VERSION 5.8 ;
BUSBITCHARS "[]" ;
DIVIDERCHAR "/" ;
UNITS
    DATABASE MICRONS 1000 ;
END UNITS

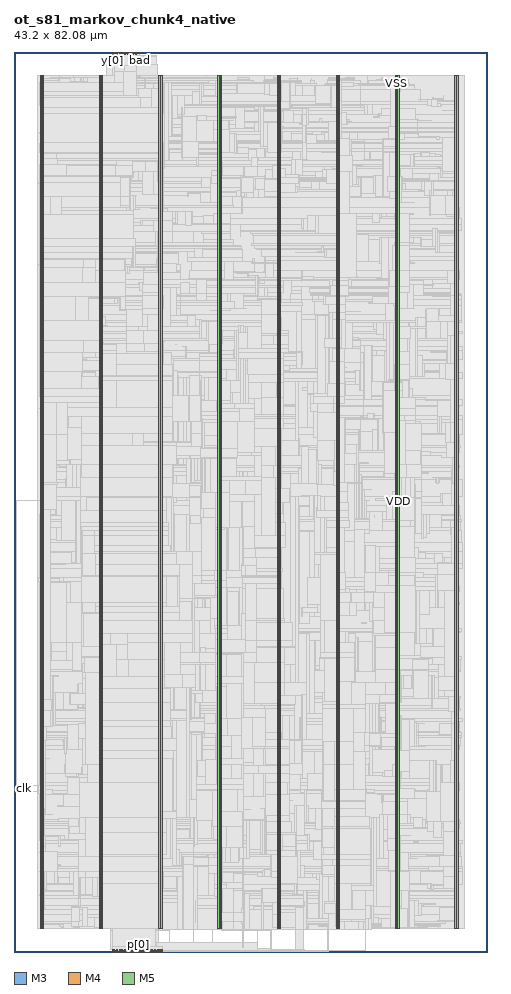
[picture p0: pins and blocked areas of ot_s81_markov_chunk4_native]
MACRO ot_s81_markov_chunk4_native
  FOREIGN ot_s81_markov_chunk4_native 0 0 ;
  CLASS BLOCK ;
  SIZE 43.2 BY 82.08 ;
  PIN bad
    DIRECTION OUTPUT ;
    USE SIGNAL ;
    PORT
      LAYER M3 ;
        RECT  11.448 81.936 11.466 82.08 ;
    END
  END bad
  PIN clk
    DIRECTION INPUT ;
    USE SIGNAL ;
    PORT
      LAYER M4 ;
        RECT  0 14.88 0.192 14.904 ;
    END
  END clk
  PIN p[0]
    DIRECTION INPUT ;
    USE SIGNAL ;
    PORT
      LAYER M3 ;
        RECT  11.304 0 11.322 0.144 ;
    END
  END p[0]
  PIN p[10]
    DIRECTION INPUT ;
    USE SIGNAL ;
    PORT
      LAYER M3 ;
        RECT  12.024 0 12.042 0.144 ;
    END
  END p[10]
  PIN p[11]
    DIRECTION INPUT ;
    USE SIGNAL ;
    PORT
      LAYER M5 ;
        RECT  12.048 0 12.072 0.192 ;
    END
  END p[11]
  PIN p[12]
    DIRECTION INPUT ;
    USE SIGNAL ;
    PORT
      LAYER M3 ;
        RECT  12.168 0 12.186 0.144 ;
    END
  END p[12]
  PIN p[13]
    DIRECTION INPUT ;
    USE SIGNAL ;
    PORT
      LAYER M5 ;
        RECT  12.192 0 12.216 0.192 ;
    END
  END p[13]
  PIN p[14]
    DIRECTION INPUT ;
    USE SIGNAL ;
    PORT
      LAYER M3 ;
        RECT  12.312 0 12.33 0.144 ;
    END
  END p[14]
  PIN p[15]
    DIRECTION INPUT ;
    USE SIGNAL ;
    PORT
      LAYER M5 ;
        RECT  12.336 0 12.36 0.192 ;
    END
  END p[15]
  PIN p[16]
    DIRECTION INPUT ;
    USE SIGNAL ;
    PORT
      LAYER M3 ;
        RECT  12.456 0 12.474 0.144 ;
    END
  END p[16]
  PIN p[17]
    DIRECTION INPUT ;
    USE SIGNAL ;
    PORT
      LAYER M5 ;
        RECT  12.48 0 12.504 0.192 ;
    END
  END p[17]
  PIN p[18]
    DIRECTION INPUT ;
    USE SIGNAL ;
    PORT
      LAYER M3 ;
        RECT  12.6 0 12.618 0.144 ;
    END
  END p[18]
  PIN p[19]
    DIRECTION INPUT ;
    USE SIGNAL ;
    PORT
      LAYER M5 ;
        RECT  12.624 0 12.648 0.192 ;
    END
  END p[19]
  PIN p[1]
    DIRECTION INPUT ;
    USE SIGNAL ;
    PORT
      LAYER M5 ;
        RECT  11.328 0 11.352 0.192 ;
    END
  END p[1]
  PIN p[20]
    DIRECTION INPUT ;
    USE SIGNAL ;
    PORT
      LAYER M3 ;
        RECT  12.744 0 12.762 0.144 ;
    END
  END p[20]
  PIN p[21]
    DIRECTION INPUT ;
    USE SIGNAL ;
    PORT
      LAYER M5 ;
        RECT  12.768 0 12.792 0.192 ;
    END
  END p[21]
  PIN p[22]
    DIRECTION INPUT ;
    USE SIGNAL ;
    PORT
      LAYER M3 ;
        RECT  12.888 0 12.906 0.144 ;
    END
  END p[22]
  PIN p[23]
    DIRECTION INPUT ;
    USE SIGNAL ;
    PORT
      LAYER M5 ;
        RECT  12.912 0 12.936 0.192 ;
    END
  END p[23]
  PIN p[24]
    DIRECTION INPUT ;
    USE SIGNAL ;
    PORT
      LAYER M3 ;
        RECT  13.032 0 13.05 0.144 ;
    END
  END p[24]
  PIN p[25]
    DIRECTION INPUT ;
    USE SIGNAL ;
    PORT
      LAYER M5 ;
        RECT  13.056 0 13.08 0.192 ;
    END
  END p[25]
  PIN p[26]
    DIRECTION INPUT ;
    USE SIGNAL ;
    PORT
      LAYER M3 ;
        RECT  13.176 0 13.194 0.144 ;
    END
  END p[26]
  PIN p[27]
    DIRECTION INPUT ;
    USE SIGNAL ;
    PORT
      LAYER M5 ;
        RECT  13.2 0 13.224 0.192 ;
    END
  END p[27]
  PIN p[28]
    DIRECTION INPUT ;
    USE SIGNAL ;
    PORT
      LAYER M3 ;
        RECT  13.32 0 13.338 0.144 ;
    END
  END p[28]
  PIN p[29]
    DIRECTION INPUT ;
    USE SIGNAL ;
    PORT
      LAYER M5 ;
        RECT  13.344 0 13.368 0.192 ;
    END
  END p[29]
  PIN p[2]
    DIRECTION INPUT ;
    USE SIGNAL ;
    PORT
      LAYER M3 ;
        RECT  11.448 0 11.466 0.144 ;
    END
  END p[2]
  PIN p[30]
    DIRECTION INPUT ;
    USE SIGNAL ;
    PORT
      LAYER M3 ;
        RECT  13.464 0 13.482 0.144 ;
    END
  END p[30]
  PIN p[31]
    DIRECTION INPUT ;
    USE SIGNAL ;
    PORT
      LAYER M5 ;
        RECT  13.488 0 13.512 0.192 ;
    END
  END p[31]
  PIN p[3]
    DIRECTION INPUT ;
    USE SIGNAL ;
    PORT
      LAYER M5 ;
        RECT  11.472 0 11.496 0.192 ;
    END
  END p[3]
  PIN p[4]
    DIRECTION INPUT ;
    USE SIGNAL ;
    PORT
      LAYER M3 ;
        RECT  11.592 0 11.61 0.144 ;
    END
  END p[4]
  PIN p[5]
    DIRECTION INPUT ;
    USE SIGNAL ;
    PORT
      LAYER M5 ;
        RECT  11.616 0 11.64 0.192 ;
    END
  END p[5]
  PIN p[6]
    DIRECTION INPUT ;
    USE SIGNAL ;
    PORT
      LAYER M3 ;
        RECT  11.736 0 11.754 0.144 ;
    END
  END p[6]
  PIN p[7]
    DIRECTION INPUT ;
    USE SIGNAL ;
    PORT
      LAYER M5 ;
        RECT  11.76 0 11.784 0.192 ;
    END
  END p[7]
  PIN p[8]
    DIRECTION INPUT ;
    USE SIGNAL ;
    PORT
      LAYER M3 ;
        RECT  11.88 0 11.898 0.144 ;
    END
  END p[8]
  PIN p[9]
    DIRECTION INPUT ;
    USE SIGNAL ;
    PORT
      LAYER M5 ;
        RECT  11.904 0 11.928 0.192 ;
    END
  END p[9]
  PIN rst_n
    DIRECTION INPUT ;
    USE SIGNAL ;
    PORT
      LAYER M4 ;
        RECT  0 15.024 0.192 15.048 ;
    END
  END rst_n
  PIN sum[0]
    DIRECTION INPUT ;
    USE SIGNAL ;
    PORT
      LAYER M3 ;
        RECT  9 0 9.018 0.144 ;
    END
  END sum[0]
  PIN sum[10]
    DIRECTION INPUT ;
    USE SIGNAL ;
    PORT
      LAYER M3 ;
        RECT  9.72 0 9.738 0.144 ;
    END
  END sum[10]
  PIN sum[11]
    DIRECTION INPUT ;
    USE SIGNAL ;
    PORT
      LAYER M5 ;
        RECT  9.744 0 9.768 0.192 ;
    END
  END sum[11]
  PIN sum[12]
    DIRECTION INPUT ;
    USE SIGNAL ;
    PORT
      LAYER M3 ;
        RECT  9.864 0 9.882 0.144 ;
    END
  END sum[12]
  PIN sum[13]
    DIRECTION INPUT ;
    USE SIGNAL ;
    PORT
      LAYER M5 ;
        RECT  9.888 0 9.912 0.192 ;
    END
  END sum[13]
  PIN sum[14]
    DIRECTION INPUT ;
    USE SIGNAL ;
    PORT
      LAYER M3 ;
        RECT  10.008 0 10.026 0.144 ;
    END
  END sum[14]
  PIN sum[15]
    DIRECTION INPUT ;
    USE SIGNAL ;
    PORT
      LAYER M5 ;
        RECT  10.032 0 10.056 0.192 ;
    END
  END sum[15]
  PIN sum[16]
    DIRECTION INPUT ;
    USE SIGNAL ;
    PORT
      LAYER M3 ;
        RECT  10.152 0 10.17 0.144 ;
    END
  END sum[16]
  PIN sum[17]
    DIRECTION INPUT ;
    USE SIGNAL ;
    PORT
      LAYER M5 ;
        RECT  10.176 0 10.2 0.192 ;
    END
  END sum[17]
  PIN sum[18]
    DIRECTION INPUT ;
    USE SIGNAL ;
    PORT
      LAYER M3 ;
        RECT  10.296 0 10.314 0.144 ;
    END
  END sum[18]
  PIN sum[19]
    DIRECTION INPUT ;
    USE SIGNAL ;
    PORT
      LAYER M5 ;
        RECT  10.32 0 10.344 0.192 ;
    END
  END sum[19]
  PIN sum[1]
    DIRECTION INPUT ;
    USE SIGNAL ;
    PORT
      LAYER M5 ;
        RECT  9.024 0 9.048 0.192 ;
    END
  END sum[1]
  PIN sum[20]
    DIRECTION INPUT ;
    USE SIGNAL ;
    PORT
      LAYER M3 ;
        RECT  10.44 0 10.458 0.144 ;
    END
  END sum[20]
  PIN sum[21]
    DIRECTION INPUT ;
    USE SIGNAL ;
    PORT
      LAYER M5 ;
        RECT  10.464 0 10.488 0.192 ;
    END
  END sum[21]
  PIN sum[22]
    DIRECTION INPUT ;
    USE SIGNAL ;
    PORT
      LAYER M3 ;
        RECT  10.584 0 10.602 0.144 ;
    END
  END sum[22]
  PIN sum[23]
    DIRECTION INPUT ;
    USE SIGNAL ;
    PORT
      LAYER M5 ;
        RECT  10.608 0 10.632 0.192 ;
    END
  END sum[23]
  PIN sum[24]
    DIRECTION INPUT ;
    USE SIGNAL ;
    PORT
      LAYER M3 ;
        RECT  10.728 0 10.746 0.144 ;
    END
  END sum[24]
  PIN sum[25]
    DIRECTION INPUT ;
    USE SIGNAL ;
    PORT
      LAYER M5 ;
        RECT  10.752 0 10.776 0.192 ;
    END
  END sum[25]
  PIN sum[26]
    DIRECTION INPUT ;
    USE SIGNAL ;
    PORT
      LAYER M3 ;
        RECT  10.872 0 10.89 0.144 ;
    END
  END sum[26]
  PIN sum[27]
    DIRECTION INPUT ;
    USE SIGNAL ;
    PORT
      LAYER M5 ;
        RECT  10.896 0 10.92 0.192 ;
    END
  END sum[27]
  PIN sum[28]
    DIRECTION INPUT ;
    USE SIGNAL ;
    PORT
      LAYER M3 ;
        RECT  11.016 0 11.034 0.144 ;
    END
  END sum[28]
  PIN sum[29]
    DIRECTION INPUT ;
    USE SIGNAL ;
    PORT
      LAYER M5 ;
        RECT  11.04 0 11.064 0.192 ;
    END
  END sum[29]
  PIN sum[2]
    DIRECTION INPUT ;
    USE SIGNAL ;
    PORT
      LAYER M3 ;
        RECT  9.144 0 9.162 0.144 ;
    END
  END sum[2]
  PIN sum[30]
    DIRECTION INPUT ;
    USE SIGNAL ;
    PORT
      LAYER M3 ;
        RECT  11.16 0 11.178 0.144 ;
    END
  END sum[30]
  PIN sum[31]
    DIRECTION INPUT ;
    USE SIGNAL ;
    PORT
      LAYER M5 ;
        RECT  11.184 0 11.208 0.192 ;
    END
  END sum[31]
  PIN sum[3]
    DIRECTION INPUT ;
    USE SIGNAL ;
    PORT
      LAYER M5 ;
        RECT  9.168 0 9.192 0.192 ;
    END
  END sum[3]
  PIN sum[4]
    DIRECTION INPUT ;
    USE SIGNAL ;
    PORT
      LAYER M3 ;
        RECT  9.288 0 9.306 0.144 ;
    END
  END sum[4]
  PIN sum[5]
    DIRECTION INPUT ;
    USE SIGNAL ;
    PORT
      LAYER M5 ;
        RECT  9.312 0 9.336 0.192 ;
    END
  END sum[5]
  PIN sum[6]
    DIRECTION INPUT ;
    USE SIGNAL ;
    PORT
      LAYER M3 ;
        RECT  9.432 0 9.45 0.144 ;
    END
  END sum[6]
  PIN sum[7]
    DIRECTION INPUT ;
    USE SIGNAL ;
    PORT
      LAYER M5 ;
        RECT  9.456 0 9.48 0.192 ;
    END
  END sum[7]
  PIN sum[8]
    DIRECTION INPUT ;
    USE SIGNAL ;
    PORT
      LAYER M3 ;
        RECT  9.576 0 9.594 0.144 ;
    END
  END sum[8]
  PIN sum[9]
    DIRECTION INPUT ;
    USE SIGNAL ;
    PORT
      LAYER M5 ;
        RECT  9.6 0 9.624 0.192 ;
    END
  END sum[9]
  PIN vin
    DIRECTION INPUT ;
    USE SIGNAL ;
    PORT
      LAYER M4 ;
        RECT  0 15.168 0.192 15.192 ;
    END
  END vin
  PIN vout
    DIRECTION OUTPUT ;
    USE SIGNAL ;
    PORT
      LAYER M3 ;
        RECT  11.304 81.936 11.322 82.08 ;
    END
  END vout
  PIN y[0]
    DIRECTION OUTPUT ;
    USE SIGNAL ;
    PORT
      LAYER M3 ;
        RECT  9 81.936 9.018 82.08 ;
    END
  END y[0]
  PIN y[10]
    DIRECTION OUTPUT ;
    USE SIGNAL ;
    PORT
      LAYER M3 ;
        RECT  9.72 81.936 9.738 82.08 ;
    END
  END y[10]
  PIN y[11]
    DIRECTION OUTPUT ;
    USE SIGNAL ;
    PORT
      LAYER M5 ;
        RECT  9.744 81.888 9.768 82.08 ;
    END
  END y[11]
  PIN y[12]
    DIRECTION OUTPUT ;
    USE SIGNAL ;
    PORT
      LAYER M3 ;
        RECT  9.864 81.936 9.882 82.08 ;
    END
  END y[12]
  PIN y[13]
    DIRECTION OUTPUT ;
    USE SIGNAL ;
    PORT
      LAYER M5 ;
        RECT  9.888 81.888 9.912 82.08 ;
    END
  END y[13]
  PIN y[14]
    DIRECTION OUTPUT ;
    USE SIGNAL ;
    PORT
      LAYER M3 ;
        RECT  10.008 81.936 10.026 82.08 ;
    END
  END y[14]
  PIN y[15]
    DIRECTION OUTPUT ;
    USE SIGNAL ;
    PORT
      LAYER M5 ;
        RECT  10.032 81.888 10.056 82.08 ;
    END
  END y[15]
  PIN y[16]
    DIRECTION OUTPUT ;
    USE SIGNAL ;
    PORT
      LAYER M3 ;
        RECT  10.152 81.936 10.17 82.08 ;
    END
  END y[16]
  PIN y[17]
    DIRECTION OUTPUT ;
    USE SIGNAL ;
    PORT
      LAYER M5 ;
        RECT  10.176 81.888 10.2 82.08 ;
    END
  END y[17]
  PIN y[18]
    DIRECTION OUTPUT ;
    USE SIGNAL ;
    PORT
      LAYER M3 ;
        RECT  10.296 81.936 10.314 82.08 ;
    END
  END y[18]
  PIN y[19]
    DIRECTION OUTPUT ;
    USE SIGNAL ;
    PORT
      LAYER M5 ;
        RECT  10.32 81.888 10.344 82.08 ;
    END
  END y[19]
  PIN y[1]
    DIRECTION OUTPUT ;
    USE SIGNAL ;
    PORT
      LAYER M5 ;
        RECT  9.024 81.888 9.048 82.08 ;
    END
  END y[1]
  PIN y[20]
    DIRECTION OUTPUT ;
    USE SIGNAL ;
    PORT
      LAYER M3 ;
        RECT  10.44 81.936 10.458 82.08 ;
    END
  END y[20]
  PIN y[21]
    DIRECTION OUTPUT ;
    USE SIGNAL ;
    PORT
      LAYER M5 ;
        RECT  10.464 81.888 10.488 82.08 ;
    END
  END y[21]
  PIN y[22]
    DIRECTION OUTPUT ;
    USE SIGNAL ;
    PORT
      LAYER M3 ;
        RECT  10.584 81.936 10.602 82.08 ;
    END
  END y[22]
  PIN y[23]
    DIRECTION OUTPUT ;
    USE SIGNAL ;
    PORT
      LAYER M5 ;
        RECT  10.608 81.888 10.632 82.08 ;
    END
  END y[23]
  PIN y[24]
    DIRECTION OUTPUT ;
    USE SIGNAL ;
    PORT
      LAYER M3 ;
        RECT  10.728 81.936 10.746 82.08 ;
    END
  END y[24]
  PIN y[25]
    DIRECTION OUTPUT ;
    USE SIGNAL ;
    PORT
      LAYER M5 ;
        RECT  10.752 81.888 10.776 82.08 ;
    END
  END y[25]
  PIN y[26]
    DIRECTION OUTPUT ;
    USE SIGNAL ;
    PORT
      LAYER M3 ;
        RECT  10.872 81.936 10.89 82.08 ;
    END
  END y[26]
  PIN y[27]
    DIRECTION OUTPUT ;
    USE SIGNAL ;
    PORT
      LAYER M5 ;
        RECT  10.896 81.888 10.92 82.08 ;
    END
  END y[27]
  PIN y[28]
    DIRECTION OUTPUT ;
    USE SIGNAL ;
    PORT
      LAYER M3 ;
        RECT  11.016 81.936 11.034 82.08 ;
    END
  END y[28]
  PIN y[29]
    DIRECTION OUTPUT ;
    USE SIGNAL ;
    PORT
      LAYER M5 ;
        RECT  11.04 81.888 11.064 82.08 ;
    END
  END y[29]
  PIN y[2]
    DIRECTION OUTPUT ;
    USE SIGNAL ;
    PORT
      LAYER M3 ;
        RECT  9.144 81.936 9.162 82.08 ;
    END
  END y[2]
  PIN y[30]
    DIRECTION OUTPUT ;
    USE SIGNAL ;
    PORT
      LAYER M3 ;
        RECT  11.16 81.936 11.178 82.08 ;
    END
  END y[30]
  PIN y[31]
    DIRECTION OUTPUT ;
    USE SIGNAL ;
    PORT
      LAYER M5 ;
        RECT  11.184 81.888 11.208 82.08 ;
    END
  END y[31]
  PIN y[3]
    DIRECTION OUTPUT ;
    USE SIGNAL ;
    PORT
      LAYER M5 ;
        RECT  9.168 81.888 9.192 82.08 ;
    END
  END y[3]
  PIN y[4]
    DIRECTION OUTPUT ;
    USE SIGNAL ;
    PORT
      LAYER M3 ;
        RECT  9.288 81.936 9.306 82.08 ;
    END
  END y[4]
  PIN y[5]
    DIRECTION OUTPUT ;
    USE SIGNAL ;
    PORT
      LAYER M5 ;
        RECT  9.312 81.888 9.336 82.08 ;
    END
  END y[5]
  PIN y[6]
    DIRECTION OUTPUT ;
    USE SIGNAL ;
    PORT
      LAYER M3 ;
        RECT  9.432 81.936 9.45 82.08 ;
    END
  END y[6]
  PIN y[7]
    DIRECTION OUTPUT ;
    USE SIGNAL ;
    PORT
      LAYER M5 ;
        RECT  9.456 81.888 9.48 82.08 ;
    END
  END y[7]
  PIN y[8]
    DIRECTION OUTPUT ;
    USE SIGNAL ;
    PORT
      LAYER M3 ;
        RECT  9.576 81.936 9.594 82.08 ;
    END
  END y[8]
  PIN y[9]
    DIRECTION OUTPUT ;
    USE SIGNAL ;
    PORT
      LAYER M5 ;
        RECT  9.6 81.888 9.624 82.08 ;
    END
  END y[9]
  PIN VDD
    DIRECTION INOUT ;
    USE POWER ;
    PORT
      LAYER M5 ;
        RECT  40.392 2.151 40.512 79.929 ;
        RECT  34.992 2.151 35.112 79.929 ;
        RECT  29.592 2.151 29.712 79.929 ;
        RECT  24.192 2.151 24.312 79.929 ;
        RECT  18.792 2.151 18.912 79.929 ;
        RECT  13.392 2.151 13.512 79.929 ;
        RECT  7.992 2.151 8.112 79.929 ;
        RECT  2.592 2.151 2.712 79.929 ;
    END
  END VDD
  PIN VSS
    DIRECTION INOUT ;
    USE GROUND ;
    PORT
      LAYER M5 ;
        RECT  40.2 2.137 40.32 79.943 ;
        RECT  34.8 2.137 34.92 79.943 ;
        RECT  29.4 2.137 29.52 79.943 ;
        RECT  24 2.137 24.12 79.943 ;
        RECT  18.6 2.137 18.72 79.943 ;
        RECT  13.2 2.137 13.32 79.943 ;
        RECT  7.8 2.137 7.92 79.943 ;
        RECT  2.4 2.137 2.52 79.943 ;
    END
  END VSS
  # OT_OBS_CLOSED layer=M5 d_um=1.536 added=327
  OBS
    LAYER RVTN ;
     RECT  2.16 2.16 41.04 2.295 ;
     RECT  2.16 2.565 41.04 2.835 ;
     RECT  2.16 3.105 41.04 3.375 ;
     RECT  2.16 3.645 41.04 3.915 ;
     RECT  2.16 4.185 41.04 4.455 ;
     RECT  2.16 4.725 41.04 4.995 ;
     RECT  2.16 5.265 41.04 5.535 ;
     RECT  2.16 5.805 41.04 6.075 ;
     RECT  2.16 6.345 41.04 6.615 ;
     RECT  2.16 6.885 41.04 7.155 ;
     RECT  2.16 7.425 41.04 7.695 ;
     RECT  2.16 7.965 41.04 8.235 ;
     RECT  2.16 8.505 41.04 8.775 ;
     RECT  2.16 9.045 41.04 9.315 ;
     RECT  2.16 9.585 41.04 9.855 ;
     RECT  2.16 10.125 41.04 10.395 ;
     RECT  2.16 10.665 41.04 10.935 ;
     RECT  2.16 11.205 41.04 11.475 ;
     RECT  2.16 11.745 41.04 12.015 ;
     RECT  2.16 12.285 41.04 12.555 ;
     RECT  2.16 12.825 41.04 13.095 ;
     RECT  2.16 13.365 41.04 13.635 ;
     RECT  2.16 13.905 41.04 14.175 ;
     RECT  2.16 14.445 41.04 14.715 ;
     RECT  2.16 14.985 41.04 15.255 ;
     RECT  2.16 15.525 41.04 15.795 ;
     RECT  2.16 16.065 41.04 16.335 ;
     RECT  2.16 16.605 41.04 16.875 ;
     RECT  2.16 17.145 41.04 17.415 ;
     RECT  2.16 17.685 41.04 17.955 ;
     RECT  2.16 18.225 41.04 18.495 ;
     RECT  2.16 18.765 41.04 19.035 ;
     RECT  2.16 19.305 41.04 19.575 ;
     RECT  2.16 19.845 41.04 20.115 ;
     RECT  2.16 20.385 41.04 20.655 ;
     RECT  2.16 20.925 41.04 21.195 ;
     RECT  2.16 21.465 41.04 21.735 ;
     RECT  2.16 22.005 41.04 22.275 ;
     RECT  2.16 22.545 41.04 22.815 ;
     RECT  2.16 23.085 41.04 23.355 ;
     RECT  2.16 23.625 41.04 23.895 ;
     RECT  2.16 24.165 41.04 24.435 ;
     RECT  2.16 24.705 41.04 24.975 ;
     RECT  2.16 25.245 41.04 25.515 ;
     RECT  2.16 25.785 41.04 26.055 ;
     RECT  2.16 26.325 41.04 26.595 ;
     RECT  2.16 26.865 41.04 27.135 ;
     RECT  2.16 27.405 41.04 27.675 ;
     RECT  2.16 27.945 41.04 28.215 ;
     RECT  2.16 28.485 41.04 28.755 ;
     RECT  2.16 29.025 41.04 29.295 ;
     RECT  2.16 29.565 41.04 29.835 ;
     RECT  2.16 30.105 41.04 30.375 ;
     RECT  2.16 30.645 41.04 30.915 ;
     RECT  2.16 31.185 41.04 31.455 ;
     RECT  2.16 31.725 41.04 31.995 ;
     RECT  2.16 32.265 41.04 32.535 ;
     RECT  2.16 32.805 41.04 33.075 ;
     RECT  2.16 33.345 41.04 33.615 ;
     RECT  2.16 33.885 41.04 34.155 ;
     RECT  2.16 34.425 41.04 34.695 ;
     RECT  2.16 34.965 41.04 35.235 ;
     RECT  2.16 35.505 41.04 35.775 ;
     RECT  2.16 36.045 41.04 36.315 ;
     RECT  2.16 36.585 41.04 36.855 ;
     RECT  2.16 37.125 41.04 37.395 ;
     RECT  2.16 37.665 41.04 37.935 ;
     RECT  2.16 38.205 41.04 38.475 ;
     RECT  2.16 38.745 41.04 39.015 ;
     RECT  2.16 39.285 41.04 39.555 ;
     RECT  2.16 39.825 41.04 40.095 ;
     RECT  2.16 40.365 41.04 40.635 ;
     RECT  2.16 40.905 41.04 41.175 ;
     RECT  2.16 41.445 41.04 41.715 ;
     RECT  2.16 41.985 41.04 42.255 ;
     RECT  2.16 42.525 41.04 42.795 ;
     RECT  2.16 43.065 41.04 43.335 ;
     RECT  2.16 43.605 41.04 43.875 ;
     RECT  2.16 44.145 41.04 44.415 ;
     RECT  2.16 44.685 41.04 44.955 ;
     RECT  2.16 45.225 41.04 45.495 ;
     RECT  2.16 45.765 41.04 46.035 ;
     RECT  2.16 46.305 41.04 46.575 ;
     RECT  2.16 46.845 41.04 47.115 ;
     RECT  2.16 47.385 41.04 47.655 ;
     RECT  2.16 47.925 41.04 48.195 ;
     RECT  2.16 48.465 41.04 48.735 ;
     RECT  2.16 49.005 41.04 49.275 ;
     RECT  2.16 49.545 41.04 49.815 ;
     RECT  2.16 50.085 41.04 50.355 ;
     RECT  2.16 50.625 41.04 50.895 ;
     RECT  2.16 51.165 41.04 51.435 ;
     RECT  2.16 51.705 41.04 51.975 ;
     RECT  2.16 52.245 41.04 52.515 ;
     RECT  2.16 52.785 41.04 53.055 ;
     RECT  2.16 53.325 41.04 53.595 ;
     RECT  2.16 53.865 41.04 54.135 ;
     RECT  2.16 54.405 41.04 54.675 ;
     RECT  2.16 54.945 41.04 55.215 ;
     RECT  2.16 55.485 41.04 55.755 ;
     RECT  2.16 56.025 41.04 56.295 ;
     RECT  2.16 56.565 41.04 56.835 ;
     RECT  2.16 57.105 41.04 57.375 ;
     RECT  2.16 57.645 41.04 57.915 ;
     RECT  2.16 58.185 41.04 58.455 ;
     RECT  2.16 58.725 41.04 58.995 ;
     RECT  2.16 59.265 41.04 59.535 ;
     RECT  2.16 59.805 41.04 60.075 ;
     RECT  2.16 60.345 41.04 60.615 ;
     RECT  2.16 60.885 41.04 61.155 ;
     RECT  2.16 61.425 41.04 61.695 ;
     RECT  2.16 61.965 41.04 62.235 ;
     RECT  2.16 62.505 41.04 62.775 ;
     RECT  2.16 63.045 41.04 63.315 ;
     RECT  2.16 63.585 41.04 63.855 ;
     RECT  2.16 64.125 41.04 64.395 ;
     RECT  2.16 64.665 41.04 64.935 ;
     RECT  2.16 65.205 41.04 65.475 ;
     RECT  2.16 65.745 41.04 66.015 ;
     RECT  2.16 66.285 41.04 66.555 ;
     RECT  2.16 66.825 41.04 67.095 ;
     RECT  2.16 67.365 41.04 67.635 ;
     RECT  2.16 67.905 41.04 68.175 ;
     RECT  2.16 68.445 41.04 68.715 ;
     RECT  2.16 68.985 41.04 69.255 ;
     RECT  2.16 69.525 41.04 69.795 ;
     RECT  2.16 70.065 41.04 70.335 ;
     RECT  2.16 70.605 41.04 70.875 ;
     RECT  2.16 71.145 41.04 71.415 ;
     RECT  2.16 71.685 41.04 71.955 ;
     RECT  2.16 72.225 41.04 72.495 ;
     RECT  2.16 72.765 41.04 73.035 ;
     RECT  2.16 73.305 41.04 73.575 ;
     RECT  2.16 73.845 41.04 74.115 ;
     RECT  2.16 74.385 41.04 74.655 ;
     RECT  2.16 74.925 41.04 75.195 ;
     RECT  2.16 75.465 41.04 75.735 ;
     RECT  2.16 76.005 41.04 76.275 ;
     RECT  2.16 76.545 41.04 76.815 ;
     RECT  2.16 77.085 41.04 77.355 ;
     RECT  2.16 77.625 41.04 77.895 ;
     RECT  2.16 78.165 41.04 78.435 ;
     RECT  2.16 78.705 41.04 78.975 ;
     RECT  2.16 79.245 41.04 79.515 ;
     RECT  2.16 79.785 41.04 79.92 ;
    LAYER RVTP ;
     RECT  2.16 2.295 41.04 2.565 ;
     RECT  2.16 2.835 41.04 3.105 ;
     RECT  2.16 3.375 41.04 3.645 ;
     RECT  2.16 3.915 41.04 4.185 ;
     RECT  2.16 4.455 41.04 4.725 ;
     RECT  2.16 4.995 41.04 5.265 ;
     RECT  2.16 5.535 41.04 5.805 ;
     RECT  2.16 6.075 41.04 6.345 ;
     RECT  2.16 6.615 41.04 6.885 ;
     RECT  2.16 7.155 41.04 7.425 ;
     RECT  2.16 7.695 41.04 7.965 ;
     RECT  2.16 8.235 41.04 8.505 ;
     RECT  2.16 8.775 41.04 9.045 ;
     RECT  2.16 9.315 41.04 9.585 ;
     RECT  2.16 9.855 41.04 10.125 ;
     RECT  2.16 10.395 41.04 10.665 ;
     RECT  2.16 10.935 41.04 11.205 ;
     RECT  2.16 11.475 41.04 11.745 ;
     RECT  2.16 12.015 41.04 12.285 ;
     RECT  2.16 12.555 41.04 12.825 ;
     RECT  2.16 13.095 41.04 13.365 ;
     RECT  2.16 13.635 41.04 13.905 ;
     RECT  2.16 14.175 41.04 14.445 ;
     RECT  2.16 14.715 41.04 14.985 ;
     RECT  2.16 15.255 41.04 15.525 ;
     RECT  2.16 15.795 41.04 16.065 ;
     RECT  2.16 16.335 41.04 16.605 ;
     RECT  2.16 16.875 41.04 17.145 ;
     RECT  2.16 17.415 41.04 17.685 ;
     RECT  2.16 17.955 41.04 18.225 ;
     RECT  2.16 18.495 41.04 18.765 ;
     RECT  2.16 19.035 41.04 19.305 ;
     RECT  2.16 19.575 41.04 19.845 ;
     RECT  2.16 20.115 41.04 20.385 ;
     RECT  2.16 20.655 41.04 20.925 ;
     RECT  2.16 21.195 41.04 21.465 ;
     RECT  2.16 21.735 41.04 22.005 ;
     RECT  2.16 22.275 41.04 22.545 ;
     RECT  2.16 22.815 41.04 23.085 ;
     RECT  2.16 23.355 41.04 23.625 ;
     RECT  2.16 23.895 41.04 24.165 ;
     RECT  2.16 24.435 41.04 24.705 ;
     RECT  2.16 24.975 41.04 25.245 ;
     RECT  2.16 25.515 41.04 25.785 ;
     RECT  2.16 26.055 41.04 26.325 ;
     RECT  2.16 26.595 41.04 26.865 ;
     RECT  2.16 27.135 41.04 27.405 ;
     RECT  2.16 27.675 41.04 27.945 ;
     RECT  2.16 28.215 41.04 28.485 ;
     RECT  2.16 28.755 41.04 29.025 ;
     RECT  2.16 29.295 41.04 29.565 ;
     RECT  2.16 29.835 41.04 30.105 ;
     RECT  2.16 30.375 41.04 30.645 ;
     RECT  2.16 30.915 41.04 31.185 ;
     RECT  2.16 31.455 41.04 31.725 ;
     RECT  2.16 31.995 41.04 32.265 ;
     RECT  2.16 32.535 41.04 32.805 ;
     RECT  2.16 33.075 41.04 33.345 ;
     RECT  2.16 33.615 41.04 33.885 ;
     RECT  2.16 34.155 41.04 34.425 ;
     RECT  2.16 34.695 41.04 34.965 ;
     RECT  2.16 35.235 41.04 35.505 ;
     RECT  2.16 35.775 41.04 36.045 ;
     RECT  2.16 36.315 41.04 36.585 ;
     RECT  2.16 36.855 41.04 37.125 ;
     RECT  2.16 37.395 41.04 37.665 ;
     RECT  2.16 37.935 41.04 38.205 ;
     RECT  2.16 38.475 41.04 38.745 ;
     RECT  2.16 39.015 41.04 39.285 ;
     RECT  2.16 39.555 41.04 39.825 ;
     RECT  2.16 40.095 41.04 40.365 ;
     RECT  2.16 40.635 41.04 40.905 ;
     RECT  2.16 41.175 41.04 41.445 ;
     RECT  2.16 41.715 41.04 41.985 ;
     RECT  2.16 42.255 41.04 42.525 ;
     RECT  2.16 42.795 41.04 43.065 ;
     RECT  2.16 43.335 41.04 43.605 ;
     RECT  2.16 43.875 41.04 44.145 ;
     RECT  2.16 44.415 41.04 44.685 ;
     RECT  2.16 44.955 41.04 45.225 ;
     RECT  2.16 45.495 41.04 45.765 ;
     RECT  2.16 46.035 41.04 46.305 ;
     RECT  2.16 46.575 41.04 46.845 ;
     RECT  2.16 47.115 41.04 47.385 ;
     RECT  2.16 47.655 41.04 47.925 ;
     RECT  2.16 48.195 41.04 48.465 ;
     RECT  2.16 48.735 41.04 49.005 ;
     RECT  2.16 49.275 41.04 49.545 ;
     RECT  2.16 49.815 41.04 50.085 ;
     RECT  2.16 50.355 41.04 50.625 ;
     RECT  2.16 50.895 41.04 51.165 ;
     RECT  2.16 51.435 41.04 51.705 ;
     RECT  2.16 51.975 41.04 52.245 ;
     RECT  2.16 52.515 41.04 52.785 ;
     RECT  2.16 53.055 41.04 53.325 ;
     RECT  2.16 53.595 41.04 53.865 ;
     RECT  2.16 54.135 41.04 54.405 ;
     RECT  2.16 54.675 41.04 54.945 ;
     RECT  2.16 55.215 41.04 55.485 ;
     RECT  2.16 55.755 41.04 56.025 ;
     RECT  2.16 56.295 41.04 56.565 ;
     RECT  2.16 56.835 41.04 57.105 ;
     RECT  2.16 57.375 41.04 57.645 ;
     RECT  2.16 57.915 41.04 58.185 ;
     RECT  2.16 58.455 41.04 58.725 ;
     RECT  2.16 58.995 41.04 59.265 ;
     RECT  2.16 59.535 41.04 59.805 ;
     RECT  2.16 60.075 41.04 60.345 ;
     RECT  2.16 60.615 41.04 60.885 ;
     RECT  2.16 61.155 41.04 61.425 ;
     RECT  2.16 61.695 41.04 61.965 ;
     RECT  2.16 62.235 41.04 62.505 ;
     RECT  2.16 62.775 41.04 63.045 ;
     RECT  2.16 63.315 41.04 63.585 ;
     RECT  2.16 63.855 41.04 64.125 ;
     RECT  2.16 64.395 41.04 64.665 ;
     RECT  2.16 64.935 41.04 65.205 ;
     RECT  2.16 65.475 41.04 65.745 ;
     RECT  2.16 66.015 41.04 66.285 ;
     RECT  2.16 66.555 41.04 66.825 ;
     RECT  2.16 67.095 41.04 67.365 ;
     RECT  2.16 67.635 41.04 67.905 ;
     RECT  2.16 68.175 41.04 68.445 ;
     RECT  2.16 68.715 41.04 68.985 ;
     RECT  2.16 69.255 41.04 69.525 ;
     RECT  2.16 69.795 41.04 70.065 ;
     RECT  2.16 70.335 41.04 70.605 ;
     RECT  2.16 70.875 41.04 71.145 ;
     RECT  2.16 71.415 41.04 71.685 ;
     RECT  2.16 71.955 41.04 72.225 ;
     RECT  2.16 72.495 41.04 72.765 ;
     RECT  2.16 73.035 41.04 73.305 ;
     RECT  2.16 73.575 41.04 73.845 ;
     RECT  2.16 74.115 41.04 74.385 ;
     RECT  2.16 74.655 41.04 74.925 ;
     RECT  2.16 75.195 41.04 75.465 ;
     RECT  2.16 75.735 41.04 76.005 ;
     RECT  2.16 76.275 41.04 76.545 ;
     RECT  2.16 76.815 41.04 77.085 ;
     RECT  2.16 77.355 41.04 77.625 ;
     RECT  2.16 77.895 41.04 78.165 ;
     RECT  2.16 78.435 41.04 78.705 ;
     RECT  2.16 78.975 41.04 79.245 ;
     RECT  2.16 79.515 41.04 79.785 ;
    LAYER M1 ;
     RECT  2.16 2.151 41.04 79.929 ;
    LAYER M2 ;
     RECT  0.211 14.652 2.16 14.67 ;
     RECT  8.815 0.216 8.851 0.234 ;
     RECT  8.851 0.216 8.995 0.279 ;
     RECT  8.995 0.144 9.599 0.324 ;
     RECT  10.399 80.91 10.435 80.928 ;
     RECT  2.16 2.151 10.615 79.929 ;
     RECT  9.599 0.144 10.687 0.162 ;
     RECT  10.435 80.91 10.831 81.549 ;
     RECT  10.687 0.144 10.867 0.198 ;
     RECT  10.831 80.91 10.867 81.594 ;
     RECT  10.867 0.144 11.039 0.234 ;
     RECT  10.867 80.91 11.155 81.666 ;
     RECT  11.039 0.144 11.875 0.162 ;
     RECT  10.615 2.106 12.019 79.929 ;
     RECT  12.019 1.728 12.119 79.929 ;
     RECT  11.155 80.91 12.551 81.738 ;
     RECT  11.875 0.144 12.559 0.234 ;
     RECT  12.559 0.144 12.919 0.864 ;
     RECT  12.551 81.72 12.983 81.738 ;
     RECT  12.551 80.91 13.091 80.928 ;
     RECT  12.119 2.106 13.171 79.929 ;
     RECT  13.171 2.07 18.895 79.929 ;
     RECT  12.919 0.036 22.235 0.864 ;
     RECT  18.895 1.962 22.811 79.929 ;
     RECT  22.811 2.034 23.711 79.929 ;
     RECT  22.235 0.036 25.835 0.126 ;
     RECT  25.835 0.036 28.571 0.09 ;
     RECT  28.571 0.036 28.715 0.054 ;
     RECT  23.711 2.07 30.551 79.929 ;
     RECT  30.551 2.106 32.279 79.929 ;
     RECT  32.279 2.151 41.04 79.929 ;
    LAYER M3 ;
     RECT  12.924 0.031 12.942 0.067 ;
     RECT  28.692 0.031 28.71 0.067 ;
     RECT  12.924 0.067 13.662 0.108 ;
     RECT  9 0.108 13.662 0.167 ;
     RECT  25.812 0.103 25.83 0.187 ;
     RECT  9 0.167 13.41 0.203 ;
     RECT  9 0.203 13.194 0.211 ;
     RECT  25.812 0.187 26.442 0.235 ;
     RECT  23.472 0.283 23.49 0.331 ;
     RECT  23.364 0.331 23.49 0.461 ;
     RECT  22.176 0.811 22.194 0.841 ;
     RECT  22.176 0.841 22.23 1.957 ;
     RECT  23.436 0.461 23.49 1.957 ;
     RECT  8.82 0.211 13.194 1.963 ;
     RECT  14.148 0.211 14.166 1.963 ;
     RECT  22.176 1.957 23.49 2.029 ;
     RECT  18.9 1.957 18.918 2.101 ;
     RECT  25.704 0.235 26.442 2.101 ;
     RECT  32.544 2.059 32.562 2.101 ;
     RECT  18.072 0.427 18.09 2.143 ;
     RECT  18.864 2.101 18.918 2.143 ;
     RECT  21.6 2.029 23.706 2.143 ;
     RECT  28.548 0.067 28.71 2.143 ;
     RECT  18.072 2.143 18.918 2.191 ;
     RECT  21.6 2.143 24.105 2.203 ;
     RECT  28.548 2.143 29.505 2.203 ;
     RECT  30.528 2.065 30.546 2.203 ;
     RECT  5.976 2.191 5.994 2.227 ;
     RECT  7.815 2.143 7.905 2.227 ;
     RECT  37.692 2.191 37.71 2.227 ;
     RECT  7.38 2.227 7.905 2.251 ;
     RECT  8.82 1.963 14.166 2.251 ;
     RECT  25.704 2.101 26.874 2.251 ;
     RECT  33.732 2.191 33.75 2.251 ;
     RECT  34.815 2.143 34.905 2.251 ;
     RECT  7.38 2.251 14.166 2.263 ;
     RECT  30.528 2.203 30.942 2.263 ;
     RECT  32.256 2.101 32.562 2.263 ;
     RECT  33.552 2.251 33.75 2.263 ;
     RECT  25.56 2.251 26.874 2.293 ;
     RECT  7.38 2.263 14.598 2.299 ;
     RECT  21.348 2.203 24.105 2.299 ;
     RECT  28.548 2.203 29.61 2.299 ;
     RECT  30.528 2.263 31.23 2.299 ;
     RECT  32.256 2.263 33.75 2.299 ;
     RECT  6.732 2.299 15.066 2.335 ;
     RECT  16.344 0.475 16.362 2.335 ;
     RECT  18.072 2.191 19.314 2.335 ;
     RECT  4.32 2.263 4.554 2.371 ;
     RECT  6.732 2.335 16.362 2.371 ;
     RECT  17.208 2.101 17.226 2.371 ;
     RECT  21.348 2.299 24.534 2.371 ;
     RECT  25.452 2.293 26.874 2.371 ;
     RECT  28.404 2.299 31.23 2.371 ;
     RECT  32.184 2.299 33.75 2.371 ;
     RECT  34.776 2.251 34.905 2.371 ;
     RECT  35.82 2.251 35.838 2.371 ;
     RECT  37.008 2.227 37.71 2.371 ;
     RECT  38.736 2.263 38.754 2.371 ;
     RECT  2.415 2.143 2.505 2.413 ;
     RECT  27.756 2.371 34.905 2.413 ;
     RECT  40.215 2.143 40.305 2.413 ;
     RECT  27.756 2.413 35.097 2.443 ;
     RECT  35.82 2.371 35.982 2.443 ;
     RECT  36.792 2.371 38.862 2.443 ;
     RECT  17.964 2.335 19.314 2.461 ;
     RECT  20.952 2.371 26.874 2.497 ;
     RECT  27.756 2.443 38.862 2.497 ;
     RECT  2.415 2.413 2.697 2.533 ;
     RECT  4.14 2.371 4.554 2.533 ;
     RECT  5.436 2.227 5.994 2.533 ;
     RECT  6.732 2.371 17.226 2.533 ;
     RECT  2.415 2.533 4.554 2.569 ;
     RECT  2.415 2.569 4.626 2.605 ;
     RECT  5.436 2.533 17.226 2.605 ;
     RECT  17.964 2.461 19.638 2.605 ;
     RECT  20.844 2.497 38.862 2.605 ;
     RECT  2.376 2.605 19.638 2.641 ;
     RECT  20.7 2.605 38.862 2.641 ;
     RECT  40.215 2.413 40.497 2.641 ;
     RECT  2.376 2.641 39.366 2.767 ;
     RECT  40.176 2.641 40.497 2.767 ;
     RECT  2.376 2.767 40.497 3.437 ;
     RECT  2.376 3.437 21.078 3.875 ;
     RECT  21.816 3.437 40.497 4.145 ;
     RECT  2.415 3.875 21.078 4.225 ;
     RECT  21.816 4.145 31.014 4.225 ;
     RECT  2.415 4.225 31.014 4.891 ;
     RECT  31.788 4.145 40.497 4.891 ;
     RECT  2.415 4.891 40.497 5.179 ;
     RECT  2.376 5.179 40.497 5.495 ;
     RECT  2.415 5.495 40.497 5.611 ;
     RECT  2.415 5.611 40.554 6.151 ;
     RECT  2.415 6.151 40.914 7.321 ;
     RECT  2.376 7.321 40.914 7.655 ;
     RECT  2.415 7.655 40.914 7.763 ;
     RECT  2.415 7.763 40.842 8.699 ;
     RECT  2.415 8.699 40.734 8.851 ;
     RECT  2.376 8.851 40.734 9.101 ;
     RECT  2.415 9.101 40.734 9.931 ;
     RECT  2.415 9.931 40.914 10.165 ;
     RECT  2.34 10.165 40.914 10.193 ;
     RECT  2.34 10.193 40.497 11.281 ;
     RECT  2.34 11.281 40.59 11.551 ;
     RECT  2.304 11.551 40.59 11.677 ;
     RECT  2.304 11.677 40.734 11.939 ;
     RECT  2.304 11.939 40.59 12.119 ;
     RECT  2.304 12.119 40.497 14.485 ;
     RECT  2.268 14.485 40.497 14.755 ;
     RECT  0.216 14.647 0.234 15.053 ;
     RECT  2.268 14.755 40.59 15.197 ;
     RECT  2.304 15.197 40.59 15.485 ;
     RECT  2.304 15.485 40.497 18.499 ;
     RECT  2.304 18.499 40.662 18.841 ;
     RECT  2.304 18.841 40.698 19.543 ;
     RECT  2.304 19.543 40.77 19.769 ;
     RECT  2.34 19.769 40.77 20.039 ;
     RECT  2.34 20.039 40.698 20.075 ;
     RECT  2.34 20.075 40.662 21.001 ;
     RECT  2.34 21.001 40.914 21.263 ;
     RECT  2.34 21.263 40.497 22.009 ;
     RECT  2.34 22.009 40.518 22.045 ;
     RECT  2.34 22.045 40.698 22.235 ;
     RECT  2.34 22.235 40.59 22.441 ;
     RECT  2.304 22.441 40.59 23.161 ;
     RECT  2.304 23.161 40.698 23.315 ;
     RECT  2.304 23.315 40.497 25.591 ;
     RECT  2.304 25.591 40.734 25.745 ;
     RECT  2.304 25.745 40.698 26.671 ;
     RECT  2.304 26.671 40.77 26.933 ;
     RECT  2.304 26.933 40.497 29.101 ;
     RECT  2.304 29.101 40.698 29.227 ;
     RECT  2.304 29.227 40.842 29.489 ;
     RECT  2.304 29.489 40.698 29.525 ;
     RECT  2.304 29.525 40.497 31.729 ;
     RECT  2.304 31.729 40.626 31.919 ;
     RECT  2.304 31.919 40.497 31.991 ;
     RECT  2.34 31.991 40.497 32.845 ;
     RECT  2.34 32.845 40.59 33.305 ;
     RECT  2.34 33.305 40.497 33.781 ;
     RECT  2.268 33.781 40.497 34.187 ;
     RECT  2.34 34.187 40.497 35.005 ;
     RECT  2.34 35.005 40.914 35.429 ;
     RECT  2.34 35.429 40.878 36.481 ;
     RECT  2.304 36.481 40.878 37.391 ;
     RECT  2.304 37.391 40.842 38.435 ;
     RECT  2.304 38.435 40.698 39.289 ;
     RECT  2.304 39.289 40.77 39.479 ;
     RECT  2.304 39.479 40.698 39.785 ;
     RECT  2.304 39.785 40.662 39.857 ;
     RECT  2.304 39.857 40.626 39.929 ;
     RECT  2.415 39.929 40.626 40.703 ;
     RECT  2.415 40.703 40.497 41.521 ;
     RECT  2.415 41.521 40.914 43.097 ;
     RECT  2.415 43.097 40.497 43.105 ;
     RECT  2.376 43.105 40.497 43.799 ;
     RECT  2.415 43.799 40.497 44.185 ;
     RECT  2.415 44.185 40.662 44.339 ;
     RECT  2.415 44.339 40.554 44.375 ;
     RECT  2.415 44.375 40.497 45.571 ;
     RECT  2.415 45.571 40.59 46.003 ;
     RECT  2.415 46.003 40.734 46.229 ;
     RECT  2.415 46.229 40.662 47.155 ;
     RECT  2.415 47.155 40.914 48.541 ;
     RECT  2.376 48.541 40.914 48.929 ;
     RECT  2.376 48.929 40.554 49.783 ;
     RECT  2.376 49.783 40.59 49.855 ;
     RECT  2.376 49.855 40.914 50.351 ;
     RECT  2.376 50.351 40.497 50.729 ;
     RECT  2.415 50.729 40.497 52.321 ;
     RECT  2.376 52.321 40.914 52.853 ;
     RECT  2.376 52.853 40.497 52.979 ;
     RECT  2.415 52.979 40.497 53.969 ;
     RECT  33.084 53.969 40.497 54.067 ;
     RECT  2.415 53.969 32.346 54.301 ;
     RECT  2.34 54.301 32.346 54.869 ;
     RECT  28.512 54.869 32.346 54.877 ;
     RECT  33.084 54.067 40.914 54.877 ;
     RECT  28.512 54.877 40.914 55.211 ;
     RECT  2.34 54.869 27.738 55.759 ;
     RECT  28.512 55.211 40.554 55.759 ;
     RECT  2.34 55.759 40.554 55.985 ;
     RECT  2.376 55.985 40.554 56.371 ;
     RECT  2.376 56.371 40.914 56.597 ;
     RECT  2.376 56.597 40.554 57.037 ;
     RECT  2.34 57.037 40.554 57.415 ;
     RECT  2.34 57.415 40.842 57.569 ;
     RECT  2.34 57.569 33.894 58.109 ;
     RECT  34.668 57.569 40.842 58.955 ;
     RECT  2.34 58.109 26.226 58.999 ;
     RECT  34.668 58.955 40.77 58.999 ;
     RECT  2.34 58.999 26.334 59.189 ;
     RECT  2.34 59.189 26.19 59.261 ;
     RECT  2.34 59.261 24.39 59.275 ;
     RECT  27.36 58.109 33.894 59.341 ;
     RECT  2.304 59.275 24.39 59.459 ;
     RECT  27.252 59.341 33.894 59.503 ;
     RECT  34.632 58.999 40.77 59.503 ;
     RECT  17.568 59.459 24.39 59.741 ;
     RECT  2.304 59.459 16.686 59.765 ;
     RECT  2.34 59.765 16.686 59.837 ;
     RECT  27.252 59.503 40.77 59.845 ;
     RECT  27.072 59.845 40.77 59.999 ;
     RECT  25.2 59.261 26.19 60.035 ;
     RECT  27.072 59.999 40.698 60.035 ;
     RECT  23.112 59.741 24.39 60.115 ;
     RECT  27.072 60.035 40.497 60.151 ;
     RECT  25.308 60.035 26.19 60.305 ;
     RECT  26.964 60.151 40.497 60.539 ;
     RECT  2.34 59.837 16.65 60.571 ;
     RECT  26.964 60.539 37.386 60.575 ;
     RECT  17.568 59.741 22.338 60.583 ;
     RECT  23.112 60.115 24.57 60.583 ;
     RECT  25.344 60.305 26.19 60.691 ;
     RECT  26.964 60.575 37.314 60.691 ;
     RECT  17.568 60.583 24.57 60.781 ;
     RECT  2.304 60.571 16.65 60.845 ;
     RECT  38.16 60.539 40.497 60.961 ;
     RECT  17.532 60.781 24.57 61.231 ;
     RECT  25.344 60.691 37.314 61.231 ;
     RECT  2.34 60.845 16.65 61.321 ;
     RECT  17.532 61.231 37.314 61.321 ;
     RECT  38.16 60.961 40.554 61.321 ;
     RECT  2.34 61.321 40.59 61.349 ;
     RECT  15.948 61.349 19.242 61.385 ;
     RECT  19.98 61.349 40.59 61.493 ;
     RECT  23.688 61.493 40.59 61.501 ;
     RECT  19.98 61.493 22.95 61.997 ;
     RECT  19.98 61.997 22.014 62.033 ;
     RECT  22.752 61.997 22.95 62.033 ;
     RECT  2.34 61.349 15.174 62.155 ;
     RECT  15.984 61.385 19.242 62.159 ;
     RECT  23.688 61.501 40.626 62.159 ;
     RECT  15.984 62.159 19.17 62.195 ;
     RECT  23.688 62.159 40.554 62.195 ;
     RECT  22.824 62.033 22.95 62.609 ;
     RECT  2.304 62.155 15.174 62.669 ;
     RECT  2.34 62.669 15.174 62.699 ;
     RECT  16.164 62.195 19.17 62.941 ;
     RECT  19.98 62.033 21.978 62.941 ;
     RECT  15.84 62.941 21.978 62.969 ;
     RECT  22.896 62.609 22.95 63.085 ;
     RECT  23.688 62.195 40.497 63.085 ;
     RECT  21.708 62.969 21.978 63.239 ;
     RECT  15.84 62.969 20.862 63.383 ;
     RECT  22.896 63.085 40.497 63.391 ;
     RECT  2.34 62.699 14.958 63.661 ;
     RECT  2.34 63.661 14.994 63.823 ;
     RECT  2.304 63.823 14.994 63.931 ;
     RECT  15.84 63.383 16.434 63.931 ;
     RECT  17.172 63.383 20.862 64.049 ;
     RECT  22.536 63.391 40.497 64.093 ;
     RECT  2.304 63.931 16.434 64.129 ;
     RECT  17.172 64.049 20.754 64.129 ;
     RECT  22.14 64.093 40.497 64.201 ;
     RECT  2.304 64.129 20.754 64.319 ;
     RECT  2.304 64.319 20.682 64.445 ;
     RECT  21.924 64.201 40.554 64.471 ;
     RECT  21.672 64.471 40.554 64.625 ;
     RECT  2.304 64.445 20.034 64.661 ;
     RECT  17.244 64.661 20.034 64.733 ;
     RECT  17.28 64.733 20.034 65.003 ;
     RECT  21.852 64.625 40.554 65.371 ;
     RECT  17.28 65.003 19.71 65.515 ;
     RECT  21.78 65.371 40.554 65.515 ;
     RECT  2.304 64.661 16.362 65.713 ;
     RECT  17.1 65.515 19.71 65.713 ;
     RECT  20.628 65.281 20.646 65.749 ;
     RECT  21.528 65.515 40.554 65.749 ;
     RECT  20.628 65.749 40.554 65.821 ;
     RECT  2.304 65.713 19.71 66.361 ;
     RECT  20.628 65.821 40.806 66.361 ;
     RECT  2.304 66.361 40.806 66.929 ;
     RECT  2.304 66.929 40.626 67.865 ;
     RECT  2.34 67.865 40.626 67.937 ;
     RECT  2.34 67.937 19.998 68.099 ;
     RECT  20.736 67.937 40.554 68.783 ;
     RECT  20.736 68.783 40.497 68.813 ;
     RECT  2.34 68.099 19.962 69.331 ;
     RECT  20.736 68.813 22.05 69.331 ;
     RECT  22.824 68.813 40.497 69.341 ;
     RECT  25.128 69.341 40.497 69.533 ;
     RECT  2.34 69.331 22.05 69.755 ;
     RECT  2.34 69.755 17.118 70.123 ;
     RECT  2.304 70.123 17.118 70.259 ;
     RECT  25.128 69.533 27.09 70.303 ;
     RECT  27.864 69.533 40.497 70.303 ;
     RECT  25.128 70.303 40.497 70.318 ;
     RECT  22.824 69.341 24.297 70.411 ;
     RECT  25.128 70.318 37.926 70.411 ;
     RECT  22.824 70.411 37.926 70.529 ;
     RECT  17.928 69.755 22.05 70.555 ;
     RECT  22.824 70.529 35.406 70.555 ;
     RECT  17.928 70.555 35.406 70.643 ;
     RECT  2.34 70.259 17.118 70.645 ;
     RECT  17.928 70.643 28.278 70.645 ;
     RECT  29.016 70.643 35.406 70.685 ;
     RECT  36.36 70.529 37.926 71.041 ;
     RECT  38.7 70.318 40.497 71.041 ;
     RECT  29.016 70.685 35.262 71.419 ;
     RECT  29.016 71.419 35.514 71.455 ;
     RECT  36.36 71.041 40.497 71.455 ;
     RECT  2.34 70.645 28.278 71.644 ;
     RECT  29.016 71.455 40.497 71.644 ;
     RECT  2.34 71.644 40.497 71.789 ;
     RECT  2.376 71.789 40.497 72.149 ;
     RECT  2.376 72.149 25.362 72.464 ;
     RECT  2.376 72.464 22.086 72.931 ;
     RECT  22.896 72.464 25.362 73.003 ;
     RECT  26.172 72.149 40.497 73.003 ;
     RECT  2.34 72.931 22.086 73.195 ;
     RECT  2.34 73.195 22.122 73.309 ;
     RECT  22.896 73.003 40.497 73.309 ;
     RECT  2.34 73.309 40.497 73.769 ;
     RECT  2.376 73.769 40.497 73.841 ;
     RECT  2.376 73.841 30.582 73.913 ;
     RECT  2.376 73.913 27.162 74.039 ;
     RECT  2.376 74.039 24.498 74.579 ;
     RECT  25.308 74.039 27.162 74.659 ;
     RECT  28.044 73.913 30.582 74.695 ;
     RECT  31.356 73.841 40.497 74.695 ;
     RECT  28.044 74.695 40.497 74.731 ;
     RECT  16.38 74.579 24.498 74.821 ;
     RECT  25.308 74.659 27.198 74.821 ;
     RECT  28.008 74.731 40.497 74.821 ;
     RECT  16.38 74.821 27.198 74.857 ;
     RECT  27.936 74.821 40.497 74.857 ;
     RECT  16.38 74.857 40.497 75.119 ;
     RECT  2.376 74.579 15.462 75.155 ;
     RECT  20.988 75.119 40.497 75.191 ;
     RECT  2.415 75.155 15.462 75.469 ;
     RECT  16.38 75.119 20.178 75.469 ;
     RECT  21.024 75.191 40.497 75.659 ;
     RECT  21.024 75.659 24.57 75.731 ;
     RECT  2.415 75.469 20.178 76.045 ;
     RECT  2.376 76.045 20.178 76.081 ;
     RECT  2.376 76.081 20.25 76.199 ;
     RECT  25.524 75.659 40.497 76.379 ;
     RECT  21.06 75.731 24.57 76.621 ;
     RECT  21.024 76.621 24.57 76.747 ;
     RECT  25.524 76.379 31.95 76.747 ;
     RECT  2.376 76.199 20.214 77.017 ;
     RECT  21.024 76.747 31.95 77.017 ;
     RECT  2.376 77.017 31.95 77.161 ;
     RECT  2.34 77.161 31.95 77.287 ;
     RECT  32.724 76.379 40.497 77.287 ;
     RECT  2.34 77.287 40.497 77.549 ;
     RECT  38.052 77.549 40.497 77.621 ;
     RECT  38.124 77.621 40.497 77.657 ;
     RECT  38.124 77.657 39.186 77.729 ;
     RECT  38.196 77.729 39.186 77.855 ;
     RECT  38.196 77.855 38.214 77.891 ;
     RECT  39.168 77.855 39.186 78.089 ;
     RECT  2.34 77.549 37.062 78.629 ;
     RECT  2.376 78.629 37.062 78.665 ;
     RECT  2.376 78.665 36.486 78.989 ;
     RECT  28.332 78.989 36.486 79.079 ;
     RECT  2.376 78.989 27.558 79.169 ;
     RECT  2.376 79.169 27.486 79.205 ;
     RECT  28.368 79.079 36.09 79.205 ;
     RECT  28.368 79.205 36.018 79.241 ;
     RECT  2.376 79.205 26.226 79.313 ;
     RECT  22.752 79.313 26.226 79.349 ;
     RECT  2.376 79.313 21.798 79.439 ;
     RECT  22.752 79.349 26.19 79.439 ;
     RECT  27.072 79.205 27.378 79.439 ;
     RECT  28.548 79.241 31.59 79.439 ;
     RECT  32.364 79.241 36.018 79.439 ;
     RECT  27.144 79.439 27.27 79.475 ;
     RECT  32.832 79.439 36.018 79.475 ;
     RECT  2.376 79.439 19.602 79.511 ;
     RECT  20.376 79.439 21.798 79.511 ;
     RECT  33.048 79.475 36.018 79.511 ;
     RECT  33.048 79.511 33.57 79.547 ;
     RECT  34.596 79.511 36.018 79.547 ;
     RECT  22.824 79.439 24.297 79.583 ;
     RECT  28.548 79.439 31.05 79.583 ;
     RECT  20.376 79.511 21.51 79.592 ;
     RECT  22.824 79.583 22.878 79.619 ;
     RECT  25.128 79.439 25.866 79.619 ;
     RECT  27.144 79.475 27.162 79.619 ;
     RECT  2.376 79.511 18.897 79.667 ;
     RECT  23.652 79.583 24.297 79.667 ;
     RECT  28.692 79.583 31.05 79.667 ;
     RECT  40.215 77.657 40.497 79.667 ;
     RECT  2.376 79.667 2.538 79.709 ;
     RECT  3.312 79.667 18.705 79.709 ;
     RECT  20.412 79.592 21.51 79.709 ;
     RECT  22.86 79.619 22.878 79.709 ;
     RECT  25.848 79.619 25.866 79.709 ;
     RECT  28.692 79.667 29.505 79.709 ;
     RECT  30.276 79.667 31.05 79.709 ;
     RECT  33.552 79.547 33.57 79.709 ;
     RECT  5.076 79.709 14.49 79.745 ;
     RECT  15.444 79.709 16.146 79.745 ;
     RECT  17.1 79.709 18.705 79.745 ;
     RECT  20.808 79.709 21.15 79.745 ;
     RECT  31.032 79.709 31.05 79.745 ;
     RECT  34.596 79.547 35.442 79.745 ;
     RECT  5.292 79.745 6.138 79.757 ;
     RECT  6.912 79.745 13.305 79.757 ;
     RECT  3.708 79.709 4.122 79.781 ;
     RECT  5.292 79.757 5.418 79.781 ;
     RECT  6.912 79.757 6.93 79.781 ;
     RECT  14.292 79.745 14.31 79.781 ;
     RECT  16.128 79.745 16.146 79.781 ;
     RECT  17.568 79.745 18.705 79.781 ;
     RECT  21.024 79.745 21.15 79.781 ;
     RECT  23.652 79.667 24.105 79.781 ;
     RECT  30.276 79.709 30.294 79.781 ;
     RECT  34.596 79.745 34.905 79.781 ;
     RECT  5.4 79.781 5.418 79.853 ;
     RECT  4.104 79.781 4.122 79.889 ;
     RECT  17.568 79.781 17.586 79.889 ;
     RECT  2.415 79.709 2.505 79.937 ;
     RECT  7.815 79.757 13.305 79.937 ;
     RECT  18.615 79.781 18.705 79.937 ;
     RECT  24.015 79.781 24.105 79.937 ;
     RECT  29.415 79.709 29.505 79.937 ;
     RECT  34.815 79.781 34.905 79.937 ;
     RECT  40.215 79.667 40.305 79.937 ;
     RECT  8.46 79.937 13.086 80.909 ;
     RECT  9 80.909 13.086 80.933 ;
     RECT  9 80.933 12.978 81.671 ;
     RECT  12.24 81.671 12.978 81.677 ;
     RECT  12.672 81.677 12.978 81.725 ;
     RECT  12.96 81.725 12.978 81.743 ;
     RECT  9 81.671 11.466 81.948 ;
    LAYER M4 ;
     RECT  0.156 14.88 0.275 15.192 ;
     RECT  2.252 62.64 2.293 62.664 ;
     RECT  2.285 66.72 2.293 66.744 ;
     RECT  2.365 5.184 2.408 5.208 ;
     RECT  2.365 7.344 2.408 7.368 ;
     RECT  2.365 9.072 2.408 9.096 ;
     RECT  2.365 12.528 2.408 12.552 ;
     RECT  0.275 15.168 2.408 15.192 ;
     RECT  2.365 16.272 2.408 16.296 ;
     RECT  2.365 17.664 2.408 17.688 ;
     RECT  2.365 20.4 2.408 20.424 ;
     RECT  2.365 21.504 2.408 21.528 ;
     RECT  2.329 23.616 2.408 23.64 ;
     RECT  2.365 29.232 2.408 29.256 ;
     RECT  2.329 34.08 2.408 34.104 ;
     RECT  2.365 37.584 2.408 37.608 ;
     RECT  2.329 39.312 2.408 39.336 ;
     RECT  0.229 41.184 2.408 41.208 ;
     RECT  2.365 49.536 2.408 49.56 ;
     RECT  2.293 50.64 2.408 50.664 ;
     RECT  2.365 55.152 2.408 55.176 ;
     RECT  2.365 56.352 2.408 56.376 ;
     RECT  2.329 58.176 2.408 58.2 ;
     RECT  2.293 59.28 2.408 59.496 ;
     RECT  2.293 60.576 2.408 60.6 ;
     RECT  2.293 62.16 2.408 62.664 ;
     RECT  2.401 64.08 2.408 64.104 ;
     RECT  2.293 66.72 2.408 66.84 ;
     RECT  2.252 70.128 2.408 70.152 ;
     RECT  2.365 74.688 2.408 74.712 ;
     RECT  2.293 78.528 2.408 79.32 ;
     RECT  2.408 2.148 2.512 79.932 ;
     RECT  2.512 2.418 2.704 79.662 ;
     RECT  2.704 5.184 2.819 7.368 ;
     RECT  2.704 9.072 2.819 11.304 ;
     RECT  2.704 16.272 2.819 16.392 ;
     RECT  2.704 32.496 2.819 32.952 ;
     RECT  2.704 50.592 2.837 71.256 ;
     RECT  2.704 3.936 2.845 3.96 ;
     RECT  2.704 12.528 2.867 13.08 ;
     RECT  2.704 37.584 2.867 39.864 ;
     RECT  2.704 72.864 2.867 79.512 ;
     RECT  2.819 9.072 2.873 10.584 ;
     RECT  2.704 19.344 2.873 25.176 ;
     RECT  2.704 26.592 2.915 30.456 ;
     RECT  2.873 9.12 2.917 10.584 ;
     RECT  2.873 20.4 2.963 25.176 ;
     RECT  2.819 5.712 2.981 7.368 ;
     RECT  2.704 35.232 3.017 35.352 ;
     RECT  2.704 17.664 3.197 17.688 ;
     RECT  2.867 37.584 3.233 38.76 ;
     RECT  2.837 50.64 3.251 71.256 ;
     RECT  3.251 50.64 3.341 52.92 ;
     RECT  2.867 72.912 3.347 79.512 ;
     RECT  2.915 26.592 3.377 28.536 ;
     RECT  2.704 48.816 3.377 49.56 ;
     RECT  3.251 53.904 3.377 71.256 ;
     RECT  3.377 68.448 3.385 71.256 ;
     RECT  2.915 29.712 3.413 30.456 ;
     RECT  3.377 53.904 3.413 67.416 ;
     RECT  2.867 12.528 3.521 12.552 ;
     RECT  2.704 14.352 3.521 14.808 ;
     RECT  2.963 20.544 3.521 25.176 ;
     RECT  3.521 20.688 3.593 25.176 ;
     RECT  3.341 50.928 3.665 52.92 ;
     RECT  2.981 6.288 3.697 7.368 ;
     RECT  2.704 34.08 3.769 34.104 ;
     RECT  2.704 44.448 3.769 44.808 ;
     RECT  3.593 20.688 3.773 23.64 ;
     RECT  2.867 39.84 3.829 39.864 ;
     RECT  2.704 40.848 3.829 42.792 ;
     RECT  3.347 72.912 3.829 73.512 ;
     RECT  3.233 37.584 3.877 38.712 ;
     RECT  2.704 46.224 3.913 47.304 ;
     RECT  3.377 48.816 3.913 49.032 ;
     RECT  3.829 39.84 3.917 42.792 ;
     RECT  3.697 6.288 3.925 7.416 ;
     RECT  3.385 70.512 3.925 71.256 ;
     RECT  3.829 72.336 3.925 73.512 ;
     RECT  3.925 6.288 3.971 7.944 ;
     RECT  2.917 9.12 3.971 9.144 ;
     RECT  2.704 36.432 3.989 36.504 ;
     RECT  3.593 25.152 4.025 25.176 ;
     RECT  3.925 70.512 4.025 73.512 ;
     RECT  3.413 29.712 4.061 30.264 ;
     RECT  3.347 74.496 4.069 79.512 ;
     RECT  2.917 10.56 4.093 10.584 ;
     RECT  3.971 6.288 4.097 6.888 ;
     RECT  3.769 34.08 4.165 34.2 ;
     RECT  3.769 44.448 4.165 45.144 ;
     RECT  3.377 28.512 4.201 28.536 ;
     RECT  4.061 29.712 4.201 29.832 ;
     RECT  3.971 7.92 4.205 7.944 ;
     RECT  4.093 9.648 4.277 10.584 ;
     RECT  3.877 37.536 4.309 38.712 ;
     RECT  3.917 39.84 4.309 41.208 ;
     RECT  2.873 19.344 4.381 19.368 ;
     RECT  2.819 32.496 4.417 32.568 ;
     RECT  4.069 74.496 4.457 79.608 ;
     RECT  4.381 19.2 4.489 19.368 ;
     RECT  4.165 33.792 4.493 34.2 ;
     RECT  4.457 74.496 4.501 75.816 ;
     RECT  3.773 22.08 4.529 23.64 ;
     RECT  3.385 68.448 4.549 69.48 ;
     RECT  4.025 70.512 4.549 72.984 ;
     RECT  4.489 18.432 4.561 19.368 ;
     RECT  4.277 10.272 4.565 10.584 ;
     RECT  2.819 16.272 4.604 16.296 ;
     RECT  4.561 18.432 4.633 19.416 ;
     RECT  4.549 68.448 4.633 72.984 ;
     RECT  4.633 18.432 4.645 19.56 ;
     RECT  3.413 53.904 4.645 67.272 ;
     RECT  4.604 16.272 4.669 17.064 ;
     RECT  4.669 15.984 4.691 17.064 ;
     RECT  3.017 35.328 4.709 35.352 ;
     RECT  3.917 42.384 4.741 42.792 ;
     RECT  4.493 33.792 4.777 33.816 ;
     RECT  4.741 42.384 4.777 43.224 ;
     RECT  4.165 44.304 4.777 45.144 ;
     RECT  4.645 18.096 4.781 19.56 ;
     RECT  3.377 26.592 4.789 27.432 ;
     RECT  4.201 28.512 4.789 29.832 ;
     RECT  4.417 32.256 4.789 32.568 ;
     RECT  3.913 46.224 4.844 49.032 ;
     RECT  4.837 50.112 4.844 50.136 ;
     RECT  4.781 18.432 4.849 19.56 ;
     RECT  3.773 20.688 4.849 20.712 ;
     RECT  4.789 32.064 4.849 32.568 ;
     RECT  4.777 33.648 4.849 33.816 ;
     RECT  4.849 32.064 4.861 33.816 ;
     RECT  4.021 11.904 4.929 12.216 ;
     RECT  3.521 14.352 4.931 14.376 ;
     RECT  4.844 46.224 4.931 50.136 ;
     RECT  3.665 51.84 4.931 52.92 ;
     RECT  4.633 68.352 4.988 72.984 ;
     RECT  4.501 74.016 4.988 75.816 ;
     RECT  4.645 53.904 5.029 67.32 ;
     RECT  4.988 68.352 5.029 75.816 ;
     RECT  5.029 53.904 5.033 75.816 ;
     RECT  4.097 6.288 5.101 6.792 ;
     RECT  5.033 54.048 5.123 75.816 ;
     RECT  4.861 32.064 5.125 32.712 ;
     RECT  4.457 76.848 5.125 79.608 ;
     RECT  4.931 46.224 5.177 48.888 ;
     RECT  3.989 36.48 5.209 36.504 ;
     RECT  3.697 2.784 5.221 2.808 ;
     RECT  5.18 3.84 5.221 3.864 ;
     RECT  4.861 33.792 5.249 33.816 ;
     RECT  5.221 3.84 5.267 4.104 ;
     RECT  3.985 13.296 5.285 13.32 ;
     RECT  4.789 26.592 5.317 29.832 ;
     RECT  4.777 42.384 5.317 45.144 ;
     RECT  4.931 50.112 5.353 50.136 ;
     RECT  4.525 5.136 5.461 5.16 ;
     RECT  5.101 6.288 5.461 7.368 ;
     RECT  5.123 67.776 5.509 75.816 ;
     RECT  5.125 76.848 5.509 79.752 ;
     RECT  5.123 54.048 5.555 66.744 ;
     RECT  5.209 35.568 5.641 36.504 ;
     RECT  4.309 37.536 5.641 41.208 ;
     RECT  5.125 31.872 5.645 32.712 ;
     RECT  4.691 15.984 5.677 16.296 ;
     RECT  5.641 35.568 5.677 41.208 ;
     RECT  5.317 42.384 5.677 45.24 ;
     RECT  5.177 46.224 5.677 47.64 ;
     RECT  4.529 22.128 5.753 23.64 ;
     RECT  5.555 54.048 5.753 58.824 ;
     RECT  5.753 22.32 5.821 23.64 ;
     RECT  4.849 18.432 5.845 20.712 ;
     RECT  5.221 2.304 5.852 2.808 ;
     RECT  4.565 10.272 5.857 10.296 ;
     RECT  4.929 11.376 5.857 12.216 ;
     RECT  5.821 22.32 5.857 24.36 ;
     RECT  5.677 15.84 5.929 16.296 ;
     RECT  5.555 59.808 5.933 66.744 ;
     RECT  5.267 4.08 5.996 4.104 ;
     RECT  5.461 5.136 5.996 7.368 ;
     RECT  5.677 35.472 6.037 41.208 ;
     RECT  5.677 42.384 6.037 47.64 ;
     RECT  5.965 8.976 6.073 9 ;
     RECT  5.857 10.272 6.073 12.216 ;
     RECT  5.645 32.064 6.073 32.712 ;
     RECT  4.931 51.84 6.073 52.44 ;
     RECT  6.037 35.472 6.077 47.64 ;
     RECT  5.996 4.08 6.083 7.368 ;
     RECT  5.509 67.776 6.085 79.752 ;
     RECT  6.077 35.472 6.113 46.632 ;
     RECT  5.317 25.68 6.145 29.832 ;
     RECT  5.929 15.168 6.181 16.296 ;
     RECT  5.353 50.112 6.181 50.76 ;
     RECT  6.073 51.84 6.181 53.016 ;
     RECT  5.753 54.048 6.181 56.472 ;
     RECT  5.933 61.104 6.181 66.744 ;
     RECT  6.085 67.728 6.181 79.752 ;
     RECT  6.181 15.168 6.217 16.824 ;
     RECT  6.181 50.112 6.221 56.472 ;
     RECT  5.753 57.6 6.221 58.824 ;
     RECT  6.145 25.68 6.245 30.216 ;
     RECT  6.221 52.992 6.268 56.472 ;
     RECT  5.857 22.32 6.277 24.504 ;
     RECT  6.245 25.68 6.277 30.84 ;
     RECT  5.852 2.304 6.289 2.856 ;
     RECT  6.083 4.08 6.289 4.104 ;
     RECT  6.113 35.472 6.289 39.912 ;
     RECT  6.277 22.32 6.323 30.84 ;
     RECT  6.323 30.816 6.329 30.84 ;
     RECT  6.181 61.104 6.364 79.752 ;
     RECT  6.073 8.976 6.365 12.216 ;
     RECT  6.323 28.992 6.365 29.832 ;
     RECT  5.177 48.816 6.365 48.888 ;
     RECT  6.268 54.048 6.373 56.472 ;
     RECT  6.365 10.272 6.433 12.216 ;
     RECT  5.845 18.432 6.433 20.856 ;
     RECT  6.323 22.32 6.509 27.912 ;
     RECT  6.077 47.616 6.509 47.64 ;
     RECT  6.083 5.232 6.541 7.368 ;
     RECT  6.509 25.488 6.545 27.912 ;
     RECT  6.433 10.272 6.577 12.312 ;
     RECT  6.365 28.992 6.581 29.736 ;
     RECT  6.433 18.432 6.617 21.048 ;
     RECT  6.373 54.048 6.617 55.848 ;
     RECT  6.073 32.064 6.649 33 ;
     RECT  6.289 34.752 6.649 39.912 ;
     RECT  5.933 59.808 6.649 59.88 ;
     RECT  6.289 2.304 6.689 4.104 ;
     RECT  6.221 50.112 6.761 51.864 ;
     RECT  6.221 57.6 6.821 57.864 ;
     RECT  6.509 22.32 6.833 24.36 ;
     RECT  6.649 32.064 6.973 39.912 ;
     RECT  6.365 8.976 7.004 9 ;
     RECT  6.364 61.104 7.004 64.584 ;
     RECT  6.365 48.864 7.045 48.888 ;
     RECT  6.761 50.112 7.045 51.384 ;
     RECT  6.973 31.728 7.117 39.912 ;
     RECT  6.113 41.04 7.117 46.632 ;
     RECT  6.541 5.232 7.153 7.56 ;
     RECT  6.577 10.272 7.225 12.648 ;
     RECT  6.517 13.632 7.225 13.656 ;
     RECT  6.833 22.32 7.225 24.168 ;
     RECT  7.117 31.728 7.237 46.632 ;
     RECT  7.004 8.688 7.333 9 ;
     RECT  7.225 10.272 7.333 13.656 ;
     RECT  6.689 2.304 7.369 3.144 ;
     RECT  7.004 61.008 7.369 64.584 ;
     RECT  6.364 65.568 7.369 79.752 ;
     RECT  7.237 31.728 7.388 47.352 ;
     RECT  6.217 15.168 7.436 17.064 ;
     RECT  6.268 52.992 7.477 53.016 ;
     RECT  7.153 5.04 7.621 7.56 ;
     RECT  7.333 8.688 7.621 13.656 ;
     RECT  6.617 18.432 7.621 20.952 ;
     RECT  7.225 22.032 7.621 24.168 ;
     RECT  6.617 54.192 7.693 55.848 ;
     RECT  6.821 57.024 7.693 57.864 ;
     RECT  7.369 2.256 7.808 3.144 ;
     RECT  7.621 5.04 7.808 13.656 ;
     RECT  7.436 14.784 7.808 17.064 ;
     RECT  7.621 18.432 7.808 24.168 ;
     RECT  6.545 25.488 7.808 27.816 ;
     RECT  6.581 28.992 7.808 29.64 ;
     RECT  7.388 31.008 7.808 47.352 ;
     RECT  7.045 48.864 7.808 51.384 ;
     RECT  7.477 52.416 7.808 53.016 ;
     RECT  7.693 54.192 7.808 57.864 ;
     RECT  6.649 59.04 7.808 59.88 ;
     RECT  7.369 61.008 7.808 79.752 ;
     RECT  7.808 2.148 7.912 79.932 ;
     RECT  7.912 2.256 8.104 79.752 ;
     RECT  8.104 55.44 8.129 55.56 ;
     RECT  8.104 33.936 8.201 46.536 ;
     RECT  8.201 33.936 8.237 33.96 ;
     RECT  8.104 4.8 8.243 9.672 ;
     RECT  8.201 35.28 8.309 46.536 ;
     RECT  8.104 57.12 8.309 57.96 ;
     RECT  8.104 50.64 8.417 51.048 ;
     RECT  8.104 62.16 8.425 79.752 ;
     RECT  8.104 2.256 8.489 3.384 ;
     RECT  8.309 38.208 8.525 46.536 ;
     RECT  8.309 57.12 8.525 57.144 ;
     RECT  8.425 63.648 8.525 79.752 ;
     RECT  8.425 62.16 8.531 62.568 ;
     RECT  8.104 48.912 8.579 49.608 ;
     RECT  8.525 63.744 8.579 79.752 ;
     RECT  8.309 35.28 8.705 37.08 ;
     RECT  8.104 52.176 8.777 52.536 ;
     RECT  8.777 52.176 8.812 52.2 ;
     RECT  8.531 62.16 8.849 62.52 ;
     RECT  8.243 8.544 8.915 9.672 ;
     RECT  8.104 10.656 8.915 32.568 ;
     RECT  8.915 10.656 8.921 17.736 ;
     RECT  9.025 0.528 9.097 0.552 ;
     RECT  8.915 18.72 9.097 32.568 ;
     RECT  8.921 11.328 9.107 17.736 ;
     RECT  8.579 48.912 9.107 49.512 ;
     RECT  8.104 59.184 9.133 61.176 ;
     RECT  8.849 62.16 9.133 62.472 ;
     RECT  9.097 18.72 9.136 32.904 ;
     RECT  8.915 8.544 9.137 8.952 ;
     RECT  8.449 80.88 9.169 80.904 ;
     RECT  9.133 47.904 9.217 47.928 ;
     RECT  8.417 51.024 9.241 51.048 ;
     RECT  8.579 63.792 9.245 79.752 ;
     RECT  8.525 40.656 9.277 46.536 ;
     RECT  8.104 53.568 9.308 54.456 ;
     RECT  8.129 55.44 9.308 55.464 ;
     RECT  9.169 80.88 9.347 81.672 ;
     RECT  9.241 51.024 9.353 51.912 ;
     RECT  8.705 35.472 9.389 37.08 ;
     RECT  8.489 2.88 9.404 3.384 ;
     RECT  8.243 4.8 9.404 7.512 ;
     RECT  9.133 59.184 9.461 62.472 ;
     RECT  9.245 63.792 9.461 78.264 ;
     RECT  9.097 0.48 9.491 0.552 ;
     RECT  9.404 2.88 9.491 7.512 ;
     RECT  9.107 49.008 9.491 49.512 ;
     RECT  9.136 18.72 9.493 32.952 ;
     RECT  9.461 64.848 9.497 78.264 ;
     RECT  9.497 64.848 9.539 78.168 ;
     RECT  9.493 18.72 9.601 33.72 ;
     RECT  9.245 79.248 9.605 79.752 ;
     RECT  9.347 80.88 9.635 81.576 ;
     RECT  9.389 36.576 9.637 37.08 ;
     RECT  8.525 38.208 9.637 39.24 ;
     RECT  9.461 59.76 9.677 62.472 ;
     RECT  9.677 59.76 9.683 59.832 ;
     RECT  9.461 63.792 9.721 63.864 ;
     RECT  9.491 0.528 9.779 0.552 ;
     RECT  9.491 49.488 9.781 49.512 ;
     RECT  9.637 36.576 9.817 39.24 ;
     RECT  9.277 40.656 9.817 47.496 ;
     RECT  9.781 49.488 9.923 49.608 ;
     RECT  9.137 8.592 9.925 8.952 ;
     RECT  9.133 9.936 9.925 9.96 ;
     RECT  9.605 79.296 10.021 79.752 ;
     RECT  9.635 80.88 10.021 81.528 ;
     RECT  10.021 79.296 10.037 81.528 ;
     RECT  9.925 8.592 10.069 10.056 ;
     RECT  9.107 11.328 10.069 17.688 ;
     RECT  9.677 60.96 10.073 62.472 ;
     RECT  9.601 18.72 10.105 34.2 ;
     RECT  9.683 59.808 10.181 59.832 ;
     RECT  9.353 51.024 10.211 51.864 ;
     RECT  10.037 79.728 10.253 81.528 ;
     RECT  10.069 8.592 10.285 17.688 ;
     RECT  10.105 18.72 10.285 34.44 ;
     RECT  10.073 61.872 10.325 62.472 ;
     RECT  9.817 36.576 10.355 47.496 ;
     RECT  10.211 51.024 10.361 51.336 ;
     RECT  10.253 80.88 10.361 81.528 ;
     RECT  10.285 8.592 10.393 34.44 ;
     RECT  9.389 35.472 10.393 35.496 ;
     RECT  10.355 40.992 10.393 47.496 ;
     RECT  10.393 8.592 10.433 35.496 ;
     RECT  10.433 8.592 10.469 22.584 ;
     RECT  9.491 3.072 10.501 7.512 ;
     RECT  9.539 64.848 10.501 67.896 ;
     RECT  9.539 68.88 10.501 78.168 ;
     RECT  10.361 51.024 10.505 51.048 ;
     RECT  10.325 61.92 10.505 62.472 ;
     RECT  10.501 2.976 10.541 7.512 ;
     RECT  10.501 64.848 10.541 78.168 ;
     RECT  10.355 36.576 10.595 39.912 ;
     RECT  10.361 81.504 10.597 81.528 ;
     RECT  10.453 56.688 10.609 56.712 ;
     RECT  10.501 0.48 10.645 0.504 ;
     RECT  10.433 23.904 10.645 35.496 ;
     RECT  10.595 36.576 10.645 39.864 ;
     RECT  10.541 67.536 10.649 78.168 ;
     RECT  10.541 64.848 10.717 66.504 ;
     RECT  10.505 62.448 10.741 62.472 ;
     RECT  9.853 63.648 10.741 63.72 ;
     RECT  10.597 81.504 10.741 81.576 ;
     RECT  10.609 56.448 10.753 56.712 ;
     RECT  10.649 70.368 10.753 78.168 ;
     RECT  10.541 2.976 10.789 6.312 ;
     RECT  10.469 8.592 10.789 10.296 ;
     RECT  10.741 62.448 10.789 63.72 ;
     RECT  10.717 64.752 10.789 66.504 ;
     RECT  10.789 2.736 10.793 6.312 ;
     RECT  10.541 7.344 10.861 7.512 ;
     RECT  10.789 8.544 10.861 10.296 ;
     RECT  10.741 81.504 10.885 81.624 ;
     RECT  10.789 62.448 10.901 66.504 ;
     RECT  10.645 0.288 10.933 0.504 ;
     RECT  9.923 49.488 10.933 49.512 ;
     RECT  10.645 50.976 10.933 51 ;
     RECT  10.649 67.536 10.937 69 ;
     RECT  10.393 40.992 10.973 48.456 ;
     RECT  10.933 49.488 10.979 51 ;
     RECT  10.933 0.144 11.027 0.552 ;
     RECT  10.885 81.504 11.029 81.672 ;
     RECT  11.027 0.144 11.045 0.504 ;
     RECT  10.901 62.448 11.045 65.016 ;
     RECT  10.937 67.728 11.045 69 ;
     RECT  11.045 63.648 11.075 65.016 ;
     RECT  9.308 53.568 11.081 55.464 ;
     RECT  11.075 63.648 11.081 64.392 ;
     RECT  10.469 11.328 11.164 22.584 ;
     RECT  11.045 68.976 11.189 69 ;
     RECT  10.861 7.344 11.219 10.296 ;
     RECT  11.164 11.328 11.225 18.216 ;
     RECT  10.753 70.368 11.317 78.6 ;
     RECT  11.081 54.24 11.324 55.464 ;
     RECT  10.753 56.448 11.324 56.76 ;
     RECT  11.317 70.368 11.333 78.744 ;
     RECT  11.173 53.088 11.365 53.112 ;
     RECT  11.324 54.24 11.365 56.76 ;
     RECT  11.365 61.008 11.401 61.032 ;
     RECT  11.365 54.24 11.405 57.288 ;
     RECT  11.405 54.528 11.411 57.288 ;
     RECT  11.365 52.704 11.441 53.112 ;
     RECT  11.441 52.704 11.452 52.728 ;
     RECT  10.793 2.736 11.459 6.12 ;
     RECT  11.045 67.728 11.477 67.896 ;
     RECT  10.901 66.288 11.509 66.504 ;
     RECT  11.219 9.648 11.513 10.296 ;
     RECT  10.253 79.728 11.513 79.848 ;
     RECT  10.645 23.904 11.545 39.864 ;
     RECT  11.029 81.504 11.549 81.72 ;
     RECT  11.225 11.328 11.581 17.496 ;
     RECT  11.219 7.344 11.585 8.616 ;
     RECT  11.477 67.872 11.657 67.896 ;
     RECT  11.333 70.368 11.689 71.256 ;
     RECT  11.401 60.336 11.701 61.032 ;
     RECT  11.411 56.736 11.725 57.288 ;
     RECT  9.637 58.512 11.725 58.584 ;
     RECT  11.701 60.192 11.725 61.032 ;
     RECT  11.509 66.288 11.729 66.744 ;
     RECT  11.513 9.648 11.765 10.056 ;
     RECT  10.979 49.584 11.765 51 ;
     RECT  11.045 62.448 11.797 62.472 ;
     RECT  11.459 4.464 11.833 6.12 ;
     RECT  11.585 7.344 11.833 8.568 ;
     RECT  11.411 54.72 11.843 55.464 ;
     RECT  11.797 62.16 11.881 62.472 ;
     RECT  11.765 49.584 11.891 50.184 ;
     RECT  11.725 56.736 11.905 58.584 ;
     RECT  11.725 59.856 11.905 61.032 ;
     RECT  11.843 54.816 11.939 55.464 ;
     RECT  11.333 72.24 11.941 78.744 ;
     RECT  11.513 79.728 11.941 79.752 ;
     RECT  11.861 1.728 11.945 1.752 ;
     RECT  11.459 2.736 12.013 3.24 ;
     RECT  11.765 9.648 12.017 9.672 ;
     RECT  10.973 40.992 12.017 47.688 ;
     RECT  11.941 72.24 12.017 79.752 ;
     RECT  11.045 0.192 12.037 0.504 ;
     RECT  11.164 19.44 12.085 22.584 ;
     RECT  11.545 23.712 12.085 39.864 ;
     RECT  12.085 19.44 12.125 39.864 ;
     RECT  11.891 50.16 12.161 50.184 ;
     RECT  11.905 56.736 12.179 61.032 ;
     RECT  12.125 25.488 12.193 39.864 ;
     RECT  12.017 40.992 12.193 41.496 ;
     RECT  12.017 42.528 12.197 47.688 ;
     RECT  11.549 81.648 12.269 81.72 ;
     RECT  12.265 51.6 12.445 51.624 ;
     RECT  12.013 1.968 12.625 3.24 ;
     RECT  11.833 4.464 12.625 8.568 ;
     RECT  11.729 66.288 12.689 66.696 ;
     RECT  11.689 69.072 12.697 71.256 ;
     RECT  12.017 72.24 12.697 79.224 ;
     RECT  12.269 81.696 12.701 81.72 ;
     RECT  11.581 11.184 12.733 17.496 ;
     RECT  11.939 54.816 12.805 54.84 ;
     RECT  12.445 51.6 12.877 52.488 ;
     RECT  11.081 64.368 12.949 64.392 ;
     RECT  12.689 65.76 12.949 66.696 ;
     RECT  12.877 50.304 12.985 52.488 ;
     RECT  11.881 62.4 12.985 62.472 ;
     RECT  12.625 1.968 12.997 8.568 ;
     RECT  12.733 10.992 12.997 17.496 ;
     RECT  12.037 0.192 13.021 0.84 ;
     RECT  12.997 10.992 13.057 18.264 ;
     RECT  12.125 19.44 13.057 24.504 ;
     RECT  12.997 1.968 13.093 9 ;
     RECT  12.193 25.488 13.093 41.496 ;
     RECT  12.197 42.528 13.093 47.448 ;
     RECT  12.985 62.4 13.093 63.24 ;
     RECT  13.093 1.968 13.208 9.096 ;
     RECT  13.057 10.992 13.208 24.504 ;
     RECT  13.093 25.488 13.208 47.448 ;
     RECT  12.301 48.432 13.208 48.504 ;
     RECT  12.985 50.304 13.208 52.536 ;
     RECT  12.445 53.52 13.208 53.544 ;
     RECT  12.805 54.72 13.208 54.84 ;
     RECT  12.179 57.024 13.208 61.032 ;
     RECT  13.093 62.016 13.208 63.24 ;
     RECT  12.949 64.368 13.208 66.696 ;
     RECT  12.445 67.824 13.208 67.848 ;
     RECT  12.697 69.072 13.208 79.224 ;
     RECT  13.208 1.968 13.312 79.932 ;
     RECT  13.312 1.968 13.504 79.662 ;
     RECT  13.504 1.968 13.529 4.488 ;
     RECT  13.504 5.76 13.619 7.368 ;
     RECT  13.504 66.432 13.619 67.848 ;
     RECT  13.504 71.424 13.667 79.272 ;
     RECT  13.504 70.368 13.673 70.392 ;
     RECT  13.504 55.68 13.708 55.704 ;
     RECT  13.667 71.472 13.745 79.272 ;
     RECT  13.619 67.536 13.997 67.848 ;
     RECT  13.745 72.144 14.105 79.272 ;
     RECT  14.105 72.144 14.213 73.272 ;
     RECT  13.504 8.544 14.285 28.296 ;
     RECT  13.504 57.024 14.285 60.6 ;
     RECT  14.105 74.352 14.321 79.272 ;
     RECT  13.504 33.84 14.393 54.696 ;
     RECT  13.504 64.752 14.435 64.776 ;
     RECT  14.321 74.352 14.465 78.12 ;
     RECT  14.285 8.544 14.497 21.096 ;
     RECT  14.393 33.84 14.509 54.168 ;
     RECT  14.285 22.08 14.569 28.296 ;
     RECT  13.504 29.616 14.569 32.856 ;
     RECT  14.509 33.84 14.569 53.016 ;
     RECT  14.569 22.08 14.573 53.016 ;
     RECT  14.573 22.08 14.645 39.96 ;
     RECT  13.619 66.432 14.713 66.552 ;
     RECT  13.997 67.536 14.713 67.56 ;
     RECT  14.321 79.248 14.717 79.272 ;
     RECT  14.497 7.872 14.789 21.096 ;
     RECT  14.573 40.992 14.789 43.416 ;
     RECT  14.285 58.032 14.789 60.6 ;
     RECT  13.619 5.76 14.821 6.888 ;
     RECT  14.713 55.392 14.825 55.416 ;
     RECT  13.504 62.016 14.825 62.76 ;
     RECT  14.789 7.872 14.861 11.208 ;
     RECT  14.789 12.192 14.861 21.096 ;
     RECT  13.529 2.064 14.893 4.488 ;
     RECT  14.821 5.52 14.893 6.888 ;
     RECT  14.713 66.432 14.893 67.56 ;
     RECT  14.573 44.448 14.897 53.016 ;
     RECT  14.465 76.032 14.933 78.12 ;
     RECT  14.897 44.448 15.005 52.536 ;
     RECT  14.861 7.872 15.077 9.336 ;
     RECT  14.825 62.016 15.185 62.04 ;
     RECT  14.789 59.952 15.203 60.6 ;
     RECT  15.203 60.048 15.217 60.6 ;
     RECT  14.789 58.032 15.229 58.68 ;
     RECT  15.077 7.872 15.293 9.048 ;
     RECT  14.465 74.352 15.301 74.424 ;
     RECT  14.893 2.064 15.325 6.888 ;
     RECT  15.293 7.872 15.325 8.664 ;
     RECT  14.213 72.144 15.397 72.936 ;
     RECT  15.301 74.064 15.397 74.424 ;
     RECT  15.397 72.144 15.401 74.424 ;
     RECT  15.005 44.448 15.437 52.44 ;
     RECT  15.401 72.576 15.437 74.424 ;
     RECT  15.325 2.064 15.473 8.664 ;
     RECT  14.933 76.416 15.545 78.12 ;
     RECT  14.509 54.144 15.685 54.168 ;
     RECT  15.397 55.2 15.685 55.224 ;
     RECT  14.893 66.384 15.685 67.56 ;
     RECT  15.685 54.096 15.731 55.224 ;
     RECT  14.861 12.288 15.757 21.096 ;
     RECT  14.645 22.08 15.757 39.864 ;
     RECT  14.789 41.184 15.757 43.416 ;
     RECT  15.437 44.448 15.757 49.56 ;
     RECT  15.437 50.688 15.761 52.44 ;
     RECT  15.731 54.096 15.769 54.696 ;
     RECT  13.504 68.976 15.788 69 ;
     RECT  14.285 57.024 15.793 57.048 ;
     RECT  15.229 58.032 15.793 58.056 ;
     RECT  15.437 72.576 15.797 74.376 ;
     RECT  15.788 68.928 15.829 69 ;
     RECT  15.829 68.928 15.875 69.24 ;
     RECT  15.761 50.736 15.973 52.44 ;
     RECT  15.757 12.288 16.013 39.864 ;
     RECT  14.861 10.368 16.045 11.208 ;
     RECT  16.013 12.288 16.049 19.896 ;
     RECT  15.217 60.048 16.049 61.032 ;
     RECT  16.045 10.368 16.117 11.256 ;
     RECT  16.049 12.288 16.117 12.312 ;
     RECT  16.013 21.168 16.117 39.864 ;
     RECT  15.757 41.184 16.117 49.56 ;
     RECT  16.049 13.92 16.157 19.896 ;
     RECT  15.685 66.288 16.157 67.56 ;
     RECT  16.117 21.168 16.193 49.56 ;
     RECT  15.545 77.28 16.261 78.12 ;
     RECT  16.157 66.48 16.301 67.56 ;
     RECT  16.117 10.368 16.357 12.312 ;
     RECT  15.473 2.064 16.403 7.944 ;
     RECT  15.797 73.92 16.409 74.376 ;
     RECT  16.357 9.648 16.444 12.312 ;
     RECT  16.193 21.408 16.445 49.56 ;
     RECT  15.793 57.024 16.517 58.056 ;
     RECT  16.081 75.84 16.621 75.864 ;
     RECT  16.157 13.92 16.643 19.848 ;
     RECT  16.621 75.84 16.645 76.248 ;
     RECT  15.797 72.576 16.657 72.936 ;
     RECT  16.403 2.064 16.697 7.8 ;
     RECT  16.645 75.168 16.732 76.248 ;
     RECT  16.444 9.792 16.733 12.312 ;
     RECT  16.445 31.44 16.733 49.56 ;
     RECT  16.657 71.76 16.835 72.936 ;
     RECT  16.835 72.768 16.841 72.936 ;
     RECT  16.409 73.92 16.877 74.184 ;
     RECT  16.333 55.92 16.909 55.944 ;
     RECT  16.517 57.024 16.909 57.72 ;
     RECT  16.445 21.408 16.913 30.264 ;
     RECT  16.261 77.28 16.945 78.456 ;
     RECT  15.875 69.216 16.981 69.24 ;
     RECT  16.913 21.408 16.985 27.816 ;
     RECT  16.909 55.92 17.057 57.72 ;
     RECT  16.945 77.28 17.057 79.224 ;
     RECT  15.973 50.736 17.093 52.536 ;
     RECT  16.643 14.736 17.125 19.848 ;
     RECT  17.125 14.736 17.165 19.944 ;
     RECT  16.733 31.44 17.165 48.648 ;
     RECT  17.057 78.048 17.237 79.224 ;
     RECT  16.301 66.48 17.269 67.08 ;
     RECT  17.165 31.44 17.345 48.264 ;
     RECT  17.165 19.536 17.365 19.944 ;
     RECT  16.985 21.408 17.365 21.72 ;
     RECT  17.093 50.736 17.413 52.392 ;
     RECT  16.985 22.752 17.489 27.816 ;
     RECT  17.345 31.44 17.489 46.008 ;
     RECT  16.732 75.744 17.525 76.248 ;
     RECT  17.057 55.92 17.593 57.48 ;
     RECT  17.525 75.744 17.597 76.152 ;
     RECT  17.413 50.256 17.701 52.392 ;
     RECT  15.769 54.624 17.701 54.696 ;
     RECT  17.593 55.776 17.701 57.48 ;
     RECT  17.237 79.2 17.701 79.224 ;
     RECT  16.697 5.184 17.749 7.8 ;
     RECT  17.521 8.832 17.749 8.856 ;
     RECT  16.913 29.04 17.893 30.264 ;
     RECT  16.981 68.352 17.948 69.24 ;
     RECT  17.893 29.04 17.953 30.408 ;
     RECT  17.489 31.44 17.953 45.864 ;
     RECT  16.733 10.32 18.025 12.312 ;
     RECT  17.629 13.344 18.025 13.368 ;
     RECT  16.877 73.92 18.025 74.088 ;
     RECT  18.025 10.32 18.044 13.368 ;
     RECT  18.044 10.32 18.169 13.608 ;
     RECT  17.269 66.48 18.205 67.176 ;
     RECT  17.749 5.184 18.277 8.856 ;
     RECT  17.165 14.736 18.421 18.504 ;
     RECT  17.365 19.536 18.421 21.72 ;
     RECT  17.237 78.048 18.421 78.072 ;
     RECT  17.701 79.2 18.421 79.464 ;
     RECT  18.421 14.736 18.449 21.72 ;
     RECT  17.489 22.752 18.449 27.672 ;
     RECT  18.449 14.736 18.493 27.672 ;
     RECT  17.345 47.088 18.565 48.264 ;
     RECT  16.841 72.768 18.601 72.792 ;
     RECT  18.025 73.92 18.601 74.712 ;
     RECT  16.697 2.064 18.608 3.96 ;
     RECT  18.277 5.088 18.608 8.856 ;
     RECT  18.169 10.224 18.608 13.608 ;
     RECT  18.493 14.736 18.608 28.008 ;
     RECT  17.953 29.04 18.608 45.864 ;
     RECT  18.565 46.896 18.608 48.264 ;
     RECT  17.701 49.296 18.608 52.392 ;
     RECT  17.701 54.624 18.608 57.48 ;
     RECT  17.917 58.512 18.608 58.536 ;
     RECT  16.049 60.048 18.608 60.072 ;
     RECT  18.205 66.48 18.608 67.368 ;
     RECT  17.948 68.352 18.608 70.104 ;
     RECT  17.989 71.28 18.608 71.304 ;
     RECT  18.601 72.768 18.608 74.712 ;
     RECT  17.597 75.84 18.608 76.152 ;
     RECT  18.421 78.048 18.608 79.464 ;
     RECT  18.608 2.064 18.712 79.932 ;
     RECT  18.712 2.064 18.904 79.662 ;
     RECT  18.904 58.416 18.965 60.072 ;
     RECT  18.904 55.488 19.037 56.664 ;
     RECT  18.904 2.064 19.043 13.368 ;
     RECT  18.904 71.952 19.043 71.976 ;
     RECT  19.043 8.208 19.325 13.368 ;
     RECT  18.904 29.52 19.397 53.112 ;
     RECT  18.904 17.472 19.433 28.488 ;
     RECT  19.397 29.52 19.469 51 ;
     RECT  19.469 29.52 19.475 32.856 ;
     RECT  18.965 58.512 19.505 60.072 ;
     RECT  19.469 33.888 19.541 51 ;
     RECT  18.904 72.96 19.612 75.816 ;
     RECT  19.505 58.56 19.715 60.072 ;
     RECT  18.904 66.432 19.721 67.368 ;
     RECT  19.325 8.208 19.757 13.08 ;
     RECT  18.904 14.736 19.793 16.296 ;
     RECT  19.541 45.12 19.901 51 ;
     RECT  19.433 17.472 20.005 21.96 ;
     RECT  18.904 54.144 20.005 54.504 ;
     RECT  19.612 75.792 20.009 75.816 ;
     RECT  19.043 2.064 20.045 7.224 ;
     RECT  20.005 17.328 20.045 21.96 ;
     RECT  19.433 23.088 20.045 28.488 ;
     RECT  20.005 54.144 20.077 54.936 ;
     RECT  19.037 56.112 20.077 56.664 ;
     RECT  19.612 72.96 20.149 74.664 ;
     RECT  19.793 14.832 20.156 16.296 ;
     RECT  20.045 17.328 20.156 21.528 ;
     RECT  20.156 14.832 20.243 21.528 ;
     RECT  19.397 52.128 20.257 53.112 ;
     RECT  20.077 54.144 20.257 56.664 ;
     RECT  18.904 78.336 20.257 78.648 ;
     RECT  20.045 24.96 20.329 28.488 ;
     RECT  18.904 68.928 20.329 69.24 ;
     RECT  20.149 72.864 20.333 74.664 ;
     RECT  20.257 78.336 20.365 79.08 ;
     RECT  20.333 72.864 20.369 74.04 ;
     RECT  19.901 45.12 20.397 46.104 ;
     RECT  19.757 10.608 20.428 13.08 ;
     RECT  20.329 24.96 20.437 28.584 ;
     RECT  19.475 29.568 20.437 32.856 ;
     RECT  20.257 52.128 20.473 56.664 ;
     RECT  19.757 8.208 20.477 9.528 ;
     RECT  20.437 24.96 20.545 32.856 ;
     RECT  19.541 33.888 20.545 43.8 ;
     RECT  20.477 8.304 20.585 9.528 ;
     RECT  20.329 68.928 20.617 69.48 ;
     RECT  18.904 70.8 20.617 70.824 ;
     RECT  19.901 47.328 20.653 51 ;
     RECT  20.473 52.128 20.653 57.096 ;
     RECT  20.005 64.416 20.693 64.44 ;
     RECT  20.617 68.928 20.797 70.824 ;
     RECT  20.428 13.008 20.819 13.08 ;
     RECT  20.545 24.96 20.819 43.8 ;
     RECT  19.721 67.344 20.819 67.368 ;
     RECT  20.045 23.088 20.821 23.736 ;
     RECT  20.243 14.832 20.833 16.296 ;
     RECT  20.819 24.96 20.909 39.432 ;
     RECT  20.819 40.512 20.909 43.8 ;
     RECT  20.653 47.328 20.909 57.096 ;
     RECT  19.715 58.656 20.945 60.072 ;
     RECT  20.797 68.832 20.965 70.824 ;
     RECT  20.045 2.064 20.981 5.592 ;
     RECT  20.045 7.152 21.049 7.224 ;
     RECT  20.965 68.832 21.049 71.64 ;
     RECT  20.909 47.328 21.125 57.048 ;
     RECT  20.397 45.264 21.157 46.104 ;
     RECT  21.125 47.328 21.157 53.112 ;
     RECT  20.945 58.656 21.161 58.68 ;
     RECT  21.049 68.784 21.161 71.64 ;
     RECT  20.585 8.496 21.193 9.528 ;
     RECT  20.428 10.608 21.193 12.024 ;
     RECT  20.909 40.704 21.301 43.8 ;
     RECT  20.293 61.92 21.301 61.944 ;
     RECT  21.301 61.488 21.377 61.944 ;
     RECT  20.369 72.864 21.409 73.416 ;
     RECT  21.409 72.144 21.413 73.416 ;
     RECT  20.981 2.064 21.449 5.304 ;
     RECT  21.193 8.496 21.449 12.024 ;
     RECT  20.909 24.96 21.481 39.096 ;
     RECT  20.819 13.008 21.557 13.032 ;
     RECT  21.157 45.264 21.665 53.112 ;
     RECT  21.481 24.768 21.701 39.096 ;
     RECT  21.161 68.784 21.875 70.728 ;
     RECT  20.833 14.208 21.877 16.296 ;
     RECT  20.243 17.28 21.877 21.528 ;
     RECT  20.821 22.992 21.877 23.736 ;
     RECT  21.049 75.648 21.913 75.672 ;
     RECT  18.904 77.088 21.913 77.112 ;
     RECT  21.701 31.824 21.925 39.096 ;
     RECT  21.301 40.704 21.925 43.848 ;
     RECT  21.665 45.264 21.973 46.104 ;
     RECT  21.701 24.768 21.989 30.792 ;
     RECT  21.973 44.976 22.021 46.104 ;
     RECT  20.945 59.856 22.057 60.072 ;
     RECT  21.377 61.488 22.057 61.704 ;
     RECT  21.665 47.184 22.067 53.112 ;
     RECT  22.021 44.88 22.108 46.104 ;
     RECT  22.067 47.568 22.133 53.112 ;
     RECT  21.413 72.144 22.133 73.224 ;
     RECT  22.057 59.856 22.165 61.704 ;
     RECT  21.049 7.104 22.201 7.224 ;
     RECT  13.021 0.144 22.205 0.84 ;
     RECT  22.165 59.712 22.213 61.704 ;
     RECT  22.213 59.52 22.259 61.704 ;
     RECT  21.913 74.832 22.273 75.672 ;
     RECT  21.913 76.8 22.273 77.112 ;
     RECT  22.259 60.96 22.277 61.704 ;
     RECT  21.875 68.784 22.277 69.576 ;
     RECT  22.133 72.144 22.313 72.456 ;
     RECT  22.277 60.96 22.349 61.512 ;
     RECT  21.449 9.36 22.453 12.024 ;
     RECT  21.877 22.656 22.453 23.736 ;
     RECT  22.273 74.832 22.489 77.112 ;
     RECT  22.453 22.608 22.549 23.736 ;
     RECT  22.489 58.128 22.561 58.152 ;
     RECT  21.449 2.064 22.597 3.912 ;
     RECT  21.449 5.136 22.597 5.304 ;
     RECT  22.549 22.512 22.597 23.736 ;
     RECT  21.989 24.768 22.597 30.744 ;
     RECT  21.925 31.824 22.597 43.848 ;
     RECT  22.453 9.024 22.633 12.024 ;
     RECT  22.201 6.864 22.669 7.224 ;
     RECT  22.597 2.064 22.745 5.736 ;
     RECT  22.489 73.488 22.745 77.112 ;
     RECT  21.877 14.208 22.789 21.528 ;
     RECT  22.597 22.512 22.789 30.744 ;
     RECT  22.745 5.28 22.813 5.736 ;
     RECT  21.125 54.096 22.813 57.048 ;
     RECT  22.561 58.08 22.813 58.152 ;
     RECT  20.365 78.336 22.813 79.224 ;
     RECT  22.813 54.096 22.835 58.152 ;
     RECT  22.669 6.864 22.849 7.464 ;
     RECT  21.875 70.56 22.849 70.728 ;
     RECT  22.133 47.568 22.853 52.392 ;
     RECT  22.813 78.192 22.853 79.224 ;
     RECT  22.633 8.88 22.885 12.024 ;
     RECT  22.489 13.104 22.885 13.128 ;
     RECT  22.349 60.96 22.889 61.224 ;
     RECT  22.277 68.832 22.889 69.576 ;
     RECT  22.745 76.752 22.889 77.112 ;
     RECT  22.885 8.88 22.921 13.128 ;
     RECT  22.789 14.208 22.921 30.744 ;
     RECT  22.849 70.56 22.957 70.824 ;
     RECT  22.921 8.88 22.997 30.744 ;
     RECT  22.108 45.552 23.101 46.104 ;
     RECT  22.853 47.568 23.101 49.032 ;
     RECT  22.745 73.488 23.101 75.672 ;
     RECT  22.997 28.176 23.137 30.744 ;
     RECT  22.597 31.824 23.137 44.376 ;
     RECT  22.835 54.336 23.137 58.152 ;
     RECT  22.259 59.52 23.245 59.736 ;
     RECT  23.137 54.336 23.281 58.44 ;
     RECT  22.853 78.192 23.281 79.176 ;
     RECT  23.281 54.336 23.324 58.488 ;
     RECT  23.245 59.52 23.324 59.784 ;
     RECT  22.205 0.144 23.353 0.36 ;
     RECT  22.849 6.864 23.42 7.56 ;
     RECT  22.997 8.88 23.42 27.192 ;
     RECT  23.137 28.176 23.425 44.376 ;
     RECT  23.353 0.144 23.465 0.456 ;
     RECT  23.42 6.864 23.497 27.192 ;
     RECT  23.465 0.144 23.501 0.312 ;
     RECT  22.957 70.56 23.569 71.352 ;
     RECT  22.853 50.016 23.893 52.392 ;
     RECT  23.281 78.096 24.001 79.176 ;
     RECT  22.745 2.064 24.008 3.912 ;
     RECT  22.813 5.28 24.008 5.832 ;
     RECT  23.497 6.816 24.008 27.192 ;
     RECT  23.425 28.176 24.008 44.52 ;
     RECT  23.101 45.552 24.008 49.032 ;
     RECT  23.893 50.016 24.008 53.016 ;
     RECT  23.324 54.336 24.008 59.784 ;
     RECT  22.889 61.2 24.008 61.224 ;
     RECT  21.697 62.832 24.008 62.856 ;
     RECT  22.889 68.832 24.008 68.904 ;
     RECT  23.569 70.56 24.008 71.736 ;
     RECT  23.101 72.96 24.008 75.672 ;
     RECT  22.889 76.8 24.008 77.112 ;
     RECT  24.001 78.096 24.008 79.224 ;
     RECT  24.008 2.064 24.112 79.932 ;
     RECT  24.112 2.064 24.304 79.662 ;
     RECT  24.304 6.288 24.365 7.224 ;
     RECT  24.304 59.52 24.365 59.784 ;
     RECT  24.304 72.96 24.365 73.512 ;
     RECT  24.365 6.288 24.401 7.176 ;
     RECT  24.304 74.976 24.401 79.272 ;
     RECT  24.365 73.488 24.419 73.512 ;
     RECT  24.401 6.672 24.437 7.176 ;
     RECT  24.304 22.512 24.437 43.656 ;
     RECT  24.304 8.448 24.467 21.528 ;
     RECT  24.401 74.976 24.473 75.288 ;
     RECT  24.473 75.264 24.581 75.288 ;
     RECT  24.304 52.992 25.085 53.448 ;
     RECT  24.467 13.824 25.091 21.528 ;
     RECT  25.091 14.832 25.121 21.528 ;
     RECT  24.401 76.8 25.121 79.272 ;
     RECT  25.121 76.896 25.139 79.272 ;
     RECT  24.437 24.576 25.193 43.656 ;
     RECT  25.139 77.088 25.193 79.272 ;
     RECT  24.304 69.312 25.333 71.736 ;
     RECT  24.304 5.184 25.373 5.304 ;
     RECT  25.091 13.824 25.373 13.848 ;
     RECT  25.193 77.088 25.373 77.112 ;
     RECT  24.304 45.744 25.477 48.792 ;
     RECT  24.437 6.816 25.513 7.176 ;
     RECT  25.373 5.232 25.585 5.304 ;
     RECT  25.513 6.288 25.585 7.176 ;
     RECT  25.121 17.232 25.585 21.528 ;
     RECT  24.437 22.512 25.585 23.4 ;
     RECT  24.467 8.448 25.621 12.6 ;
     RECT  24.304 2.064 25.657 3.912 ;
     RECT  25.193 24.576 25.661 41.544 ;
     RECT  25.333 69.312 25.667 72.312 ;
     RECT  25.477 45.552 25.669 48.792 ;
     RECT  24.304 49.92 25.669 52.008 ;
     RECT  25.193 78.096 25.697 79.272 ;
     RECT  23.501 0.144 25.733 0.264 ;
     RECT  25.621 8.448 25.769 13.368 ;
     RECT  25.585 5.232 25.772 7.176 ;
     RECT  25.769 8.448 25.772 9.288 ;
     RECT  25.085 53.184 25.801 53.448 ;
     RECT  24.304 54.624 25.801 58.44 ;
     RECT  25.772 5.232 25.859 9.288 ;
     RECT  25.667 69.312 25.877 69.864 ;
     RECT  25.193 42.768 25.909 43.656 ;
     RECT  25.669 45.552 25.909 52.008 ;
     RECT  25.661 24.624 25.913 41.544 ;
     RECT  25.913 30 25.949 41.544 ;
     RECT  25.909 45.264 25.949 52.008 ;
     RECT  25.877 69.504 26.003 69.864 ;
     RECT  25.949 30 26.021 40.632 ;
     RECT  25.949 45.264 26.057 46.824 ;
     RECT  25.859 6.768 26.093 9.288 ;
     RECT  25.121 14.832 26.093 16.152 ;
     RECT  26.093 14.832 26.125 14.856 ;
     RECT  25.585 17.232 26.197 23.4 ;
     RECT  25.909 42.768 26.197 44.136 ;
     RECT  26.057 45.264 26.197 46.104 ;
     RECT  24.304 61.2 26.197 61.416 ;
     RECT  24.304 66.864 26.197 66.888 ;
     RECT  25.801 53.184 26.237 58.44 ;
     RECT  26.197 61.2 26.243 62.04 ;
     RECT  26.017 75.504 26.261 75.528 ;
     RECT  26.261 75.504 26.269 76.392 ;
     RECT  26.243 61.344 26.284 62.04 ;
     RECT  26.269 73.776 26.293 73.8 ;
     RECT  26.269 75.408 26.293 76.392 ;
     RECT  25.697 78.096 26.309 79.032 ;
     RECT  25.667 70.848 26.339 72.312 ;
     RECT  26.093 15.84 26.341 16.152 ;
     RECT  26.197 17.232 26.341 23.448 ;
     RECT  26.341 15.84 26.345 23.448 ;
     RECT  26.197 65.952 26.413 66.888 ;
     RECT  25.657 2.064 26.444 4.104 ;
     RECT  25.859 5.232 26.444 5.592 ;
     RECT  25.733 0.144 26.453 0.216 ;
     RECT  25.769 10.656 26.453 13.368 ;
     RECT  26.453 11.808 26.485 13.368 ;
     RECT  26.125 14.592 26.485 14.856 ;
     RECT  26.093 6.768 26.525 7.896 ;
     RECT  26.293 73.776 26.629 76.392 ;
     RECT  26.485 11.808 26.633 14.856 ;
     RECT  26.345 19.392 26.633 23.448 ;
     RECT  26.444 2.064 26.669 5.592 ;
     RECT  26.629 73.776 26.675 76.968 ;
     RECT  26.633 21.792 26.701 23.448 ;
     RECT  25.913 24.624 26.701 29.016 ;
     RECT  26.339 72.288 26.723 72.312 ;
     RECT  26.093 9.264 26.737 9.288 ;
     RECT  26.453 10.656 26.737 10.68 ;
     RECT  26.413 65.808 26.737 66.888 ;
     RECT  26.669 3.072 26.741 5.592 ;
     RECT  25.949 47.856 26.773 52.008 ;
     RECT  26.633 11.808 26.813 13.368 ;
     RECT  26.633 14.688 26.885 14.856 ;
     RECT  26.197 42.768 26.885 46.104 ;
     RECT  26.675 75.504 26.885 76.968 ;
     RECT  26.701 21.792 26.921 29.016 ;
     RECT  26.021 39.744 26.953 40.632 ;
     RECT  26.197 41.616 26.953 41.64 ;
     RECT  26.737 9.264 26.957 10.68 ;
     RECT  26.021 30 26.993 38.328 ;
     RECT  26.003 69.504 27.101 69.72 ;
     RECT  26.525 6.768 27.209 7.176 ;
     RECT  26.953 39.744 27.277 41.64 ;
     RECT  26.773 47.856 27.277 52.056 ;
     RECT  26.284 61.344 27.313 61.56 ;
     RECT  26.957 9.264 27.349 10.104 ;
     RECT  27.277 47.28 27.349 52.056 ;
     RECT  27.313 61.2 27.353 61.56 ;
     RECT  26.993 30.624 27.385 38.328 ;
     RECT  27.277 39.552 27.385 41.64 ;
     RECT  26.309 78.144 27.389 79.032 ;
     RECT  26.921 21.792 27.395 28.44 ;
     RECT  26.885 14.832 27.421 14.856 ;
     RECT  26.345 15.84 27.421 18.312 ;
     RECT  26.237 53.184 27.493 57.72 ;
     RECT  26.737 65.808 27.493 67.128 ;
     RECT  26.339 70.848 27.493 71.16 ;
     RECT  27.395 25.68 27.497 28.44 ;
     RECT  26.813 11.808 27.529 13.08 ;
     RECT  27.389 78.144 27.529 78.984 ;
     RECT  27.209 6.768 27.565 7.128 ;
     RECT  26.885 42.768 27.596 45.816 ;
     RECT  26.675 73.776 27.605 74.52 ;
     RECT  25.657 63.792 27.637 63.816 ;
     RECT  27.349 46.896 27.673 52.056 ;
     RECT  27.493 53.184 27.673 58.056 ;
     RECT  27.101 69.504 27.713 69.528 ;
     RECT  26.741 3.072 27.745 4.44 ;
     RECT  26.741 5.472 27.745 5.592 ;
     RECT  27.493 65.568 27.745 67.128 ;
     RECT  27.596 42.672 27.757 45.816 ;
     RECT  24.365 59.52 27.781 59.544 ;
     RECT  26.885 75.696 27.853 75.72 ;
     RECT  27.745 3.072 27.889 5.592 ;
     RECT  27.565 6.624 27.889 7.128 ;
     RECT  27.385 30.624 27.965 41.64 ;
     RECT  27.497 26.112 27.997 28.44 ;
     RECT  27.757 42.672 28.001 44.424 ;
     RECT  27.349 8.448 28.028 10.104 ;
     RECT  27.637 63.792 28.033 63.912 ;
     RECT  27.853 75.696 28.037 76.008 ;
     RECT  27.529 11.184 28.069 13.08 ;
     RECT  27.493 70.656 28.105 71.16 ;
     RECT  27.889 3.072 28.115 7.128 ;
     RECT  28.028 8.352 28.115 10.104 ;
     RECT  28.069 11.184 28.165 13.704 ;
     RECT  27.421 14.832 28.165 18.312 ;
     RECT  28.105 70.656 28.177 71.4 ;
     RECT  27.997 26.112 28.211 29.256 ;
     RECT  27.781 59.52 28.213 59.832 ;
     RECT  26.633 19.392 28.249 20.76 ;
     RECT  27.395 21.792 28.249 22.776 ;
     RECT  28.033 63.792 28.253 64.344 ;
     RECT  27.965 30.624 28.277 41.496 ;
     RECT  28.253 63.792 28.321 64.056 ;
     RECT  27.395 24.624 28.357 24.696 ;
     RECT  27.605 74.016 28.357 74.52 ;
     RECT  28.277 30.24 28.361 41.496 ;
     RECT  27.757 45.552 28.405 45.816 ;
     RECT  27.673 46.896 28.405 58.056 ;
     RECT  28.249 19.392 28.465 22.776 ;
     RECT  28.357 23.952 28.465 24.696 ;
     RECT  28.211 26.112 28.465 28.2 ;
     RECT  28.321 63.36 28.465 64.056 ;
     RECT  28.177 70.608 28.501 71.4 ;
     RECT  28.165 11.184 28.573 18.312 ;
     RECT  28.115 8.448 28.609 10.104 ;
     RECT  28.573 11.136 28.609 18.312 ;
     RECT  28.405 45.552 28.645 58.056 ;
     RECT  28.213 59.088 28.645 59.832 ;
     RECT  28.357 74.016 28.681 74.712 ;
     RECT  28.037 75.696 28.681 75.72 ;
     RECT  26.669 2.064 28.717 2.088 ;
     RECT  28.115 3.072 28.717 6.888 ;
     RECT  28.645 45.552 28.796 59.832 ;
     RECT  27.353 61.2 28.796 61.368 ;
     RECT  27.529 77.376 28.825 78.984 ;
     RECT  28.609 8.448 28.861 18.312 ;
     RECT  28.465 19.392 28.861 28.2 ;
     RECT  28.825 77.088 28.933 78.984 ;
     RECT  28.796 45.552 29.005 61.368 ;
     RECT  28.861 8.448 29.077 28.2 ;
     RECT  28.001 42.672 29.113 44.136 ;
     RECT  29.113 42.576 29.18 44.136 ;
     RECT  29.005 45.504 29.18 61.368 ;
     RECT  28.717 2.064 29.408 6.888 ;
     RECT  29.077 7.92 29.408 28.2 ;
     RECT  28.211 29.232 29.408 29.256 ;
     RECT  28.361 30.72 29.408 41.496 ;
     RECT  29.18 42.576 29.408 61.368 ;
     RECT  28.465 63.312 29.408 64.056 ;
     RECT  27.745 65.568 29.408 67.176 ;
     RECT  28.501 70.08 29.408 71.4 ;
     RECT  28.069 72.96 29.408 72.984 ;
     RECT  28.681 74.016 29.408 75.72 ;
     RECT  28.933 76.992 29.408 78.984 ;
     RECT  29.408 2.064 29.512 79.932 ;
     RECT  29.512 2.064 29.704 79.662 ;
     RECT  29.704 13.824 29.729 14.76 ;
     RECT  29.704 73.2 29.765 77.688 ;
     RECT  29.704 53.28 29.837 53.352 ;
     RECT  29.765 77.664 29.843 77.688 ;
     RECT  29.704 78.96 29.843 79.464 ;
     RECT  29.704 54.336 29.873 58.728 ;
     RECT  29.765 73.2 29.884 76.536 ;
     RECT  29.704 24.624 30.089 29.256 ;
     RECT  29.704 2.064 30.125 6.648 ;
     RECT  29.704 34.176 30.125 48.792 ;
     RECT  29.704 50.064 30.131 52.056 ;
     RECT  30.125 45.504 30.197 48.792 ;
     RECT  29.873 54.336 30.227 58.44 ;
     RECT  30.197 47.424 30.269 48.792 ;
     RECT  30.131 50.88 30.269 52.056 ;
     RECT  29.704 15.84 30.305 17.064 ;
     RECT  30.089 24.624 30.305 26.904 ;
     RECT  29.884 75.504 30.305 76.536 ;
     RECT  29.837 53.328 30.341 53.352 ;
     RECT  30.305 75.504 30.413 75.96 ;
     RECT  30.089 28.032 30.485 29.256 ;
     RECT  29.704 59.808 30.515 61.368 ;
     RECT  30.515 59.856 30.521 61.368 ;
     RECT  29.704 30.72 30.557 33.144 ;
     RECT  29.704 68.352 30.563 68.376 ;
     RECT  30.413 75.744 30.593 75.96 ;
     RECT  29.704 21.792 30.697 23.304 ;
     RECT  30.697 21.792 30.709 23.352 ;
     RECT  30.521 60.672 30.737 61.368 ;
     RECT  30.593 75.744 30.737 75.768 ;
     RECT  29.704 63.312 30.769 64.968 ;
     RECT  29.704 69.984 30.769 71.928 ;
     RECT  29.884 73.2 30.769 74.136 ;
     RECT  29.704 11.088 30.805 12.312 ;
     RECT  29.704 18.096 30.805 20.376 ;
     RECT  30.709 21.408 30.805 23.352 ;
     RECT  30.769 69.984 30.809 74.136 ;
     RECT  29.729 14.112 30.841 14.76 ;
     RECT  30.769 63.312 30.841 65.4 ;
     RECT  30.227 54.336 30.845 57.432 ;
     RECT  30.125 5.184 30.851 6.648 ;
     RECT  30.809 69.984 30.853 72.648 ;
     RECT  30.845 55.776 30.881 56.088 ;
     RECT  30.845 57.072 30.881 57.432 ;
     RECT  30.841 13.968 30.901 14.76 ;
     RECT  30.805 18.096 30.947 23.544 ;
     RECT  29.704 8.688 30.949 9.912 ;
     RECT  29.843 78.96 30.953 79.272 ;
     RECT  30.953 78.96 30.989 79.224 ;
     RECT  30.125 38.4 31.025 44.472 ;
     RECT  30.805 11.088 31.052 12.552 ;
     RECT  30.901 13.632 31.052 14.76 ;
     RECT  30.947 21.072 31.093 23.544 ;
     RECT  30.305 24.624 31.093 24.696 ;
     RECT  30.125 34.176 31.093 37.416 ;
     RECT  31.025 38.4 31.093 38.52 ;
     RECT  30.305 25.68 31.129 26.904 ;
     RECT  30.485 28.032 31.129 29.064 ;
     RECT  30.851 5.664 31.139 6.648 ;
     RECT  31.052 11.088 31.139 14.76 ;
     RECT  31.093 21.072 31.139 24.696 ;
     RECT  30.269 51.744 31.165 52.056 ;
     RECT  31.021 53.04 31.165 53.064 ;
     RECT  31.129 25.68 31.169 29.064 ;
     RECT  31.139 13.488 31.201 14.76 ;
     RECT  30.557 30.72 31.205 33.048 ;
     RECT  30.853 69.984 31.205 71.736 ;
     RECT  31.025 39.552 31.237 44.472 ;
     RECT  30.197 45.504 31.237 46.248 ;
     RECT  31.201 61.536 31.285 61.56 ;
     RECT  31.139 6.048 31.309 6.648 ;
     RECT  29.704 7.632 31.309 7.656 ;
     RECT  31.169 25.68 31.345 28.728 ;
     RECT  30.947 18.096 31.349 20.04 ;
     RECT  31.237 39.552 31.381 46.248 ;
     RECT  30.269 47.424 31.381 47.688 ;
     RECT  30.989 79.056 31.385 79.224 ;
     RECT  30.125 2.064 31.417 3.912 ;
     RECT  31.205 69.984 31.417 70.632 ;
     RECT  31.345 25.584 31.421 28.728 ;
     RECT  31.381 39.552 31.421 47.688 ;
     RECT  30.881 55.872 31.421 56.088 ;
     RECT  31.421 45.696 31.493 47.688 ;
     RECT  31.165 51.744 31.525 53.064 ;
     RECT  31.421 39.552 31.529 44.616 ;
     RECT  30.949 8.688 31.561 10.104 ;
     RECT  31.139 11.088 31.561 12.312 ;
     RECT  31.525 51.216 31.573 53.064 ;
     RECT  30.845 54.336 31.573 54.648 ;
     RECT  31.417 69.744 31.589 70.632 ;
     RECT  31.421 55.872 31.619 55.896 ;
     RECT  31.532 77.04 31.619 77.064 ;
     RECT  30.227 58.416 31.637 58.44 ;
     RECT  31.309 6.048 31.669 7.656 ;
     RECT  31.561 8.688 31.669 12.312 ;
     RECT  31.589 68.928 31.673 70.632 ;
     RECT  31.529 39.552 31.715 43.56 ;
     RECT  31.715 39.552 31.753 43.32 ;
     RECT  30.305 16.608 31.813 17.064 ;
     RECT  31.205 71.712 31.817 71.736 ;
     RECT  31.417 2.064 31.849 4.104 ;
     RECT  31.385 79.056 31.853 79.128 ;
     RECT  31.573 51.216 31.861 54.648 ;
     RECT  31.849 2.064 31.885 4.44 ;
     RECT  31.201 13.488 31.907 15 ;
     RECT  31.861 50.352 31.916 54.648 ;
     RECT  31.907 13.488 31.925 13.608 ;
     RECT  31.925 13.584 31.948 13.608 ;
     RECT  31.205 31.104 31.957 33.048 ;
     RECT  31.093 34.176 31.957 38.52 ;
     RECT  31.916 50.352 31.957 54.744 ;
     RECT  31.849 72.288 31.957 72.312 ;
     RECT  30.809 73.92 31.957 74.136 ;
     RECT  31.957 31.104 31.961 38.52 ;
     RECT  31.753 39.552 31.961 42.168 ;
     RECT  31.349 18.288 31.993 20.04 ;
     RECT  31.139 21.072 31.993 24.6 ;
     RECT  31.957 72.288 31.997 74.136 ;
     RECT  31.907 14.592 32.012 15 ;
     RECT  31.961 31.104 32.044 37.032 ;
     RECT  26.453 0.144 32.051 0.168 ;
     RECT  32.012 14.592 32.099 15.048 ;
     RECT  32.099 14.592 32.177 14.904 ;
     RECT  31.705 30 32.177 30.024 ;
     RECT  31.961 39.552 32.177 41.16 ;
     RECT  30.269 48.672 32.209 48.792 ;
     RECT  31.885 2.064 32.293 5.064 ;
     RECT  31.669 6.048 32.293 12.312 ;
     RECT  30.841 62.976 32.321 65.4 ;
     RECT  31.813 16.128 32.353 17.064 ;
     RECT  31.529 44.592 32.357 44.616 ;
     RECT  32.353 16.128 32.389 17.16 ;
     RECT  31.993 18.288 32.389 24.6 ;
     RECT  32.044 31.104 32.389 32.856 ;
     RECT  31.961 38.16 32.389 38.52 ;
     RECT  32.177 39.552 32.389 40.152 ;
     RECT  32.389 38.16 32.429 40.152 ;
     RECT  32.177 41.136 32.429 41.16 ;
     RECT  32.293 2.064 32.573 12.312 ;
     RECT  31.961 42.144 32.573 42.168 ;
     RECT  31.957 50.352 32.609 55.272 ;
     RECT  31.493 45.696 32.677 47.496 ;
     RECT  29.704 67.056 32.677 67.32 ;
     RECT  32.389 16.128 32.681 24.6 ;
     RECT  32.353 59.184 32.713 59.208 ;
     RECT  31.421 25.584 32.717 28.296 ;
     RECT  32.609 51.984 32.717 55.272 ;
     RECT  32.717 25.68 32.725 28.296 ;
     RECT  32.209 48.672 32.749 49.08 ;
     RECT  30.881 57.408 32.749 57.432 ;
     RECT  32.573 2.592 32.789 12.312 ;
     RECT  31.673 69.216 32.821 70.632 ;
     RECT  32.177 14.592 32.897 14.808 ;
     RECT  32.749 48.624 32.897 49.08 ;
     RECT  32.725 25.68 32.917 28.92 ;
     RECT  32.681 18.432 32.965 24.6 ;
     RECT  32.821 69.216 32.965 70.776 ;
     RECT  32.044 34.176 33.005 37.032 ;
     RECT  32.749 56.736 33.037 57.432 ;
     RECT  32.789 4.176 33.077 12.312 ;
     RECT  32.821 76.128 33.109 76.152 ;
     RECT  32.677 45.696 33.181 47.64 ;
     RECT  32.897 48.624 33.181 48.696 ;
     RECT  32.789 2.592 33.221 3.144 ;
     RECT  33.181 45.696 33.221 48.696 ;
     RECT  33.109 76.128 33.253 76.344 ;
     RECT  32.965 18.432 33.257 24.648 ;
     RECT  33.077 8.544 33.289 12.312 ;
     RECT  33.257 18.432 33.329 23.544 ;
     RECT  33.005 34.176 33.329 36.984 ;
     RECT  32.677 66.576 33.329 67.32 ;
     RECT  33.253 76.128 33.329 76.488 ;
     RECT  32.321 62.976 33.361 64.968 ;
     RECT  33.329 22.704 33.373 23.544 ;
     RECT  33.329 18.432 33.401 21.48 ;
     RECT  32.917 25.68 33.469 29.064 ;
     RECT  33.401 18.432 33.473 21.432 ;
     RECT  33.329 67.008 33.473 67.32 ;
     RECT  33.329 76.32 33.505 76.488 ;
     RECT  33.221 2.592 33.541 3.096 ;
     RECT  33.181 14.352 33.541 14.376 ;
     RECT  33.037 61.392 33.541 61.416 ;
     RECT  33.361 62.832 33.541 65.16 ;
     RECT  32.681 16.128 33.577 16.344 ;
     RECT  32.609 50.352 33.577 50.664 ;
     RECT  32.429 38.4 33.581 40.152 ;
     RECT  31.997 72.288 33.596 72.984 ;
     RECT  31.997 74.112 33.596 74.136 ;
     RECT  32.965 68.928 33.613 70.776 ;
     RECT  33.596 72.288 33.613 74.136 ;
     RECT  33.289 8.544 33.653 12.552 ;
     RECT  33.613 68.928 33.683 74.136 ;
     RECT  33.037 56.304 33.685 57.432 ;
     RECT  33.221 45.696 33.689 48.648 ;
     RECT  31.753 43.296 33.692 43.32 ;
     RECT  33.653 11.184 33.721 12.552 ;
     RECT  33.541 13.632 33.721 14.376 ;
     RECT  33.469 25.68 33.781 29.16 ;
     RECT  32.389 30.144 33.781 32.856 ;
     RECT  32.717 51.984 33.793 54.36 ;
     RECT  33.692 43.296 33.794 43.704 ;
     RECT  33.577 15.984 33.829 16.344 ;
     RECT  33.257 24.624 33.829 24.648 ;
     RECT  33.781 25.68 33.829 32.856 ;
     RECT  33.473 67.056 33.937 67.32 ;
     RECT  33.581 39.456 33.973 40.152 ;
     RECT  32.965 41.184 33.973 41.4 ;
     RECT  33.793 51.984 34.009 54.744 ;
     RECT  33.685 55.824 34.009 57.432 ;
     RECT  33.683 74.064 34.124 74.136 ;
     RECT  33.829 24.624 34.165 32.856 ;
     RECT  33.329 34.176 34.165 34.776 ;
     RECT  34.124 74.064 34.165 74.424 ;
     RECT  32.713 59.184 34.189 59.784 ;
     RECT  33.541 61.392 34.189 65.16 ;
     RECT  31.853 79.104 34.189 79.128 ;
     RECT  33.577 49.776 34.225 50.664 ;
     RECT  34.009 51.984 34.225 57.432 ;
     RECT  33.683 68.928 34.225 72.888 ;
     RECT  33.541 2.256 34.297 3.096 ;
     RECT  33.077 4.176 34.297 7.416 ;
     RECT  34.165 74.064 34.297 75.24 ;
     RECT  33.505 76.32 34.297 76.92 ;
     RECT  33.473 21.12 34.405 21.432 ;
     RECT  33.829 15.984 34.549 16.536 ;
     RECT  33.973 39.456 34.549 41.4 ;
     RECT  34.225 49.776 34.585 57.432 ;
     RECT  33.473 18.432 34.657 20.04 ;
     RECT  34.405 21.12 34.657 21.528 ;
     RECT  33.794 43.296 34.657 43.656 ;
     RECT  33.937 67.056 34.657 67.368 ;
     RECT  33.653 8.544 34.693 10.104 ;
     RECT  34.693 8.496 34.729 10.104 ;
     RECT  34.297 2.256 34.765 7.416 ;
     RECT  34.729 8.496 34.765 10.152 ;
     RECT  33.721 11.184 34.765 14.376 ;
     RECT  33.329 35.904 34.765 36.984 ;
     RECT  33.581 38.4 34.765 38.472 ;
     RECT  34.765 2.256 34.808 14.376 ;
     RECT  34.549 15.984 34.808 17.112 ;
     RECT  34.657 18.432 34.808 21.528 ;
     RECT  33.373 22.752 34.808 23.544 ;
     RECT  34.165 24.624 34.808 34.776 ;
     RECT  34.765 35.904 34.808 38.472 ;
     RECT  34.549 39.456 34.808 42.024 ;
     RECT  34.657 43.056 34.808 43.656 ;
     RECT  34.117 44.64 34.808 44.664 ;
     RECT  33.689 45.696 34.808 48.504 ;
     RECT  34.585 49.536 34.808 57.432 ;
     RECT  34.189 59.184 34.808 65.16 ;
     RECT  34.657 66.816 34.808 67.368 ;
     RECT  34.225 68.736 34.808 72.888 ;
     RECT  34.297 74.064 34.808 76.92 ;
     RECT  34.189 78.624 34.808 79.128 ;
     RECT  34.808 2.148 34.912 79.932 ;
     RECT  34.912 2.256 35.104 79.662 ;
     RECT  35.104 2.256 35.201 10.632 ;
     RECT  35.104 68.352 35.201 72.744 ;
     RECT  35.201 2.256 35.237 9.336 ;
     RECT  35.104 78.48 35.237 78.744 ;
     RECT  35.104 15.648 35.26 21.528 ;
     RECT  35.237 2.256 35.267 9.288 ;
     RECT  35.201 10.32 35.267 10.632 ;
     RECT  35.104 58.656 35.273 63.624 ;
     RECT  35.104 64.704 35.273 66.072 ;
     RECT  35.201 68.352 35.309 70.68 ;
     RECT  35.104 22.752 35.345 29.064 ;
     RECT  35.26 15.84 35.381 21.528 ;
     RECT  35.345 23.52 35.381 29.064 ;
     RECT  35.104 38.352 35.381 48.888 ;
     RECT  35.309 69.504 35.417 70.68 ;
     RECT  35.381 24.048 35.489 29.064 ;
     RECT  35.237 78.624 35.525 78.744 ;
     RECT  35.104 74.064 35.597 74.616 ;
     RECT  35.381 47.28 35.692 48.888 ;
     RECT  35.381 38.352 35.699 46.056 ;
     RECT  35.692 47.28 35.699 48.504 ;
     RECT  35.417 69.504 35.741 70.104 ;
     RECT  35.525 78.72 35.813 78.744 ;
     RECT  35.104 11.76 35.921 13.992 ;
     RECT  35.104 50.4 35.957 57.432 ;
     RECT  35.267 2.256 35.993 9.096 ;
     RECT  35.993 2.256 36.083 7.464 ;
     RECT  35.381 15.84 36.083 21.24 ;
     RECT  35.957 50.544 36.083 57.432 ;
     RECT  35.273 62.064 36.083 63 ;
     RECT  35.699 38.352 36.133 44.472 ;
     RECT  36.083 62.832 36.137 63 ;
     RECT  35.201 71.712 36.169 72.744 ;
     RECT  35.993 8.496 36.173 9.096 ;
     RECT  35.267 10.608 36.173 10.632 ;
     RECT  35.921 11.76 36.173 12.552 ;
     RECT  35.489 24.048 36.209 28.44 ;
     RECT  36.083 50.544 36.317 51.384 ;
     RECT  36.209 24.048 36.371 25.704 ;
     RECT  35.104 30.336 36.385 31.56 ;
     RECT  35.104 32.784 36.385 36.936 ;
     RECT  35.273 58.656 36.389 60.84 ;
     RECT  35.104 67.296 36.389 67.32 ;
     RECT  36.173 11.76 36.421 12.312 ;
     RECT  36.371 24.048 36.421 25.656 ;
     RECT  35.273 64.704 36.421 65.16 ;
     RECT  36.169 71.616 36.421 72.744 ;
     RECT  36.209 26.736 36.469 28.44 ;
     RECT  35.921 13.968 36.493 13.992 ;
     RECT  36.083 2.256 36.497 4.728 ;
     RECT  36.385 30.336 36.515 36.936 ;
     RECT  36.083 18.72 36.533 21.24 ;
     RECT  36.133 38.16 36.533 44.472 ;
     RECT  35.699 45.6 36.533 46.056 ;
     RECT  36.389 58.656 36.533 58.68 ;
     RECT  36.137 62.832 36.533 62.856 ;
     RECT  35.309 68.352 36.533 68.376 ;
     RECT  36.421 71.616 36.533 72.84 ;
     RECT  36.515 33.984 36.556 36.936 ;
     RECT  36.556 34.128 36.569 36.936 ;
     RECT  36.493 13.968 36.577 14.856 ;
     RECT  35.104 75.936 36.605 76.92 ;
     RECT  36.524 49.536 36.611 49.56 ;
     RECT  36.083 52.464 36.637 57.432 ;
     RECT  36.533 38.16 36.641 42.6 ;
     RECT  36.533 18.72 36.677 20.952 ;
     RECT  36.469 26.736 36.709 29.112 ;
     RECT  36.515 30.336 36.709 33 ;
     RECT  36.577 13.968 36.785 14.712 ;
     RECT  36.605 75.936 36.805 75.96 ;
     RECT  36.173 8.496 36.821 8.52 ;
     RECT  36.637 52.464 36.821 57.864 ;
     RECT  35.597 74.304 36.851 74.616 ;
     RECT  36.497 3.36 36.857 4.728 ;
     RECT  36.421 10.032 36.893 10.056 ;
     RECT  36.805 75.792 36.893 75.96 ;
     RECT  36.677 18.72 36.899 19.752 ;
     RECT  35.741 69.504 36.925 69.528 ;
     RECT  36.569 35.856 36.929 36.936 ;
     RECT  36.709 26.736 37.001 33 ;
     RECT  36.533 72.528 37.033 72.84 ;
     RECT  36.497 2.256 37.037 2.28 ;
     RECT  36.421 64.608 37.069 65.16 ;
     RECT  36.083 6.24 37.073 7.464 ;
     RECT  35.699 47.28 37.073 48.408 ;
     RECT  36.533 43.68 37.1 44.472 ;
     RECT  36.533 45.6 37.1 45.72 ;
     RECT  36.641 38.16 37.141 42.024 ;
     RECT  36.857 3.36 37.145 4.392 ;
     RECT  36.925 69.456 37.177 69.528 ;
     RECT  37.141 37.728 37.181 42.024 ;
     RECT  37.069 64.368 37.181 65.16 ;
     RECT  37.033 72.528 37.181 72.936 ;
     RECT  37.181 40.992 37.187 42.024 ;
     RECT  37.1 43.68 37.187 45.72 ;
     RECT  37.187 43.68 37.209 45.624 ;
     RECT  37.187 42 37.217 42.024 ;
     RECT  36.421 11.376 37.253 12.312 ;
     RECT  36.821 52.464 37.289 54.36 ;
     RECT  37.145 4.272 37.325 4.392 ;
     RECT  37.181 37.728 37.325 39.912 ;
     RECT  36.569 34.128 37.361 34.632 ;
     RECT  36.389 59.856 37.361 60.84 ;
     RECT  36.677 20.832 37.433 20.856 ;
     RECT  37.177 69.456 37.465 70.296 ;
     RECT  37.289 52.464 37.469 53.64 ;
     RECT  36.317 50.544 37.501 50.568 ;
     RECT  36.821 55.92 37.532 57.864 ;
     RECT  37.253 11.376 37.541 12.12 ;
     RECT  36.899 18.72 37.541 18.744 ;
     RECT  36.929 35.856 37.541 36.408 ;
     RECT  37.501 50.256 37.541 50.568 ;
     RECT  37.001 26.736 37.577 29.496 ;
     RECT  37.532 55.92 37.619 58.632 ;
     RECT  37.325 37.824 37.649 39.912 ;
     RECT  37.073 6.24 37.681 6.264 ;
     RECT  36.785 14.256 37.717 14.712 ;
     RECT  36.853 77.712 37.717 77.736 ;
     RECT  37.541 11.376 37.753 11.976 ;
     RECT  37.209 43.68 37.757 43.704 ;
     RECT  37.073 7.44 37.789 7.464 ;
     RECT  36.421 23.088 37.789 25.656 ;
     RECT  37.577 26.736 37.789 26.808 ;
     RECT  37.789 23.088 37.829 26.808 ;
     RECT  37.181 72.576 37.865 72.936 ;
     RECT  37.001 30.816 37.901 33 ;
     RECT  37.717 14.256 37.933 14.808 ;
     RECT  36.083 15.84 37.933 17.448 ;
     RECT  37.649 38.16 37.937 39.912 ;
     RECT  37.681 5.808 37.969 6.264 ;
     RECT  37.209 45.264 37.973 45.624 ;
     RECT  37.909 67.152 37.996 67.176 ;
     RECT  37.717 77.232 38.041 77.736 ;
     RECT  37.969 5.664 38.045 6.264 ;
     RECT  37.465 69.024 38.077 70.296 ;
     RECT  36.893 75.792 38.081 75.816 ;
     RECT  37.829 23.088 38.108 25.224 ;
     RECT  37.361 60.816 38.185 60.84 ;
     RECT  37.181 64.368 38.185 65.016 ;
     RECT  38.108 22.176 38.195 25.224 ;
     RECT  37.829 26.208 38.195 26.808 ;
     RECT  38.045 5.664 38.225 6.072 ;
     RECT  38.185 60.816 38.225 60.984 ;
     RECT  37.577 27.888 38.243 29.496 ;
     RECT  37.753 10.992 38.257 11.976 ;
     RECT  37.933 14.256 38.257 17.448 ;
     RECT  36.899 19.728 38.261 19.752 ;
     RECT  38.077 68.928 38.297 70.296 ;
     RECT  37.541 35.856 38.365 36.36 ;
     RECT  38.195 23.088 38.369 25.224 ;
     RECT  38.149 43.248 38.401 43.272 ;
     RECT  37.901 31.44 38.437 33 ;
     RECT  37.361 34.128 38.437 34.392 ;
     RECT  37.325 4.368 38.441 4.392 ;
     RECT  38.243 29.04 38.441 29.496 ;
     RECT  37.865 72.576 38.441 72.84 ;
     RECT  38.257 13.68 38.473 17.448 ;
     RECT  38.185 64.368 38.473 65.976 ;
     RECT  38.243 27.888 38.477 27.912 ;
     RECT  38.473 13.632 38.513 17.448 ;
     RECT  38.401 42.864 38.545 43.272 ;
     RECT  36.851 74.304 38.545 74.328 ;
     RECT  37.073 47.28 38.581 48.168 ;
     RECT  38.437 31.44 38.588 34.392 ;
     RECT  38.041 77.088 38.621 77.736 ;
     RECT  37.541 50.256 38.627 50.28 ;
     RECT  38.473 63.792 38.657 65.976 ;
     RECT  38.588 31.44 38.675 34.488 ;
     RECT  38.545 42.768 38.693 43.272 ;
     RECT  38.369 23.088 38.729 25.08 ;
     RECT  38.689 19.824 38.761 19.848 ;
     RECT  38.693 42.864 38.765 43.272 ;
     RECT  38.545 74.112 38.765 74.328 ;
     RECT  37.469 53.04 38.797 53.64 ;
     RECT  38.581 47.28 38.833 48.84 ;
     RECT  38.725 58.656 38.837 58.68 ;
     RECT  38.657 63.792 38.837 65.592 ;
     RECT  38.765 74.256 38.837 74.328 ;
     RECT  38.513 13.632 38.869 17.112 ;
     RECT  37.187 40.992 38.869 41.016 ;
     RECT  38.581 71.568 38.869 71.592 ;
     RECT  38.869 70.608 38.87 71.592 ;
     RECT  38.773 3.984 38.873 4.008 ;
     RECT  38.621 77.088 38.873 77.352 ;
     RECT  38.441 72.576 38.909 72.744 ;
     RECT  37.619 55.92 38.941 57.576 ;
     RECT  38.833 47.28 38.945 49.08 ;
     RECT  38.909 72.576 38.945 72.6 ;
     RECT  38.869 13.536 38.956 17.112 ;
     RECT  38.257 10.464 38.973 11.976 ;
     RECT  37.973 45.264 38.977 45.288 ;
     RECT  38.873 77.088 38.981 77.256 ;
     RECT  37.937 38.736 39.017 39.912 ;
     RECT  38.977 45.12 39.017 45.288 ;
     RECT  38.956 13.632 39.053 17.112 ;
     RECT  38.675 34.176 39.053 34.488 ;
     RECT  38.365 35.472 39.053 36.36 ;
     RECT  38.869 40.992 39.085 41.832 ;
     RECT  38.87 70.608 39.107 71.256 ;
     RECT  38.837 74.256 39.148 74.28 ;
     RECT  38.225 5.76 39.157 6.072 ;
     RECT  37.789 7.44 39.157 7.8 ;
     RECT  38.973 10.464 39.157 11.4 ;
     RECT  39.157 5.76 39.203 7.8 ;
     RECT  39.053 34.368 39.229 34.488 ;
     RECT  39.053 35.472 39.229 35.976 ;
     RECT  39.203 6 39.233 7.8 ;
     RECT  38.797 52.32 39.349 53.64 ;
     RECT  38.945 47.28 39.397 48.312 ;
     RECT  39.349 52.224 39.481 53.64 ;
     RECT  38.005 54.72 39.481 54.744 ;
     RECT  38.725 67.248 39.481 67.272 ;
     RECT  38.297 68.928 39.517 69.48 ;
     RECT  38.225 60.96 39.541 60.984 ;
     RECT  38.149 62.112 39.541 62.136 ;
     RECT  38.195 26.208 39.548 26.232 ;
     RECT  39.481 52.224 39.553 54.744 ;
     RECT  38.941 55.92 39.553 58.008 ;
     RECT  38.441 29.04 39.733 29.064 ;
     RECT  39.053 13.68 39.769 17.112 ;
     RECT  39.589 21.984 39.769 22.008 ;
     RECT  38.729 23.328 39.769 23.352 ;
     RECT  39.553 52.224 39.829 58.008 ;
     RECT  38.149 59.808 39.829 59.832 ;
     RECT  39.017 38.736 39.836 39.384 ;
     RECT  39.085 40.752 39.913 41.832 ;
     RECT  38.765 43.152 39.913 43.272 ;
     RECT  39.884 18.768 39.925 18.792 ;
     RECT  38.761 19.824 39.925 20.808 ;
     RECT  39.769 21.984 39.932 23.352 ;
     RECT  39.913 40.752 39.932 43.272 ;
     RECT  39.517 68.688 40.021 69.48 ;
     RECT  38.581 2.88 40.208 2.904 ;
     RECT  39.233 6 40.208 7.464 ;
     RECT  37.609 8.832 40.208 8.856 ;
     RECT  39.157 10.224 40.208 11.4 ;
     RECT  39.769 13.68 40.208 17.496 ;
     RECT  39.925 18.768 40.208 20.808 ;
     RECT  39.932 21.984 40.208 24.072 ;
     RECT  38.729 25.056 40.208 25.08 ;
     RECT  39.548 26.208 40.208 26.664 ;
     RECT  39.733 28.512 40.208 29.064 ;
     RECT  39.397 30.24 40.208 30.264 ;
     RECT  38.675 31.44 40.208 33.048 ;
     RECT  39.229 34.368 40.208 35.976 ;
     RECT  39.877 37.008 40.208 37.032 ;
     RECT  39.836 38.112 40.208 39.384 ;
     RECT  39.932 40.752 40.208 44.04 ;
     RECT  39.017 45.12 40.208 45.144 ;
     RECT  39.397 46.464 40.208 48.312 ;
     RECT  39.733 49.536 40.208 49.56 ;
     RECT  39.829 52.224 40.208 58.68 ;
     RECT  39.829 59.712 40.208 59.832 ;
     RECT  39.541 60.96 40.208 62.136 ;
     RECT  38.837 63.792 40.208 64.44 ;
     RECT  38.837 65.568 40.208 65.592 ;
     RECT  39.481 67.056 40.208 67.272 ;
     RECT  40.021 68.496 40.208 69.48 ;
     RECT  39.107 70.608 40.208 70.632 ;
     RECT  39.085 76.704 40.208 76.728 ;
     RECT  40.208 2.148 40.312 79.932 ;
     RECT  40.312 2.418 40.504 79.662 ;
    LAYER M5 ;
     RECT  9.024 0.144 13.512 0.467 ;
     RECT  9.024 0.467 13.08 0.515 ;
     RECT  9.024 0.515 12.936 2.137 ;
     RECT  2.4 2.137 2.52 2.151 ;
     RECT  7.8 2.137 7.92 2.151 ;
     RECT  9.024 2.137 13.32 2.151 ;
     RECT  18.6 2.137 18.72 2.151 ;
     RECT  24 2.137 24.12 2.151 ;
     RECT  29.4 2.137 29.52 2.151 ;
     RECT  34.8 2.137 34.92 2.151 ;
     RECT  40.2 2.137 40.32 2.151 ;
     RECT  24 2.151 24.312 2.245 ;
     RECT  34.8 2.151 35.112 2.245 ;
     RECT  29.4 2.151 29.712 2.293 ;
     RECT  20.88 0.373 20.904 2.581 ;
     RECT  5.232 2.293 5.256 2.821 ;
     RECT  20.784 2.581 20.904 2.821 ;
     RECT  30.768 2.821 30.792 2.963 ;
     RECT  32.016 0.133 32.04 3.061 ;
     RECT  23.568 2.245 24.312 3.443 ;
     RECT  20.016 2.821 20.904 3.587 ;
     RECT  25.632 2.245 25.656 3.587 ;
     RECT  20.784 3.587 20.904 3.923 ;
     RECT  2.4 2.151 2.712 3.925 ;
     RECT  34.8 2.245 35.928 3.971 ;
     RECT  38.784 2.869 38.808 4.019 ;
     RECT  5.232 2.821 5.928 4.069 ;
     RECT  5.232 4.069 6.072 4.115 ;
     RECT  34.8 3.971 35.352 4.163 ;
     RECT  32.016 3.061 32.472 4.261 ;
     RECT  28.272 3.541 28.296 4.405 ;
     RECT  29.28 2.293 29.712 4.405 ;
     RECT  26.496 4.117 26.52 4.643 ;
     RECT  28.272 4.405 29.712 4.643 ;
     RECT  16.512 2.677 16.536 4.691 ;
     RECT  5.904 4.115 6.072 4.883 ;
     RECT  18.6 2.151 18.912 5.077 ;
     RECT  34.8 4.163 35.112 5.605 ;
     RECT  30.816 3.877 30.84 5.653 ;
     RECT  32.016 4.261 32.808 5.653 ;
     RECT  16.368 5.125 16.392 5.699 ;
     RECT  2.4 3.925 2.808 5.747 ;
     RECT  22.608 4.501 22.632 5.747 ;
     RECT  18.288 5.077 18.912 5.797 ;
     RECT  30.816 5.653 32.808 6.083 ;
     RECT  18.288 5.797 19.416 6.131 ;
     RECT  7.8 2.151 13.512 6.229 ;
     RECT  29.232 4.643 29.712 6.229 ;
     RECT  30.816 6.083 32.472 6.229 ;
     RECT  18.6 6.131 19.416 6.323 ;
     RECT  5.904 4.883 5.928 6.757 ;
     RECT  39.168 5.749 39.192 6.851 ;
     RECT  18.6 6.323 18.912 7.189 ;
     RECT  5.904 6.757 6.552 7.333 ;
     RECT  7.8 6.229 13.608 7.333 ;
     RECT  5.904 7.333 13.608 7.379 ;
     RECT  24 3.443 24.312 7.381 ;
     RECT  34.8 5.605 36.072 7.381 ;
     RECT  34.128 7.381 36.072 7.427 ;
     RECT  34.128 7.427 35.976 7.475 ;
     RECT  17.76 7.189 18.912 7.909 ;
     RECT  29.232 6.229 32.472 7.909 ;
     RECT  28.08 7.093 28.104 8.437 ;
     RECT  29.088 7.909 32.472 8.437 ;
     RECT  20.88 3.923 20.904 8.485 ;
     RECT  17.76 7.909 19.032 8.579 ;
     RECT  5.904 7.379 13.512 8.723 ;
     RECT  25.824 6.277 25.848 8.723 ;
     RECT  38.784 7.765 38.808 8.821 ;
     RECT  28.08 8.437 32.472 8.867 ;
     RECT  38.784 8.821 39.192 8.867 ;
     RECT  23.472 7.381 24.312 8.869 ;
     RECT  7.8 8.723 13.512 8.917 ;
     RECT  3.936 7.381 3.96 9.155 ;
     RECT  23.04 8.869 24.312 9.253 ;
     RECT  34.128 7.475 35.256 9.301 ;
     RECT  28.08 8.867 28.248 9.491 ;
     RECT  18.6 8.579 19.032 9.493 ;
     RECT  20.592 8.485 20.904 9.539 ;
     RECT  2.4 5.747 2.712 9.637 ;
     RECT  5.904 8.723 6.552 10.261 ;
     RECT  34.032 9.301 35.256 10.355 ;
     RECT  2.4 9.637 2.904 10.595 ;
     RECT  23.04 9.253 24.456 10.693 ;
     RECT  25.68 9.637 25.704 10.693 ;
     RECT  4.992 10.261 6.552 10.835 ;
     RECT  7.8 8.917 13.896 10.883 ;
     RECT  23.04 10.693 25.704 10.883 ;
     RECT  16.368 7.909 16.392 10.931 ;
     RECT  39.168 8.867 39.192 11.027 ;
     RECT  29.232 8.867 32.472 11.219 ;
     RECT  29.232 11.219 32.376 11.221 ;
     RECT  4.992 10.835 5.016 11.411 ;
     RECT  18.6 9.493 19.368 11.413 ;
     RECT  18.096 11.413 19.368 11.459 ;
     RECT  29.088 11.221 32.376 11.459 ;
     RECT  23.04 10.883 25.32 11.939 ;
     RECT  6 10.835 6.552 12.277 ;
     RECT  7.8 10.883 13.512 12.277 ;
     RECT  29.232 11.459 32.376 12.323 ;
     RECT  23.04 11.939 25.08 12.421 ;
     RECT  34.032 10.355 35.112 12.517 ;
     RECT  14.784 12.181 14.808 12.853 ;
     RECT  20.88 9.539 20.904 12.853 ;
     RECT  14.496 12.853 14.808 12.899 ;
     RECT  2.4 10.595 2.808 13.045 ;
     RECT  28.08 9.491 28.104 13.045 ;
     RECT  29.232 12.323 32.088 13.045 ;
     RECT  28.08 13.045 32.088 13.715 ;
     RECT  33.648 12.517 35.88 13.715 ;
     RECT  28.176 13.715 32.088 13.859 ;
     RECT  34.8 13.715 35.88 13.957 ;
     RECT  34.8 13.957 36.552 14.003 ;
     RECT  22.896 12.421 25.08 14.339 ;
     RECT  4.512 13.285 4.536 14.341 ;
     RECT  4.512 14.341 4.92 14.387 ;
     RECT  33.648 13.715 33.672 14.387 ;
     RECT  37.584 11.749 37.608 14.675 ;
     RECT  16.608 12.037 16.632 14.773 ;
     RECT  18.096 11.459 18.912 14.773 ;
     RECT  29.232 13.859 32.088 14.819 ;
     RECT  16.608 14.773 18.912 14.821 ;
     RECT  20.352 12.853 20.904 14.821 ;
     RECT  36.528 14.003 36.552 14.867 ;
     RECT  16.608 14.821 20.904 15.251 ;
     RECT  6 12.277 13.512 15.443 ;
     RECT  38.88 11.941 38.904 15.491 ;
     RECT  22.896 14.339 24.936 15.493 ;
     RECT  34.8 14.003 35.112 15.637 ;
     RECT  18.48 15.251 20.904 15.779 ;
     RECT  6 15.443 6.696 15.877 ;
     RECT  4.896 14.387 4.92 16.019 ;
     RECT  16.608 15.251 17.448 16.019 ;
     RECT  5.904 15.877 6.696 16.211 ;
     RECT  22.896 15.493 25.08 16.261 ;
     RECT  26.736 14.821 26.76 16.307 ;
     RECT  34.8 15.637 35.208 16.501 ;
     RECT  22.32 16.261 25.08 16.979 ;
     RECT  6.24 16.211 6.696 17.075 ;
     RECT  18.48 15.779 19.8 17.077 ;
     RECT  20.784 15.779 20.904 17.077 ;
     RECT  29.232 14.819 30.936 17.077 ;
     RECT  22.896 16.979 25.08 17.123 ;
     RECT  40.2 2.151 40.512 17.461 ;
     RECT  16.704 16.019 17.448 17.507 ;
     RECT  17.424 17.507 17.448 17.555 ;
     RECT  18.48 17.077 20.904 17.603 ;
     RECT  7.8 15.443 13.512 17.605 ;
     RECT  14.496 12.899 14.52 17.605 ;
     RECT  32.016 14.819 32.088 17.605 ;
     RECT  4.656 16.261 4.68 18.131 ;
     RECT  32.016 17.605 32.424 18.277 ;
     RECT  34.8 16.501 36.072 18.419 ;
     RECT  7.8 17.605 14.52 18.421 ;
     RECT  22.896 17.123 24.312 18.517 ;
     RECT  20.784 17.603 20.904 18.565 ;
     RECT  22.8 18.517 24.312 18.565 ;
     RECT  22.8 18.565 25.08 18.707 ;
     RECT  18.48 17.603 19.8 18.757 ;
     RECT  31.968 18.277 32.424 18.851 ;
     RECT  28.176 13.859 28.2 19.237 ;
     RECT  29.184 17.077 30.936 19.237 ;
     RECT  2.4 13.045 2.856 19.333 ;
     RECT  4.608 18.805 4.632 19.379 ;
     RECT  22.896 18.707 25.08 19.379 ;
     RECT  6.24 17.075 6.552 19.429 ;
     RECT  7.8 18.421 14.808 19.475 ;
     RECT  33.456 18.757 33.48 19.573 ;
     RECT  34.8 18.419 35.112 19.573 ;
     RECT  18.432 18.757 19.8 19.763 ;
     RECT  33.456 19.573 35.112 19.955 ;
     RECT  22.896 19.379 24.408 20.003 ;
     RECT  31.968 18.851 32.376 20.003 ;
     RECT  32.016 20.003 32.376 20.051 ;
     RECT  2.4 19.333 2.952 20.533 ;
     RECT  7.8 19.475 14.328 20.579 ;
     RECT  39.936 17.461 40.512 20.819 ;
     RECT  5.856 19.429 6.552 20.867 ;
     RECT  17.376 19.909 17.4 20.867 ;
     RECT  36.864 19.621 36.888 20.867 ;
     RECT  7.8 20.579 14.232 21.107 ;
     RECT  18.432 19.763 19.512 21.251 ;
     RECT  20.784 18.565 21.768 21.395 ;
     RECT  26.064 19.333 26.088 21.395 ;
     RECT  40.2 20.819 40.512 21.973 ;
     RECT  2.4 20.533 3.288 22.069 ;
     RECT  22.896 20.003 24.312 22.165 ;
     RECT  28.176 19.237 30.936 22.165 ;
     RECT  32.016 20.051 32.04 22.165 ;
     RECT  22.8 22.165 24.312 22.501 ;
     RECT  28.176 22.165 32.04 22.547 ;
     RECT  22.56 22.501 24.312 22.645 ;
     RECT  33.888 19.955 35.112 22.693 ;
     RECT  7.8 21.107 13.512 22.741 ;
     RECT  33.312 22.693 35.112 22.741 ;
     RECT  16.56 22.741 16.584 22.789 ;
     RECT  28.176 22.547 29.712 22.835 ;
     RECT  2.4 22.069 3.432 23.027 ;
     RECT  38.16 22.165 38.184 23.123 ;
     RECT  39.6 21.973 40.512 23.317 ;
     RECT  25.632 22.597 25.656 23.411 ;
     RECT  33.312 22.741 35.208 23.507 ;
     RECT  5.088 22.597 5.112 23.555 ;
     RECT  16.56 22.789 17.16 23.605 ;
     RECT  28.176 22.835 28.344 23.701 ;
     RECT  16.224 23.605 17.16 23.843 ;
     RECT  39.264 23.317 40.512 23.845 ;
     RECT  7.8 22.741 14.232 23.987 ;
     RECT  16.224 23.843 16.584 24.133 ;
     RECT  18.432 21.251 19.368 24.181 ;
     RECT  18.384 24.181 19.368 24.469 ;
     RECT  20.784 21.395 20.904 24.469 ;
     RECT  30.816 22.547 32.04 24.563 ;
     RECT  21.888 22.645 24.312 24.613 ;
     RECT  33.888 23.507 35.208 24.613 ;
     RECT  30.816 24.563 31.128 24.659 ;
     RECT  6.528 20.867 6.552 24.949 ;
     RECT  38.688 23.845 40.512 25.091 ;
     RECT  7.8 23.987 13.704 25.139 ;
     RECT  18.384 24.469 20.904 25.139 ;
     RECT  15.36 24.133 16.584 25.285 ;
     RECT  6.288 24.949 6.552 25.523 ;
     RECT  27.36 23.701 28.344 25.715 ;
     RECT  31.056 24.659 31.128 25.715 ;
     RECT  36.336 25.237 36.36 25.715 ;
     RECT  32.976 24.613 35.208 25.763 ;
     RECT  15.168 25.285 16.584 26.197 ;
     RECT  6.288 25.523 6.456 26.341 ;
     RECT  15.168 26.197 16.968 26.387 ;
     RECT  21.888 24.613 24.696 26.387 ;
     RECT  10.464 25.139 13.704 26.677 ;
     RECT  27.888 25.715 28.344 26.725 ;
     RECT  29.4 22.835 29.712 26.725 ;
     RECT  6.144 26.341 6.456 26.819 ;
     RECT  27.888 26.725 29.712 26.819 ;
     RECT  38.16 26.197 38.184 26.819 ;
     RECT  27.936 26.819 29.712 26.869 ;
     RECT  31.056 25.715 31.08 26.869 ;
     RECT  6.144 26.819 6.408 26.915 ;
     RECT  37.056 26.773 37.08 27.061 ;
     RECT  18.384 25.139 19.368 27.109 ;
     RECT  18.384 27.109 19.464 27.205 ;
     RECT  20.784 25.139 20.904 27.205 ;
     RECT  27.936 26.869 31.08 27.299 ;
     RECT  15.168 26.387 16.872 27.347 ;
     RECT  18.384 27.205 20.904 27.349 ;
     RECT  32.976 25.763 35.112 27.733 ;
     RECT  22.128 26.387 24.696 27.781 ;
     RECT  25.68 26.197 25.704 27.781 ;
     RECT  22.128 27.781 25.704 27.875 ;
     RECT  6.144 26.915 6.168 27.877 ;
     RECT  7.8 25.139 9.336 28.019 ;
     RECT  36.48 27.061 37.08 28.163 ;
     RECT  29.4 27.299 31.08 28.211 ;
     RECT  10.368 26.677 13.704 28.261 ;
     RECT  15.168 27.347 16.248 28.261 ;
     RECT  22.128 27.875 25.368 28.405 ;
     RECT  18.384 27.349 21.096 28.499 ;
     RECT  32.928 27.733 35.112 28.885 ;
     RECT  7.8 28.019 8.808 29.029 ;
     RECT  10.368 28.261 16.248 29.029 ;
     RECT  18.384 28.499 19.464 29.029 ;
     RECT  32.736 28.885 35.112 29.075 ;
     RECT  36.48 28.163 36.6 29.123 ;
     RECT  33.792 29.075 35.112 29.171 ;
     RECT  29.4 28.211 30.264 29.267 ;
     RECT  38.208 27.877 38.232 29.507 ;
     RECT  18.336 29.029 19.464 29.509 ;
     RECT  18.288 29.509 19.464 29.795 ;
     RECT  22.08 28.405 25.368 30.035 ;
     RECT  7.8 29.029 16.248 30.227 ;
     RECT  22.08 30.035 24.696 30.275 ;
     RECT  27.936 27.299 28.344 30.275 ;
     RECT  32.736 29.075 32.76 30.277 ;
     RECT  33.792 29.171 33.816 30.277 ;
     RECT  22.128 30.275 24.696 30.371 ;
     RECT  18.288 29.795 18.912 30.373 ;
     RECT  36.576 29.123 36.6 30.757 ;
     RECT  6.144 27.877 6.312 30.851 ;
     RECT  20.784 28.499 21.096 30.851 ;
     RECT  27.936 30.275 27.96 30.949 ;
     RECT  7.8 30.227 15.096 30.997 ;
     RECT  26.256 30.613 26.28 31.379 ;
     RECT  32.736 30.277 33.816 31.379 ;
     RECT  7.44 30.997 15.096 31.475 ;
     RECT  27.696 30.949 27.96 31.669 ;
     RECT  4.8 28.213 4.824 31.861 ;
     RECT  6.144 30.851 6.264 31.861 ;
     RECT  7.44 31.475 13.944 31.861 ;
     RECT  32.736 31.379 32.76 31.861 ;
     RECT  16.224 30.227 16.248 31.955 ;
     RECT  36.576 30.757 36.744 32.195 ;
     RECT  17.904 30.373 18.912 32.291 ;
     RECT  18.24 32.291 18.912 32.531 ;
     RECT  30.72 31.861 30.744 32.771 ;
     RECT  33.792 31.379 33.816 32.771 ;
     RECT  31.968 31.861 32.76 32.821 ;
     RECT  31.968 32.821 33 32.867 ;
     RECT  39.264 25.091 40.512 33.013 ;
     RECT  29.4 29.267 29.712 33.061 ;
     RECT  20.832 30.851 21.096 33.107 ;
     RECT  22.128 30.371 24.552 33.107 ;
     RECT  18.384 32.531 18.912 33.253 ;
     RECT  34.8 29.171 35.112 33.397 ;
     RECT  36.576 32.195 36.6 33.397 ;
     RECT  20.88 33.107 21.096 33.589 ;
     RECT  22.128 33.107 24.312 33.589 ;
     RECT  16.272 32.197 16.44 33.637 ;
     RECT  4.8 31.861 5.16 33.683 ;
     RECT  5.136 33.683 5.16 33.827 ;
     RECT  18.384 33.253 19.368 33.877 ;
     RECT  26.784 31.669 27.96 34.115 ;
     RECT  26.784 34.115 26.808 34.163 ;
     RECT  20.88 33.589 24.312 34.165 ;
     RECT  6.144 31.861 13.944 34.213 ;
     RECT  14.928 31.475 15.096 34.213 ;
     RECT  20.784 34.165 24.312 34.213 ;
     RECT  6.144 34.213 15.096 34.355 ;
     RECT  16.272 33.637 17.112 34.355 ;
     RECT  20.784 34.213 24.408 34.355 ;
     RECT  34.176 33.397 35.112 34.357 ;
     RECT  36.48 33.397 36.6 34.357 ;
     RECT  38.64 33.013 40.512 34.403 ;
     RECT  29.4 33.061 30.264 34.595 ;
     RECT  31.968 32.867 31.992 34.595 ;
     RECT  34.176 34.357 36.6 34.595 ;
     RECT  22.128 34.355 24.408 34.741 ;
     RECT  18.288 33.877 19.368 34.835 ;
     RECT  22.128 34.741 24.456 34.931 ;
     RECT  20.784 34.355 21.096 35.219 ;
     RECT  27.792 34.115 27.96 35.317 ;
     RECT  7.44 34.355 15.096 35.363 ;
     RECT  20.784 35.219 20.904 35.363 ;
     RECT  40.2 34.403 40.512 35.461 ;
     RECT  38.64 34.403 38.664 35.507 ;
     RECT  34.8 34.595 36.6 35.939 ;
     RECT  22.128 34.931 24.408 35.989 ;
     RECT  27.36 35.317 27.96 36.275 ;
     RECT  7.44 35.363 14.856 36.325 ;
     RECT  27.36 36.275 27.384 36.419 ;
     RECT  7.344 36.325 14.856 36.515 ;
     RECT  16.272 34.355 17.064 36.565 ;
     RECT  22.032 35.989 24.408 36.757 ;
     RECT  21.936 36.757 24.408 36.901 ;
     RECT  29.4 34.595 29.712 36.901 ;
     RECT  32.976 32.867 33 36.947 ;
     RECT  7.344 36.515 14.232 37.043 ;
     RECT  21.936 36.901 24.792 37.955 ;
     RECT  7.344 37.043 14.088 38.005 ;
     RECT  6.144 34.355 6.264 38.437 ;
     RECT  7.296 38.005 14.088 38.437 ;
     RECT  18.384 34.835 18.912 38.533 ;
     RECT  18.384 38.533 19.176 38.677 ;
     RECT  28.464 36.901 29.712 38.677 ;
     RECT  20.88 35.363 20.904 38.725 ;
     RECT  39.888 35.461 40.512 38.725 ;
     RECT  20.784 38.725 20.904 38.771 ;
     RECT  34.8 35.939 36.552 38.771 ;
     RECT  6.144 38.437 14.088 38.773 ;
     RECT  15.984 36.565 17.064 39.107 ;
     RECT  6.048 38.773 14.088 39.203 ;
     RECT  23.856 37.955 24.792 39.203 ;
     RECT  28.464 38.677 30.552 39.395 ;
     RECT  36.144 38.771 36.552 39.395 ;
     RECT  39.84 38.725 40.512 39.395 ;
     RECT  17.04 39.107 17.064 39.637 ;
     RECT  28.464 39.395 30.504 39.637 ;
     RECT  15.984 39.107 16.056 39.779 ;
     RECT  32.88 39.637 32.904 39.779 ;
     RECT  23.856 39.203 24.552 40.019 ;
     RECT  6.048 39.203 13.896 40.259 ;
     RECT  27.6 39.637 30.504 40.307 ;
     RECT  2.4 23.027 3.288 40.357 ;
     RECT  17.04 39.637 17.304 40.451 ;
     RECT  27.6 40.307 27.624 40.499 ;
     RECT  29.4 40.307 30.504 40.979 ;
     RECT  23.856 40.019 24.456 41.029 ;
     RECT  20.784 38.771 20.808 41.075 ;
     RECT  0.24 14.869 0.264 41.219 ;
     RECT  36.528 39.395 36.552 41.365 ;
     RECT  36.528 41.365 37.176 41.411 ;
     RECT  6.624 40.259 13.896 41.413 ;
     RECT  15.984 39.779 16.008 41.413 ;
     RECT  17.04 40.451 17.064 41.413 ;
     RECT  15.984 41.413 17.064 41.555 ;
     RECT  6.624 41.413 14.472 41.557 ;
     RECT  21.936 37.955 22.584 41.749 ;
     RECT  18.384 38.677 19.656 41.939 ;
     RECT  29.4 40.979 29.712 42.037 ;
     RECT  23.856 41.029 25.128 42.227 ;
     RECT  15.984 41.555 16.008 42.517 ;
     RECT  17.04 41.555 17.064 42.517 ;
     RECT  2.4 40.357 3.864 42.613 ;
     RECT  27.648 41.605 27.672 42.707 ;
     RECT  40.2 39.395 40.512 42.709 ;
     RECT  15.984 42.517 17.064 42.755 ;
     RECT  2.4 42.613 3.96 42.803 ;
     RECT  29.4 42.037 30.408 42.803 ;
     RECT  16.272 42.755 17.064 42.851 ;
     RECT  16.416 42.851 17.064 42.995 ;
     RECT  18.6 41.939 19.656 43.045 ;
     RECT  21.12 41.749 22.584 43.045 ;
     RECT  6.048 41.557 14.472 43.235 ;
     RECT  23.856 42.227 24.408 43.285 ;
     RECT  34.8 38.771 35.112 43.285 ;
     RECT  18.6 43.045 22.584 43.379 ;
     RECT  31.68 42.709 31.704 43.571 ;
     RECT  29.4 42.803 29.712 43.861 ;
     RECT  23.664 43.285 24.408 44.387 ;
     RECT  6.144 43.235 14.472 44.437 ;
     RECT  37.152 41.411 37.176 44.437 ;
     RECT  34.8 43.285 35.784 44.483 ;
     RECT  5.088 44.437 5.112 44.869 ;
     RECT  4.896 44.869 5.112 44.915 ;
     RECT  17.04 42.995 17.064 44.965 ;
     RECT  18.6 43.379 20.28 44.965 ;
     RECT  17.04 44.965 20.28 45.109 ;
     RECT  39.984 42.709 40.512 45.109 ;
     RECT  21.936 43.379 22.584 45.253 ;
     RECT  16.032 44.965 16.056 45.299 ;
     RECT  21.648 45.253 22.584 45.587 ;
     RECT  37.056 44.437 37.176 45.731 ;
     RECT  17.04 45.109 20.376 45.875 ;
     RECT  21.888 45.587 22.584 46.069 ;
     RECT  23.856 44.387 24.408 46.069 ;
     RECT  17.04 45.875 17.064 46.117 ;
     RECT  6.144 44.437 14.808 46.163 ;
     RECT  11.808 46.163 14.808 46.453 ;
     RECT  39.408 45.109 40.512 46.499 ;
     RECT  11.808 46.453 14.856 46.595 ;
     RECT  27.696 44.821 27.72 46.645 ;
     RECT  29.232 43.861 29.712 46.645 ;
     RECT  25.92 45.253 25.944 46.691 ;
     RECT  2.4 42.803 3.864 47.221 ;
     RECT  6.144 46.163 10.776 47.269 ;
     RECT  11.808 46.595 14.472 47.269 ;
     RECT  16.224 46.117 17.064 47.269 ;
     RECT  33.744 43.669 33.768 47.317 ;
     RECT  33.648 47.317 33.768 47.363 ;
     RECT  21.888 46.069 24.408 47.701 ;
     RECT  4.896 44.915 4.92 47.845 ;
     RECT  37.152 45.731 37.176 48.179 ;
     RECT  39.84 46.499 40.512 48.277 ;
     RECT  16.176 47.269 17.064 48.373 ;
     RECT  15.936 48.373 17.064 48.419 ;
     RECT  18.6 45.875 20.376 48.421 ;
     RECT  34.8 44.483 35.688 48.515 ;
     RECT  21.888 47.701 24.6 48.661 ;
     RECT  25.68 48.181 25.704 48.661 ;
     RECT  31.584 45.733 31.608 48.757 ;
     RECT  21.888 48.661 25.704 48.803 ;
     RECT  31.584 48.757 31.896 48.803 ;
     RECT  4.896 47.845 4.968 48.853 ;
     RECT  6.144 47.269 14.472 48.853 ;
     RECT  34.8 48.515 35.64 48.899 ;
     RECT  21.888 48.803 24.6 49.043 ;
     RECT  25.68 48.803 25.704 49.043 ;
     RECT  27.696 46.645 29.712 49.235 ;
     RECT  18.6 48.421 20.52 49.285 ;
     RECT  27.696 49.235 27.72 49.285 ;
     RECT  18.48 49.285 20.52 49.571 ;
     RECT  4.896 48.853 14.472 49.619 ;
     RECT  18.48 49.571 20.088 50.051 ;
     RECT  27.024 49.285 27.72 50.051 ;
     RECT  29.136 49.235 29.712 50.053 ;
     RECT  2.4 47.221 3.912 50.101 ;
     RECT  4.896 49.619 8.112 50.101 ;
     RECT  38.592 48.805 38.616 50.291 ;
     RECT  18.48 50.051 19.752 50.339 ;
     RECT  21.888 49.043 22.584 50.485 ;
     RECT  36.576 49.525 36.6 50.579 ;
     RECT  24 49.043 24.6 50.581 ;
     RECT  2.4 50.101 8.112 50.629 ;
     RECT  29.136 50.053 30.12 50.677 ;
     RECT  15.936 48.419 15.96 50.771 ;
     RECT  27.024 50.051 27.288 50.821 ;
     RECT  26.784 50.821 27.288 50.915 ;
     RECT  26.784 50.915 26.808 51.253 ;
     RECT  34.8 48.899 35.112 51.253 ;
     RECT  2.304 50.629 8.112 51.395 ;
     RECT  26.304 51.253 26.808 51.491 ;
     RECT  28.56 50.677 30.12 51.827 ;
     RECT  21.36 50.485 22.584 51.973 ;
     RECT  23.904 50.581 24.6 51.973 ;
     RECT  33.648 47.363 33.672 51.973 ;
     RECT  34.656 51.253 35.448 51.973 ;
     RECT  33.648 51.973 35.448 52.019 ;
     RECT  26.784 51.491 26.808 52.067 ;
     RECT  17.04 48.419 17.064 52.069 ;
     RECT  16.896 52.069 17.064 52.115 ;
     RECT  18.6 50.339 19.752 52.163 ;
     RECT  7.68 51.395 8.112 52.165 ;
     RECT  9.312 49.619 14.472 52.165 ;
     RECT  34.176 52.019 35.448 52.165 ;
     RECT  34.176 52.165 36.072 52.211 ;
     RECT  39.792 48.277 40.512 52.213 ;
     RECT  18.6 52.163 19.416 52.259 ;
     RECT  7.68 52.165 14.472 52.451 ;
     RECT  7.8 52.451 14.472 52.547 ;
     RECT  21.36 51.973 24.6 52.693 ;
     RECT  2.304 51.395 6.168 52.981 ;
     RECT  9.36 52.547 14.472 53.603 ;
     RECT  34.656 52.211 36.072 53.603 ;
     RECT  39.36 52.213 40.512 53.651 ;
     RECT  31.872 48.803 31.896 53.749 ;
     RECT  28.752 51.827 30.12 53.843 ;
     RECT  21.264 52.693 24.6 54.133 ;
     RECT  7.8 52.547 8.112 54.181 ;
     RECT  9.36 53.603 13.656 54.563 ;
     RECT  10.176 54.563 13.656 54.611 ;
     RECT  16.896 52.115 16.92 54.613 ;
     RECT  18.6 52.259 18.912 54.613 ;
     RECT  2.304 52.981 6.216 54.661 ;
     RECT  7.392 54.181 8.112 54.707 ;
     RECT  16.896 54.613 18.912 54.707 ;
     RECT  20.496 54.133 24.6 54.709 ;
     RECT  31.584 53.749 31.896 54.709 ;
     RECT  10.224 54.611 13.656 54.755 ;
     RECT  26.256 53.557 26.28 54.755 ;
     RECT  34.8 53.603 36.072 54.755 ;
     RECT  20.496 54.709 25.032 54.995 ;
     RECT  29.04 53.843 30.12 54.995 ;
     RECT  29.04 54.995 29.832 55.093 ;
     RECT  15.696 54.085 15.72 55.235 ;
     RECT  31.584 54.709 31.992 55.283 ;
     RECT  17.856 54.707 18.912 55.427 ;
     RECT  22.56 54.995 25.032 55.427 ;
     RECT  10.224 54.755 11.928 55.475 ;
     RECT  13.2 54.755 13.656 55.715 ;
     RECT  2.304 54.661 6.36 55.813 ;
     RECT  7.8 54.707 8.112 55.813 ;
     RECT  31.584 55.283 31.608 55.907 ;
     RECT  34.8 54.755 35.928 55.909 ;
     RECT  28.32 55.093 29.832 55.955 ;
     RECT  34.8 55.909 36.168 55.955 ;
     RECT  23.664 55.427 25.032 56.243 ;
     RECT  40.2 53.651 40.512 56.245 ;
     RECT  23.904 56.243 25.032 56.387 ;
     RECT  20.496 54.995 21.288 56.531 ;
     RECT  10.224 55.475 11.784 56.723 ;
     RECT  24 56.387 25.032 56.723 ;
     RECT  11.376 56.723 11.784 56.725 ;
     RECT  11.376 56.725 12.168 57.059 ;
     RECT  21.264 56.531 21.288 57.059 ;
     RECT  36.144 55.955 36.168 57.059 ;
     RECT  39.504 56.245 40.512 57.541 ;
     RECT  2.304 55.813 8.112 57.635 ;
     RECT  29.088 55.955 29.832 57.685 ;
     RECT  24 56.723 24.408 57.827 ;
     RECT  38.736 57.541 40.512 58.019 ;
     RECT  11.76 57.059 12.168 58.117 ;
     RECT  13.2 55.715 13.512 58.117 ;
     RECT  22.56 55.427 22.584 58.117 ;
     RECT  24 57.827 24.312 58.117 ;
     RECT  29.088 57.685 30.216 58.357 ;
     RECT  10.224 56.723 10.248 58.501 ;
     RECT  18.6 55.427 18.912 58.549 ;
     RECT  9.648 58.501 10.248 58.595 ;
     RECT  37.584 56.869 37.608 58.643 ;
     RECT  11.76 58.117 13.512 58.645 ;
     RECT  18.6 58.549 19.704 58.645 ;
     RECT  34.8 55.955 35.112 58.645 ;
     RECT  38.736 58.019 38.76 58.691 ;
     RECT  28.656 58.357 30.216 59.077 ;
     RECT  18.6 58.645 20.136 59.315 ;
     RECT  18.6 59.315 19.704 59.363 ;
     RECT  22.56 58.117 24.312 59.509 ;
     RECT  22.224 59.509 24.312 59.555 ;
     RECT  6.816 57.635 8.112 59.605 ;
     RECT  6.816 59.605 8.52 59.701 ;
     RECT  9.648 58.595 9.672 59.701 ;
     RECT  23.376 59.555 24.312 59.795 ;
     RECT  2.304 57.635 5.64 59.797 ;
     RECT  6.816 59.701 9.672 59.797 ;
     RECT  28.416 59.077 30.216 59.797 ;
     RECT  28.416 59.797 30.504 59.843 ;
     RECT  39.84 58.019 40.512 59.843 ;
     RECT  11.76 58.645 13.608 59.891 ;
     RECT  15.168 58.645 15.192 59.987 ;
     RECT  22.224 59.555 22.248 60.083 ;
     RECT  11.76 59.891 13.512 60.181 ;
     RECT  34.8 58.645 35.928 60.181 ;
     RECT  34.8 60.181 36.072 60.661 ;
     RECT  28.848 59.843 30.504 60.803 ;
     RECT  11.712 60.181 13.512 60.851 ;
     RECT  40.2 59.843 40.512 60.949 ;
     RECT  2.304 59.797 10.152 61.043 ;
     RECT  11.712 60.851 11.832 61.043 ;
     RECT  29.04 60.803 30.504 61.235 ;
     RECT  29.4 61.235 30.504 61.525 ;
     RECT  13.2 60.851 13.512 62.005 ;
     RECT  26.208 61.189 26.232 62.051 ;
     RECT  34.224 60.661 36.072 62.147 ;
     RECT  39.552 60.949 40.512 62.147 ;
     RECT  7.44 61.043 10.152 62.195 ;
     RECT  11.808 61.043 11.832 62.195 ;
     RECT  2.304 61.043 6.264 62.437 ;
     RECT  2.304 62.437 6.312 63.157 ;
     RECT  7.44 62.195 10.056 63.157 ;
     RECT  2.304 63.157 10.056 63.205 ;
     RECT  13.104 62.005 13.512 63.205 ;
     RECT  2.304 63.205 10.776 63.781 ;
     RECT  2.304 63.781 10.824 64.357 ;
     RECT  34.512 62.147 36.072 64.451 ;
     RECT  34.704 64.451 36.072 64.739 ;
     RECT  13.056 63.205 13.512 64.741 ;
     RECT  2.304 64.357 11.064 65.027 ;
     RECT  13.056 64.741 14.424 65.749 ;
     RECT  12.72 65.749 14.424 66.707 ;
     RECT  40.2 62.147 40.512 67.237 ;
     RECT  2.304 65.027 10.92 67.283 ;
     RECT  29.4 61.525 31.272 67.331 ;
     RECT  34.8 64.739 36.072 67.331 ;
     RECT  13.2 66.707 14.424 67.571 ;
     RECT  4.32 67.283 10.92 67.667 ;
     RECT  4.32 67.667 10.248 67.859 ;
     RECT  4.32 67.859 10.152 67.907 ;
     RECT  2.304 67.283 3.336 68.869 ;
     RECT  4.32 67.907 9.672 68.869 ;
     RECT  20.784 67.333 20.808 68.917 ;
     RECT  39.36 67.237 40.512 68.963 ;
     RECT  37.92 67.141 37.944 69.013 ;
     RECT  15.84 68.917 15.864 69.251 ;
     RECT  20.784 68.917 21.048 69.301 ;
     RECT  34.8 67.331 35.112 69.349 ;
     RECT  37.92 69.013 38.088 69.491 ;
     RECT  38.064 69.491 38.088 69.539 ;
     RECT  31.632 68.917 31.656 69.779 ;
     RECT  25.632 69.301 25.656 69.829 ;
     RECT  18.6 59.363 18.912 70.069 ;
     RECT  25.632 69.829 25.992 70.115 ;
     RECT  2.304 68.869 9.672 70.163 ;
     RECT  13.2 67.571 13.608 70.309 ;
     RECT  20.784 69.301 21.864 70.643 ;
     RECT  24 59.795 24.312 70.645 ;
     RECT  34.032 69.349 35.112 70.691 ;
     RECT  20.976 70.643 21.864 70.693 ;
     RECT  2.4 70.163 9.672 70.739 ;
     RECT  2.4 70.739 3.624 70.787 ;
     RECT  4.752 70.739 9.528 70.787 ;
     RECT  18 70.069 18.912 70.789 ;
     RECT  25.968 70.115 25.992 70.883 ;
     RECT  10.848 70.645 10.872 71.125 ;
     RECT  10.848 71.125 10.968 71.221 ;
     RECT  29.4 67.331 30.552 71.221 ;
     RECT  18 70.789 19.032 71.315 ;
     RECT  24 70.645 24.792 71.411 ;
     RECT  13.104 70.309 13.608 71.413 ;
     RECT  20.976 70.693 22.2 71.651 ;
     RECT  4.752 70.787 9.288 71.749 ;
     RECT  4.752 71.749 9.336 71.797 ;
     RECT  18.6 71.315 19.032 71.987 ;
     RECT  10.848 71.221 12.024 72.085 ;
     RECT  13.104 71.413 13.656 72.085 ;
     RECT  3.936 71.797 9.336 72.181 ;
     RECT  10.848 72.085 13.656 72.181 ;
     RECT  26.304 71.701 26.328 72.277 ;
     RECT  3.936 72.181 13.656 72.325 ;
     RECT  3.84 72.325 13.656 72.371 ;
     RECT  21.696 71.651 22.2 72.419 ;
     RECT  21.696 72.419 21.72 72.467 ;
     RECT  29.4 71.221 30.84 72.659 ;
     RECT  3.84 72.371 13.608 72.851 ;
     RECT  2.4 70.787 2.712 72.853 ;
     RECT  2.4 72.853 2.856 72.901 ;
     RECT  3.84 72.851 13.512 72.901 ;
     RECT  32.448 72.325 32.472 72.995 ;
     RECT  24 71.411 24.312 73.477 ;
     RECT  26.304 72.277 26.712 73.811 ;
     RECT  2.4 72.901 13.512 73.861 ;
     RECT  16.8 71.749 16.824 73.909 ;
     RECT  18.6 71.987 18.912 73.909 ;
     RECT  16.656 73.909 16.824 73.955 ;
     RECT  33.648 73.477 33.672 74.101 ;
     RECT  34.8 70.691 35.112 74.101 ;
     RECT  29.4 72.659 30.552 74.147 ;
     RECT  33.648 74.101 35.112 74.147 ;
     RECT  39.072 71.221 39.096 74.291 ;
     RECT  18.192 73.909 18.912 75.013 ;
     RECT  34.176 74.147 35.112 75.251 ;
     RECT  24 73.477 24.408 75.299 ;
     RECT  26.304 73.811 26.328 75.397 ;
     RECT  18.192 75.013 19.56 75.827 ;
     RECT  18.192 75.827 18.912 75.875 ;
     RECT  36.816 74.581 36.84 75.971 ;
     RECT  16.656 73.955 16.68 76.163 ;
     RECT  26.304 75.397 26.664 76.403 ;
     RECT  2.4 73.861 13.704 76.499 ;
     RECT  29.4 74.147 29.832 76.499 ;
     RECT  24 75.299 24.312 76.885 ;
     RECT  2.4 76.499 13.656 76.979 ;
     RECT  15.312 72.421 15.336 76.979 ;
     RECT  26.64 76.403 26.664 76.979 ;
     RECT  24 76.885 25.128 77.555 ;
     RECT  29.4 76.499 29.712 77.653 ;
     RECT  2.4 76.979 11.496 77.891 ;
     RECT  2.4 77.891 11.352 78.131 ;
     RECT  2.4 78.131 10.008 78.517 ;
     RECT  12.528 76.979 13.656 78.707 ;
     RECT  11.136 78.131 11.352 78.755 ;
     RECT  13.104 78.707 13.656 78.755 ;
     RECT  13.2 78.755 13.656 78.995 ;
     RECT  31.584 77.029 31.608 79.139 ;
     RECT  34.368 75.251 35.112 79.139 ;
     RECT  2.304 78.517 10.008 79.283 ;
     RECT  13.2 78.995 13.608 79.283 ;
     RECT  2.304 79.283 4.104 79.331 ;
     RECT  7.8 79.283 10.008 79.331 ;
     RECT  6.192 79.283 6.744 79.379 ;
     RECT  29.4 77.653 29.832 79.475 ;
     RECT  2.4 79.331 4.104 79.523 ;
     RECT  4.08 79.523 4.104 79.619 ;
     RECT  5.136 79.283 5.16 79.763 ;
     RECT  6.72 79.379 6.744 79.763 ;
     RECT  11.136 78.755 11.16 79.813 ;
     RECT  2.4 79.523 2.712 79.929 ;
     RECT  7.8 79.331 8.112 79.929 ;
     RECT  13.2 79.283 13.512 79.929 ;
     RECT  18.6 75.875 18.912 79.929 ;
     RECT  24 77.555 24.312 79.929 ;
     RECT  29.4 79.475 29.712 79.929 ;
     RECT  34.8 79.139 35.112 79.929 ;
     RECT  40.2 68.963 40.512 79.929 ;
     RECT  2.4 79.929 2.52 79.943 ;
     RECT  7.8 79.929 7.92 79.943 ;
     RECT  13.2 79.929 13.32 79.943 ;
     RECT  18.6 79.929 18.72 79.943 ;
     RECT  24 79.929 24.12 79.943 ;
     RECT  29.4 79.929 29.52 79.943 ;
     RECT  34.8 79.929 34.92 79.943 ;
     RECT  40.2 79.929 40.32 79.943 ;
     RECT  9.168 79.331 10.008 80.341 ;
     RECT  9.168 80.341 10.056 80.869 ;
     RECT  11.136 79.813 11.208 80.869 ;
     RECT  9.024 80.869 11.208 81.936 ;
     RECT  7.92 2.137 9.024 2.151 ;
     RECT  24.312 2.245 25.632 3.587 ;
     RECT  18.912 2.821 20.016 3.587 ;
     RECT  29.712 2.821 30.768 2.963 ;
     RECT  30.792 2.821 32.016 2.963 ;
     RECT  38.808 2.869 40.2 4.019 ;
     RECT  29.712 2.963 32.016 3.877 ;
     RECT  23.568 3.443 24 4.501 ;
     RECT  28.296 3.541 29.28 4.405 ;
     RECT  29.712 3.877 30.816 6.229 ;
     RECT  30.84 3.877 32.016 5.653 ;
     RECT  35.112 4.163 35.352 5.605 ;
     RECT  22.632 4.501 24 5.747 ;
     RECT  39.192 5.749 40.2 6.851 ;
     RECT  19.416 5.797 20.88 6.323 ;
     RECT  18.288 6.131 18.6 7.189 ;
     RECT  24.312 6.277 25.824 8.723 ;
     RECT  6.552 6.757 7.8 7.333 ;
     RECT  39.168 6.851 40.2 7.765 ;
     RECT  28.104 7.093 29.232 7.909 ;
     RECT  2.712 7.381 3.936 9.155 ;
     RECT  38.808 7.765 40.2 8.821 ;
     RECT  16.392 7.909 17.76 8.579 ;
     RECT  28.104 7.909 29.088 8.437 ;
     RECT  6.552 8.723 7.8 12.277 ;
     RECT  24.312 8.723 25.704 9.253 ;
     RECT  39.192 8.821 40.2 11.027 ;
     RECT  28.248 8.867 29.232 9.491 ;
     RECT  2.712 9.155 2.904 9.637 ;
     RECT  24.456 9.253 25.704 9.637 ;
     RECT  28.104 9.491 29.232 11.221 ;
     RECT  19.368 9.493 20.592 9.539 ;
     RECT  19.368 9.539 20.88 11.459 ;
     RECT  24.456 9.637 25.68 10.693 ;
     RECT  5.016 10.835 6 11.411 ;
     RECT  13.512 10.883 13.896 12.181 ;
     RECT  39.168 11.027 40.2 11.941 ;
     RECT  28.104 11.221 29.088 11.459 ;
     RECT  18.912 11.459 20.88 12.853 ;
     RECT  28.104 11.459 29.232 13.045 ;
     RECT  37.608 11.941 38.88 14.675 ;
     RECT  38.904 11.941 40.2 15.491 ;
     RECT  16.632 12.037 18.096 14.773 ;
     RECT  13.512 12.181 14.784 12.853 ;
     RECT  13.512 12.853 14.496 17.605 ;
     RECT  18.912 12.853 20.352 14.821 ;
     RECT  4.536 13.285 6 14.341 ;
     RECT  28.08 13.715 28.176 14.821 ;
     RECT  33.672 13.715 34.8 14.387 ;
     RECT  28.2 13.859 29.232 17.077 ;
     RECT  36.552 13.957 37.584 14.675 ;
     RECT  35.112 14.003 36.528 14.867 ;
     RECT  24.936 14.339 25.08 15.493 ;
     RECT  4.92 14.341 6 15.877 ;
     RECT  30.936 14.819 32.016 18.277 ;
     RECT  26.76 14.821 28.176 16.307 ;
     RECT  35.112 14.867 35.208 15.637 ;
     RECT  17.448 15.251 18.48 17.555 ;
     RECT  6.696 15.443 7.8 17.075 ;
     RECT  19.8 15.779 20.784 17.077 ;
     RECT  4.92 15.877 5.904 16.019 ;
     RECT  20.904 16.261 22.32 16.979 ;
     RECT  6.552 17.075 7.8 25.523 ;
     RECT  28.2 17.077 29.184 19.237 ;
     RECT  24.312 17.123 25.08 18.565 ;
     RECT  18.432 17.555 18.48 18.757 ;
     RECT  19.8 17.603 20.784 19.763 ;
     RECT  30.936 18.277 31.968 20.003 ;
     RECT  21.768 18.565 22.8 18.707 ;
     RECT  21.768 18.707 22.896 21.395 ;
     RECT  32.424 18.757 33.456 18.851 ;
     RECT  33.48 18.757 34.8 19.573 ;
     RECT  32.376 18.851 33.456 19.955 ;
     RECT  25.08 19.333 26.064 19.379 ;
     RECT  19.512 19.763 20.784 21.251 ;
     RECT  17.4 19.909 18.432 20.867 ;
     RECT  32.376 19.955 33.888 20.051 ;
     RECT  30.936 20.003 32.016 22.165 ;
     RECT  39.936 20.819 40.2 21.973 ;
     RECT  19.368 21.251 20.784 24.469 ;
     RECT  20.904 21.395 22.896 22.165 ;
     RECT  20.904 22.165 22.8 22.501 ;
     RECT  38.184 22.165 39.6 23.123 ;
     RECT  20.904 22.501 22.56 22.645 ;
     RECT  29.712 22.547 30.816 24.659 ;
     RECT  5.112 22.597 6.528 23.555 ;
     RECT  24.312 22.597 25.632 23.411 ;
     RECT  20.904 22.645 21.888 26.387 ;
     RECT  32.04 22.693 33.312 23.507 ;
     RECT  17.16 22.789 18.432 23.843 ;
     RECT  28.344 22.835 29.4 26.725 ;
     RECT  38.688 23.123 39.6 23.317 ;
     RECT  38.688 23.317 39.264 23.845 ;
     RECT  24.312 23.411 24.696 24.613 ;
     RECT  32.04 23.507 33.888 24.563 ;
     RECT  6.288 23.555 6.528 24.949 ;
     RECT  18.384 23.843 18.432 24.181 ;
     RECT  13.704 23.987 14.232 24.133 ;
     RECT  13.704 24.133 15.36 25.285 ;
     RECT  32.976 24.563 33.888 24.613 ;
     RECT  29.712 24.659 31.056 26.869 ;
     RECT  38.688 25.091 39.264 26.197 ;
     RECT  9.336 25.139 10.464 26.677 ;
     RECT  19.368 25.139 20.784 27.109 ;
     RECT  35.208 25.237 36.336 25.715 ;
     RECT  13.704 25.285 15.168 28.261 ;
     RECT  6.456 25.523 7.8 26.819 ;
     RECT  35.208 25.715 36.36 25.763 ;
     RECT  35.112 25.763 36.36 26.773 ;
     RECT  16.968 26.197 18.384 26.387 ;
     RECT  24.696 26.197 25.68 27.781 ;
     RECT  38.184 26.197 39.264 26.819 ;
     RECT  16.872 26.387 18.384 27.347 ;
     RECT  20.904 26.387 22.128 27.349 ;
     RECT  9.336 26.677 10.368 28.019 ;
     RECT  35.112 26.773 37.056 27.061 ;
     RECT  37.08 26.773 38.16 26.819 ;
     RECT  6.408 26.819 7.8 26.915 ;
     RECT  37.08 26.819 39.264 27.877 ;
     RECT  6.168 26.915 7.8 27.877 ;
     RECT  35.112 27.061 36.48 29.123 ;
     RECT  19.464 27.109 20.784 27.205 ;
     RECT  28.344 27.299 29.4 30.275 ;
     RECT  21.096 27.349 22.128 28.405 ;
     RECT  6.312 27.877 7.8 30.851 ;
     RECT  37.08 27.877 38.208 28.163 ;
     RECT  38.232 27.877 39.264 29.507 ;
     RECT  8.808 28.019 10.368 29.029 ;
     RECT  3.288 28.213 4.8 33.683 ;
     RECT  4.824 28.213 6.144 31.861 ;
     RECT  21.096 28.405 22.08 30.275 ;
     RECT  19.464 28.499 20.784 29.795 ;
     RECT  32.76 29.075 33.792 30.277 ;
     RECT  35.112 29.123 36.576 33.397 ;
     RECT  33.816 29.171 34.8 32.771 ;
     RECT  15.096 30.227 16.224 31.955 ;
     RECT  21.096 30.275 22.128 33.589 ;
     RECT  27.96 30.275 29.4 36.275 ;
     RECT  6.264 30.851 7.8 30.997 ;
     RECT  26.28 30.949 27.696 31.379 ;
     RECT  6.264 30.997 7.44 31.861 ;
     RECT  26.784 31.379 27.696 31.669 ;
     RECT  32.76 31.379 33.792 32.771 ;
     RECT  13.944 31.475 14.928 34.213 ;
     RECT  5.16 31.861 6.144 33.827 ;
     RECT  29.712 31.861 30.72 32.771 ;
     RECT  30.744 31.861 31.968 32.771 ;
     RECT  15.096 31.955 16.248 32.197 ;
     RECT  15.096 32.197 16.272 35.363 ;
     RECT  16.44 32.197 17.904 32.291 ;
     RECT  16.44 32.291 18.24 32.531 ;
     RECT  16.44 32.531 18.384 33.637 ;
     RECT  29.712 32.771 30.264 33.061 ;
     RECT  32.76 32.771 34.8 32.821 ;
     RECT  33 32.821 34.8 33.397 ;
     RECT  31.992 32.867 32.976 34.595 ;
     RECT  20.832 33.107 20.88 33.253 ;
     RECT  24.312 33.107 24.408 34.213 ;
     RECT  19.368 33.253 20.88 34.165 ;
     RECT  33 33.397 34.176 34.595 ;
     RECT  35.112 33.397 36.48 34.357 ;
     RECT  17.112 33.637 18.384 33.877 ;
     RECT  17.112 33.877 18.288 34.355 ;
     RECT  26.808 34.115 27.792 34.163 ;
     RECT  27.36 34.163 27.792 35.317 ;
     RECT  19.368 34.165 20.784 34.835 ;
     RECT  6.264 34.355 7.44 36.325 ;
     RECT  17.064 34.355 18.288 34.835 ;
     RECT  21.096 34.355 22.128 35.219 ;
     RECT  38.664 34.403 40.2 35.461 ;
     RECT  17.064 34.835 18.384 39.637 ;
     RECT  20.904 35.219 22.128 35.989 ;
     RECT  14.856 35.363 16.272 36.515 ;
     RECT  38.664 35.461 39.888 35.507 ;
     RECT  20.904 35.989 22.032 36.757 ;
     RECT  27.384 36.275 29.4 36.419 ;
     RECT  6.264 36.325 7.344 38.005 ;
     RECT  28.464 36.419 29.4 36.901 ;
     RECT  15.984 36.515 16.272 36.565 ;
     RECT  20.904 36.757 21.936 38.771 ;
     RECT  22.584 37.955 23.856 43.285 ;
     RECT  6.264 38.005 7.296 38.437 ;
     RECT  19.656 38.677 20.88 38.725 ;
     RECT  19.656 38.725 20.784 41.075 ;
     RECT  20.808 38.771 21.936 41.075 ;
     RECT  35.112 38.771 36.144 39.395 ;
     RECT  16.056 39.107 17.04 39.779 ;
     RECT  35.112 39.395 36.528 41.411 ;
     RECT  17.304 39.637 18.384 40.451 ;
     RECT  16.008 39.779 17.04 41.413 ;
     RECT  24.456 40.019 24.552 41.029 ;
     RECT  6.048 40.259 6.624 41.557 ;
     RECT  27.624 40.307 27.672 40.499 ;
     RECT  17.064 40.451 18.384 41.939 ;
     RECT  27.648 40.499 27.672 41.605 ;
     RECT  29.712 40.979 30.408 42.037 ;
     RECT  19.656 41.075 21.936 41.749 ;
     RECT  14.472 41.413 15.984 42.755 ;
     RECT  16.008 41.555 17.04 42.517 ;
     RECT  19.656 41.749 21.12 43.045 ;
     RECT  30.408 42.709 31.68 42.803 ;
     RECT  6.048 43.235 6.144 44.437 ;
     RECT  22.584 43.285 23.664 44.387 ;
     RECT  35.784 43.285 37.152 44.437 ;
     RECT  33.768 43.669 34.8 47.363 ;
     RECT  22.584 44.387 23.856 46.069 ;
     RECT  3.864 44.437 5.088 44.869 ;
     RECT  5.112 44.437 6.144 44.915 ;
     RECT  35.784 44.437 37.056 44.483 ;
     RECT  35.688 44.483 37.056 45.731 ;
     RECT  27.72 44.821 29.232 46.645 ;
     RECT  3.864 44.869 4.896 47.221 ;
     RECT  4.92 44.915 6.144 47.845 ;
     RECT  14.808 44.965 16.032 45.299 ;
     RECT  16.056 44.965 17.04 45.299 ;
     RECT  20.376 45.253 21.648 45.587 ;
     RECT  24.408 45.253 25.92 46.691 ;
     RECT  14.808 45.299 17.04 46.117 ;
     RECT  20.376 45.587 21.888 48.421 ;
     RECT  35.688 45.731 37.152 48.179 ;
     RECT  14.808 46.117 16.224 46.453 ;
     RECT  10.776 46.163 11.808 47.269 ;
     RECT  14.856 46.453 16.224 46.595 ;
     RECT  16.176 46.595 16.224 47.269 ;
     RECT  24.408 46.691 25.704 47.701 ;
     RECT  3.912 47.221 4.896 50.101 ;
     RECT  33.672 47.363 34.8 51.253 ;
     RECT  24.6 47.701 25.704 48.181 ;
     RECT  4.968 47.845 6.144 48.853 ;
     RECT  35.688 48.179 36.6 48.515 ;
     RECT  24.6 48.181 25.68 48.661 ;
     RECT  14.472 48.373 15.936 50.771 ;
     RECT  15.96 48.419 17.04 50.771 ;
     RECT  20.52 48.421 21.888 49.571 ;
     RECT  35.64 48.515 36.6 48.899 ;
     RECT  24.6 48.803 25.68 49.043 ;
     RECT  38.616 48.805 39.792 50.291 ;
     RECT  35.112 48.899 36.6 49.525 ;
     RECT  22.584 49.043 24 50.581 ;
     RECT  27.72 49.235 29.136 50.051 ;
     RECT  17.064 49.285 18.48 50.339 ;
     RECT  35.112 49.525 36.576 50.579 ;
     RECT  20.088 49.571 21.888 50.051 ;
     RECT  8.112 49.619 9.312 52.165 ;
     RECT  21.36 50.051 21.888 50.485 ;
     RECT  27.288 50.051 29.136 50.677 ;
     RECT  35.112 50.579 35.448 51.253 ;
     RECT  22.584 50.581 23.904 51.973 ;
     RECT  27.288 50.677 28.56 50.915 ;
     RECT  16.896 50.771 17.04 52.069 ;
     RECT  33.672 51.253 34.656 51.973 ;
     RECT  6.168 51.395 7.68 52.451 ;
     RECT  6.168 52.451 6.216 52.981 ;
     RECT  8.112 52.547 9.36 54.563 ;
     RECT  30.12 53.749 31.584 54.995 ;
     RECT  28.752 53.843 29.04 55.093 ;
     RECT  15.72 54.085 16.896 54.707 ;
     RECT  6.216 54.181 7.392 54.661 ;
     RECT  6.36 54.661 7.392 54.707 ;
     RECT  6.36 54.707 7.8 55.813 ;
     RECT  25.032 54.709 26.256 54.755 ;
     RECT  11.928 54.755 13.2 55.475 ;
     RECT  35.928 54.755 36.072 55.909 ;
     RECT  21.288 54.995 22.56 57.059 ;
     RECT  22.584 55.427 23.664 56.243 ;
     RECT  11.784 55.475 13.2 56.725 ;
     RECT  35.112 55.955 36.144 57.059 ;
     RECT  22.584 56.243 23.904 56.387 ;
     RECT  22.584 56.387 24 58.117 ;
     RECT  10.248 56.723 11.376 57.059 ;
     RECT  12.168 56.725 13.2 58.117 ;
     RECT  36.168 56.869 37.584 57.059 ;
     RECT  10.248 57.059 11.76 58.595 ;
     RECT  37.608 57.541 38.736 58.643 ;
     RECT  5.64 57.635 6.816 59.797 ;
     RECT  38.76 58.019 39.84 58.691 ;
     RECT  9.672 58.595 10.152 59.797 ;
     RECT  22.248 59.555 23.376 59.795 ;
     RECT  8.52 59.605 9.648 59.701 ;
     RECT  39.84 59.843 40.2 60.949 ;
     RECT  11.832 60.851 13.2 62.005 ;
     RECT  6.264 61.043 7.44 62.437 ;
     RECT  11.832 62.005 13.104 62.195 ;
     RECT  10.056 62.195 10.152 63.205 ;
     RECT  13.056 62.195 13.104 63.205 ;
     RECT  6.312 62.437 7.44 63.157 ;
     RECT  37.944 67.237 39.36 68.963 ;
     RECT  3.336 67.283 4.32 68.869 ;
     RECT  30.552 68.917 31.632 69.779 ;
     RECT  37.944 68.963 38.088 69.013 ;
     RECT  24.312 69.301 25.632 70.115 ;
     RECT  30.552 69.779 30.84 71.221 ;
     RECT  24.312 70.115 25.968 70.645 ;
     RECT  9.672 70.645 10.848 70.739 ;
     RECT  24.792 70.645 25.968 70.883 ;
     RECT  3.624 70.739 4.752 70.787 ;
     RECT  9.528 70.739 10.848 70.787 ;
     RECT  2.712 70.787 4.752 71.797 ;
     RECT  9.288 70.787 10.848 71.749 ;
     RECT  12.024 71.221 13.104 72.085 ;
     RECT  39.096 71.221 40.2 74.291 ;
     RECT  9.336 71.749 10.848 72.181 ;
     RECT  2.712 71.797 3.936 72.325 ;
     RECT  2.712 72.325 3.84 72.853 ;
     RECT  13.608 72.371 13.656 72.851 ;
     RECT  15.336 72.421 16.8 73.909 ;
     RECT  13.512 72.851 13.656 73.861 ;
     RECT  2.856 72.853 3.84 72.901 ;
     RECT  33.672 73.477 34.8 74.101 ;
     RECT  15.336 73.909 16.656 76.163 ;
     RECT  16.824 73.909 18.192 73.955 ;
     RECT  16.68 73.955 18.192 75.875 ;
     RECT  26.304 76.403 26.64 76.885 ;
     RECT  29.712 76.499 29.832 77.653 ;
     RECT  25.128 76.885 26.64 76.979 ;
     RECT  11.496 76.979 12.528 77.891 ;
     RECT  11.352 77.891 12.528 78.707 ;
     RECT  10.008 78.131 11.136 80.341 ;
     RECT  11.16 78.755 11.208 79.813 ;
     RECT  4.104 79.283 5.136 79.619 ;
     RECT  5.16 79.283 6.192 79.379 ;
     RECT  6.744 79.283 7.8 79.763 ;
     RECT  8.112 79.331 9.168 79.929 ;
     RECT  2.712 79.523 4.08 79.619 ;
     RECT  7.92 79.929 9.168 79.943 ;
     RECT  9.024 79.943 9.168 80.869 ;
     RECT  10.056 80.341 11.136 80.869 ;
  END
END ot_s81_markov_chunk4_native
END LIBRARY
